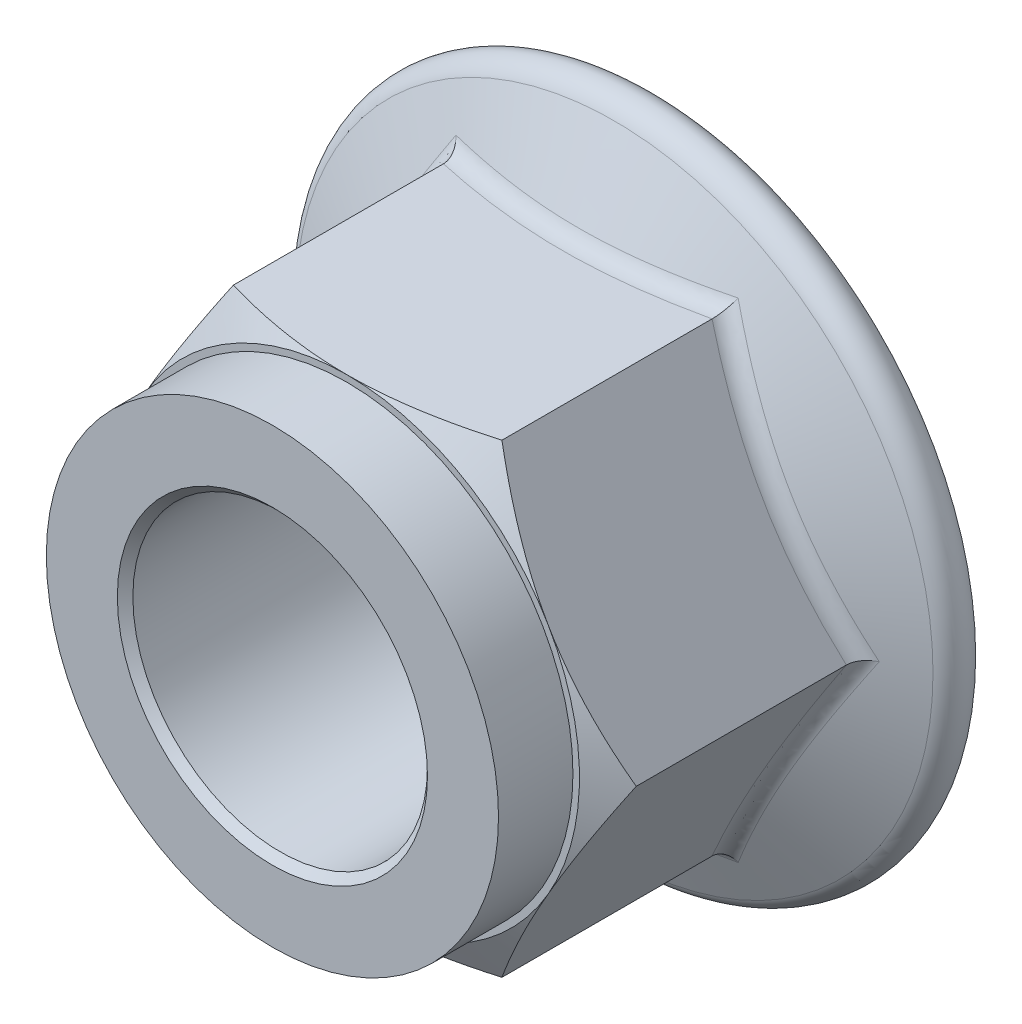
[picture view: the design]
ISO-10303-21;
HEADER;
FILE_DESCRIPTION(('STEP AP214'),'2;1');
FILE_NAME('part.step','',(''),(''),'','','');
FILE_SCHEMA(('AUTOMOTIVE_DESIGN { 1 0 10303 214 1 1 1 1 }'));
ENDSEC;
DATA;
#1=APPLICATION_CONTEXT('core data for automotive mechanical design processes');
#2=APPLICATION_PROTOCOL_DEFINITION('international standard','automotive_design',2000,#1);
#3=PRODUCT_CONTEXT('',#1,'mechanical');
#4=PRODUCT('Part','Part','',(#3));
#5=PRODUCT_RELATED_PRODUCT_CATEGORY('part','',(#4));
#6=PRODUCT_DEFINITION_FORMATION('','',#4);
#7=PRODUCT_DEFINITION_CONTEXT('part definition',#1,'design');
#8=PRODUCT_DEFINITION('design','',#6,#7);
#9=PRODUCT_DEFINITION_SHAPE('','',#8);
#10=(LENGTH_UNIT() NAMED_UNIT(*) SI_UNIT(.MILLI.,.METRE.));
#11=(NAMED_UNIT(*) PLANE_ANGLE_UNIT() SI_UNIT($,.RADIAN.));
#12=(NAMED_UNIT(*) SI_UNIT($,.STERADIAN.) SOLID_ANGLE_UNIT());
#13=UNCERTAINTY_MEASURE_WITH_UNIT(LENGTH_MEASURE(1.E-05),#10,'distance_accuracy_value','');
#14=(GEOMETRIC_REPRESENTATION_CONTEXT(3) GLOBAL_UNCERTAINTY_ASSIGNED_CONTEXT((#13)) GLOBAL_UNIT_ASSIGNED_CONTEXT((#10,
#11,#12)) REPRESENTATION_CONTEXT('',''));
#15=CARTESIAN_POINT('',(0.,0.,0.));
#16=DIRECTION('',(0.,0.,1.));
#17=DIRECTION('',(1.,0.,0.));
#18=AXIS2_PLACEMENT_3D('',#15,#16,#17);
#19=CARTESIAN_POINT('',(-8.66025403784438,-15.,0.));
#20=DIRECTION('',(0.,0.,-1.));
#21=DIRECTION('',(-1.,0.,0.));
#22=AXIS2_PLACEMENT_3D('',#19,#20,#21);
#23=PLANE('',#22);
#24=CARTESIAN_POINT('',(0.,0.,0.));
#25=DIRECTION('',(0.,0.,-1.));
#26=DIRECTION('',(-1.,0.,0.));
#27=AXIS2_PLACEMENT_3D('',#24,#25,#26);
#28=CIRCLE('',#27,15.);
#29=CARTESIAN_POINT('',(-12.9903810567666,7.5,0.));
#30=VERTEX_POINT('',#29);
#31=CARTESIAN_POINT('',(-12.9903810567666,-7.5,0.));
#32=VERTEX_POINT('',#31);
#33=EDGE_CURVE('E141',#30,#32,#28,.F.);
#34=ORIENTED_EDGE('',*,*,#33,.T.);
#35=CARTESIAN_POINT('',(0.,-15.,0.));
#36=VERTEX_POINT('',#35);
#37=EDGE_CURVE('E702',#32,#36,#28,.F.);
#38=ORIENTED_EDGE('',*,*,#37,.T.);
#39=CARTESIAN_POINT('',(12.9903810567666,-7.5,0.));
#40=VERTEX_POINT('',#39);
#41=EDGE_CURVE('E747',#36,#40,#28,.F.);
#42=ORIENTED_EDGE('',*,*,#41,.T.);
#43=CARTESIAN_POINT('',(12.9903810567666,7.50000000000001,0.));
#44=VERTEX_POINT('',#43);
#45=EDGE_CURVE('E749',#40,#44,#28,.F.);
#46=ORIENTED_EDGE('',*,*,#45,.T.);
#47=CARTESIAN_POINT('',(0.,15.,0.));
#48=VERTEX_POINT('',#47);
#49=EDGE_CURVE('E701',#44,#48,#28,.F.);
#50=ORIENTED_EDGE('',*,*,#49,.T.);
#51=CARTESIAN_POINT('',(0.,0.,0.));
#52=DIRECTION('',(0.,0.,-1.));
#53=DIRECTION('',(-1.,0.,0.));
#54=AXIS2_PLACEMENT_3D('',#51,#52,#53);
#55=CIRCLE('',#54,15.);
#56=EDGE_CURVE('E494',#30,#48,#55,.T.);
#57=ORIENTED_EDGE('',*,*,#56,.F.);
#58=EDGE_LOOP('',(#34,#38,#42,#46,#50,#57));
#59=FACE_BOUND('',#58,.T.);
#60=CARTESIAN_POINT('',(0.,0.,0.));
#61=DIRECTION('',(0.,0.,-1.));
#62=DIRECTION('',(-1.,0.,0.));
#63=AXIS2_PLACEMENT_3D('',#60,#61,#62);
#64=CIRCLE('',#63,14.58);
#65=CARTESIAN_POINT('',(-14.58,0.,0.));
#66=VERTEX_POINT('',#65);
#67=EDGE_CURVE('E12',#66,#66,#64,.F.);
#68=ORIENTED_EDGE('',*,*,#67,.F.);
#69=EDGE_LOOP('',(#68));
#70=FACE_BOUND('',#69,.T.);
#71=ADVANCED_FACE('F37',(#59,#70),#23,.F.);
#72=CARTESIAN_POINT('',(-8.66025403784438,-15.,-20.));
#73=DIRECTION('',(0.,-1.,0.));
#74=DIRECTION('',(1.,0.,0.));
#75=AXIS2_PLACEMENT_3D('',#72,#73,#74);
#76=PLANE('',#75);
#77=DIRECTION('',(0.,0.,1.));
#78=VECTOR('',#77,1.);
#79=CARTESIAN_POINT('',(-8.66025403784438,-15.,-20.));
#80=LINE('',#79,#78);
#81=CARTESIAN_POINT('',(-8.66025403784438,-15.,-14.889067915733));
#82=VERTEX_POINT('',#81);
#83=CARTESIAN_POINT('',(-8.66025403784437,-15.,-1.33974596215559));
#84=VERTEX_POINT('',#83);
#85=EDGE_CURVE('E132',#82,#84,#80,.T.);
#86=ORIENTED_EDGE('',*,*,#85,.F.);
#87=CARTESIAN_POINT('',(-13.2562194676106,-15.,-16.0841712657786));
#88=CARTESIAN_POINT('',(-13.0142086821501,-15.,-16.903696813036));
#89=CARTESIAN_POINT('',(-12.9350537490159,-15.8075136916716,-17.1717406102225));
#90=CARTESIAN_POINT('',(-12.7115536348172,-15.,-15.9233825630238));
#91=CARTESIAN_POINT('',(-12.4776326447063,-15.,-16.7399461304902));
#92=CARTESIAN_POINT('',(-12.3982880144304,-15.8010581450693,-17.010951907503));
#93=CARTESIAN_POINT('',(-12.1652498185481,-15.,-15.7679405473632));
#94=CARTESIAN_POINT('',(-11.938632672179,-15.,-16.581118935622));
#95=CARTESIAN_POINT('',(-11.8605004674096,-15.7944791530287,-16.8555098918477));
#96=CARTESIAN_POINT('',(-11.0689276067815,-15.,-15.4699923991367));
#97=CARTESIAN_POINT('',(-10.8577863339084,-15.,-16.2765193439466));
#98=CARTESIAN_POINT('',(-10.7825991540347,-15.7812643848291,-16.5575617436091));
#99=CARTESIAN_POINT('',(-10.5189079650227,-15.,-15.3274908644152));
#100=CARTESIAN_POINT('',(-10.3159538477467,-15.,-16.130699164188));
#101=CARTESIAN_POINT('',(-10.2424846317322,-15.7746285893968,-16.4150602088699));
#102=CARTESIAN_POINT('',(-9.41282498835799,-15.,-15.0572272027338));
#103=CARTESIAN_POINT('',(-9.22718803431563,-15.,-15.853990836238));
#104=CARTESIAN_POINT('',(-9.15779491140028,-15.7614680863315,-16.1447965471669));
#105=CARTESIAN_POINT('',(-8.85674608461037,-15.,-14.9295282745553));
#106=CARTESIAN_POINT('',(-8.68018565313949,-15.,-15.7230864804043));
#107=CARTESIAN_POINT('',(-8.61321050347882,-15.7549439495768,-16.0170976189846));
#108=CARTESIAN_POINT('',(-7.74075904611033,-15.,-14.6922672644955));
#109=CARTESIAN_POINT('',(-7.58337244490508,-15.,-15.4797854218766));
#110=CARTESIAN_POINT('',(-7.5218545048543,-15.7423264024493,-15.7798366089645));
#111=CARTESIAN_POINT('',(-7.18085128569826,-15.,-14.5827034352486));
#112=CARTESIAN_POINT('',(-7.03341857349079,-15.,-15.3672823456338));
#113=CARTESIAN_POINT('',(-6.97508313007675,-15.7362329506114,-15.670272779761));
#114=CARTESIAN_POINT('',(-6.07246061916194,-15.,-14.3872175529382));
#115=CARTESIAN_POINT('',(-5.94568887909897,-15.,-15.1665218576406));
#116=CARTESIAN_POINT('',(-5.89421812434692,-15.724987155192,-15.4747868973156));
#117=CARTESIAN_POINT('',(-5.52407696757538,-15.,-14.3007374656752));
#118=CARTESIAN_POINT('',(-5.40779071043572,-15.,-15.0775864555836));
#119=CARTESIAN_POINT('',(-5.36018039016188,-15.7198138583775,-15.38830680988));
#120=CARTESIAN_POINT('',(-4.42420547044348,-15.,-14.150200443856));
#121=CARTESIAN_POINT('',(-4.32992237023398,-15.,-14.9228043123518));
#122=CARTESIAN_POINT('',(-4.29038826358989,-15.7105789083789,-15.2377697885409));
#123=CARTESIAN_POINT('',(-3.87271761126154,-15.,-14.0861436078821));
#124=CARTESIAN_POINT('',(-3.78959703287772,-15.,-14.8568427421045));
#125=CARTESIAN_POINT('',(-3.75463386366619,-15.706517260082,-15.1737129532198));
#126=CARTESIAN_POINT('',(-2.76851720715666,-15.,-13.9827718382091));
#127=CARTESIAN_POINT('',(-2.70866149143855,-15.,-14.7504534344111));
#128=CARTESIAN_POINT('',(-2.68293132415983,-15.6998578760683,-15.0703411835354));
#129=CARTESIAN_POINT('',(-2.21580933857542,-15.,-13.9434075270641));
#130=CARTESIAN_POINT('',(-2.16759428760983,-15.,-14.7098796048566));
#131=CARTESIAN_POINT('',(-2.14698572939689,-15.6972572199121,-15.0309768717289));
#132=CARTESIAN_POINT('',(-1.10914769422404,-15.,-13.8907290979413));
#133=CARTESIAN_POINT('',(-1.0850210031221,-15.,-14.6556301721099));
#134=CARTESIAN_POINT('',(-1.07442713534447,-15.6937579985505,-14.9782984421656));
#135=CARTESIAN_POINT('',(-0.555193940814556,-15.,-13.87741451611));
#136=CARTESIAN_POINT('',(-0.542974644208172,-15.,-14.6418994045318));
#137=CARTESIAN_POINT('',(-0.537814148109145,-15.6928594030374,-14.9649838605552));
#138=CARTESIAN_POINT('',(0.554023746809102,-15.,-13.8773750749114));
#139=CARTESIAN_POINT('',(0.541829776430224,-15.,-14.6418588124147));
#140=CARTESIAN_POINT('',(0.536680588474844,-15.6928567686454,-14.9649444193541));
#141=CARTESIAN_POINT('',(1.10928768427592,-15.,-13.8907131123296));
#142=CARTESIAN_POINT('',(1.0851592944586,-15.,-14.655613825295));
#143=CARTESIAN_POINT('',(1.07456234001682,-15.693756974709,-14.9782824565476));
#144=CARTESIAN_POINT('',(2.21856297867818,-15.,-13.9435613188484));
#145=CARTESIAN_POINT('',(2.17028974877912,-15.,-14.7100380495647));
#146=CARTESIAN_POINT('',(2.14965498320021,-15.6972673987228,-15.0311306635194));
#147=CARTESIAN_POINT('',(2.77257431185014,-15.,-13.9830719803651));
#148=CARTESIAN_POINT('',(2.71263477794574,-15.,-14.7507628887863));
#149=CARTESIAN_POINT('',(2.68686586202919,-15.699877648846,-15.0706413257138));
#150=CARTESIAN_POINT('',(3.87937492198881,-15.,-14.0868474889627));
#151=CARTESIAN_POINT('',(3.79611896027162,-15.,-14.8575674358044));
#152=CARTESIAN_POINT('',(3.76109843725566,-15.7065621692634,-15.1744168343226));
#153=CARTESIAN_POINT('',(4.43215947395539,-15.,-14.1511621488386));
#154=CARTESIAN_POINT('',(4.3377180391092,-15.,-14.9237944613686));
#155=CARTESIAN_POINT('',(4.29811756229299,-15.7106393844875,-15.2387314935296));
#156=CARTESIAN_POINT('',(5.53460601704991,-15.,-14.3023077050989));
#157=CARTESIAN_POINT('',(5.41811741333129,-15.,-15.079201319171));
#158=CARTESIAN_POINT('',(5.37042879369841,-15.7199086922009,-15.3898770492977));
#159=CARTESIAN_POINT('',(6.08426802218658,-15.,-14.3891385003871));
#160=CARTESIAN_POINT('',(5.95727475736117,-15.,-15.1684968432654));
#161=CARTESIAN_POINT('',(5.90572090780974,-15.7251007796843,-15.4767078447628));
#162=CARTESIAN_POINT('',(7.19527000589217,-15.,-14.5854164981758));
#163=CARTESIAN_POINT('',(7.04757990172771,-15.,-15.370068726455));
#164=CARTESIAN_POINT('',(6.98915577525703,-15.73638575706,-15.6729858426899));
#165=CARTESIAN_POINT('',(7.75650993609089,-15.,-14.6954252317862));
#166=CARTESIAN_POINT('',(7.5988498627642,-15.,-15.4830272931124));
#167=CARTESIAN_POINT('',(7.53724217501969,-15.7424996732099,-15.7829945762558));
#168=CARTESIAN_POINT('',(8.87514240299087,-15.,-14.9336360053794));
#169=CARTESIAN_POINT('',(8.69828063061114,-15.,-15.7272985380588));
#170=CARTESIAN_POINT('',(8.63121688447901,-15.7551568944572,-16.0212053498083));
#171=CARTESIAN_POINT('',(9.43253456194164,-15.,-15.0618398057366));
#172=CARTESIAN_POINT('',(9.24658443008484,-15.,-15.8587181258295));
#173=CARTESIAN_POINT('',(9.17710497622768,-15.7617002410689,-16.1494091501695));
#174=CARTESIAN_POINT('',(10.5412099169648,-15.,-15.3331508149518));
#175=CARTESIAN_POINT('',(10.3379234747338,-15.,-16.1364932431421));
#176=CARTESIAN_POINT('',(10.2643741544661,-15.7748964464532,-16.4207201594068));
#177=CARTESIAN_POINT('',(11.0925088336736,-15.,-15.4761943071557));
#178=CARTESIAN_POINT('',(10.8810272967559,-15.,-16.2828647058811));
#179=CARTESIAN_POINT('',(10.8057645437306,-15.7815487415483,-16.5637636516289));
#180=CARTESIAN_POINT('',(12.1913752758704,-15.,-15.7752555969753));
#181=CARTESIAN_POINT('',(11.9644062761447,-15.,-16.5885951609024));
#182=CARTESIAN_POINT('',(11.8862075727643,-15.7947936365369,-16.8628249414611));
#183=CARTESIAN_POINT('',(12.7389440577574,-15.,-15.9312687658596));
#184=CARTESIAN_POINT('',(12.504666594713,-15.,-16.7480018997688));
#185=CARTESIAN_POINT('',(12.4252609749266,-15.8013862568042,-17.0188381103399));
#186=CARTESIAN_POINT('',(13.2848699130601,-15.,-16.0926373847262));
#187=CARTESIAN_POINT('',(13.0424944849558,-15.,-16.9123380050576));
#188=CARTESIAN_POINT('',(12.9632889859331,-15.8078538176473,-17.1802067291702));
#189=(BOUNDED_SURFACE() B_SPLINE_SURFACE(3,2,((#87,#88,#89),(#90,#91,#92),(#93,#94,#95),(#96,
#97,#98),(#99,#100,#101),(#102,#103,#104),(#105,#106,#107),(#108,#109,#110),(#111,#112,#113),
(#114,#115,#116),(#117,#118,#119),(#120,#121,#122),(#123,#124,#125),(#126,#127,#128),(#129,#130,
#131),(#132,#133,#134),(#135,#136,#137),(#138,#139,#140),(#141,#142,#143),(#144,#145,#146),
(#147,#148,#149),(#150,#151,#152),(#153,#154,#155),(#156,#157,#158),(#159,#160,#161),(#162,#163,
#164),(#165,#166,#167),(#168,#169,#170),(#171,#172,#173),(#174,#175,#176),(#177,#178,#179),
(#180,#181,#182),(#183,#184,#185),(#186,#187,#188)),.UNSPECIFIED.,.F.,.F.,
.F.) B_SPLINE_SURFACE_WITH_KNOTS((4,2,2,2,2,2,2,2,2,2,2,2,2,2,2,2,4),(3,3),(0.,1.70376719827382,
3.40813740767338,5.11953535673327,6.83076831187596,8.49583868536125,10.1609163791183,
11.8226537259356,13.4843614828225,15.149995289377,16.8156604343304,18.4846882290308,
20.1537085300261,21.8691183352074,23.5846942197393,25.2931870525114,27.0010727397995),(0.,1.),
.UNSPECIFIED.) GEOMETRIC_REPRESENTATION_ITEM() RATIONAL_B_SPLINE_SURFACE(((1.,0.814577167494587,
1.),(1.,0.816228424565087,1.),(1.,0.81790581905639,1.),(1.,0.821264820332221,1.),(1.,
0.82294642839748,1.),(1.,0.826271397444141,1.),(1.,0.827914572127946,1.),(1.,0.831083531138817,
1.),(1.,0.832609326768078,1.),(1.,0.835418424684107,1.),(1.,0.836707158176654,1.),(1.,
0.839003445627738,1.),(1.,0.840010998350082,1.),(1.,0.841661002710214,1.),(1.,0.842304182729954,
1.),(1.,0.84316923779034,1.),(1.,0.8433911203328,1.),(1.,0.843391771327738,1.),(1.,
0.843169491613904,1.),(1.,0.842301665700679,1.),(1.,0.841656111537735,1.),(1.,0.839999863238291,
1.),(1.,0.838988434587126,1.),(1.,0.836683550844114,1.),(1.,0.835390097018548,1.),(1.,
0.8325710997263,1.),(1.,0.831040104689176,1.),(1.,0.827860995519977,1.),(1.,0.826212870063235,
1.),(1.,0.822878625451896,1.),(1.,0.821192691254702,1.),(1.,0.817825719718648,1.),(1.,
0.816144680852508,1.),(1.,0.81449017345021,1.))) REPRESENTATION_ITEM('') SURFACE());
#190=CARTESIAN_POINT('',(-13.2562194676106,-15.,-16.0841712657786));
#191=CARTESIAN_POINT('',(-12.7115536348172,-15.,-15.9233825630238));
#192=CARTESIAN_POINT('',(-12.1652498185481,-15.,-15.7679405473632));
#193=CARTESIAN_POINT('',(-11.0689276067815,-15.,-15.4699923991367));
#194=CARTESIAN_POINT('',(-10.5189079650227,-15.,-15.3274908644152));
#195=CARTESIAN_POINT('',(-9.41282498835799,-15.,-15.0572272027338));
#196=CARTESIAN_POINT('',(-8.85674608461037,-15.,-14.9295282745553));
#197=CARTESIAN_POINT('',(-7.74075904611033,-15.,-14.6922672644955));
#198=CARTESIAN_POINT('',(-7.18085128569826,-15.,-14.5827034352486));
#199=CARTESIAN_POINT('',(-6.07246061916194,-15.,-14.3872175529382));
#200=CARTESIAN_POINT('',(-5.52407696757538,-15.,-14.3007374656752));
#201=CARTESIAN_POINT('',(-4.42420547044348,-15.,-14.150200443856));
#202=CARTESIAN_POINT('',(-3.87271761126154,-15.,-14.0861436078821));
#203=CARTESIAN_POINT('',(-2.76851720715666,-15.,-13.9827718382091));
#204=CARTESIAN_POINT('',(-2.21580933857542,-15.,-13.9434075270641));
#205=CARTESIAN_POINT('',(-1.10914769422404,-15.,-13.8907290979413));
#206=CARTESIAN_POINT('',(-0.555193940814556,-15.,-13.87741451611));
#207=CARTESIAN_POINT('',(0.554023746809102,-15.,-13.8773750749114));
#208=CARTESIAN_POINT('',(1.10928768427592,-15.,-13.8907131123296));
#209=CARTESIAN_POINT('',(2.21856297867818,-15.,-13.9435613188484));
#210=CARTESIAN_POINT('',(2.77257431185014,-15.,-13.9830719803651));
#211=CARTESIAN_POINT('',(3.87937492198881,-15.,-14.0868474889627));
#212=CARTESIAN_POINT('',(4.43215947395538,-15.,-14.1511621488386));
#213=CARTESIAN_POINT('',(5.53460601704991,-15.,-14.3023077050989));
#214=CARTESIAN_POINT('',(6.08426802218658,-15.,-14.3891385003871));
#215=CARTESIAN_POINT('',(7.19527000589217,-15.,-14.5854164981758));
#216=CARTESIAN_POINT('',(7.75650993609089,-15.,-14.6954252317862));
#217=CARTESIAN_POINT('',(8.87514240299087,-15.,-14.9336360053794));
#218=CARTESIAN_POINT('',(9.43253456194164,-15.,-15.0618398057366));
#219=CARTESIAN_POINT('',(10.5412099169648,-15.,-15.3331508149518));
#220=CARTESIAN_POINT('',(11.0925088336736,-15.,-15.4761943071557));
#221=CARTESIAN_POINT('',(12.1913752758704,-15.,-15.7752555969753));
#222=CARTESIAN_POINT('',(12.7389440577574,-15.,-15.9312687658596));
#223=CARTESIAN_POINT('',(13.2848699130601,-15.,-16.0926373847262));
#224=B_SPLINE_CURVE_WITH_KNOTS('',3,(#190,#191,#192,#193,#194,#195,#196,#197,#198,#199,#200,
#201,#202,#203,#204,#205,#206,#207,#208,#209,#210,#211,#212,#213,#214,#215,#216,#217,#218,#219,
#220,#221,#222,#223),.UNSPECIFIED.,.F.,.F.,(4,2,2,2,2,2,2,2,2,2,2,2,2,2,2,2,4),(0.,
1.70376719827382,3.40813740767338,5.11953535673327,6.83076831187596,8.49583868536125,
10.1609163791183,11.8226537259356,13.4843614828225,15.149995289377,16.8156604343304,
18.4846882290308,20.1537085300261,21.8691183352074,23.5846942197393,25.2931870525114,
27.0010727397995),.UNSPECIFIED.);
#225=CARTESIAN_POINT('',(8.66025403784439,-15.,-14.889067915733));
#226=VERTEX_POINT('',#225);
#227=EDGE_CURVE('E45',#82,#226,#224,.T.);
#228=ORIENTED_EDGE('',*,*,#227,.T.);
#229=DIRECTION('',(0.,0.,1.));
#230=VECTOR('',#229,1.);
#231=CARTESIAN_POINT('',(8.66025403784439,-15.,-20.));
#232=LINE('',#231,#230);
#233=CARTESIAN_POINT('',(8.66025403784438,-15.,-1.3397459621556));
#234=VERTEX_POINT('',#233);
#235=EDGE_CURVE('E691',#226,#234,#232,.T.);
#236=ORIENTED_EDGE('',*,*,#235,.T.);
#237=CARTESIAN_POINT('',(-22.9682699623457,-15.,-7.17790057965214));
#238=CARTESIAN_POINT('',(-22.6389897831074,-15.,-7.0187314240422));
#239=CARTESIAN_POINT('',(-22.3093116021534,-15.,-6.86038603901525));
#240=CARTESIAN_POINT('',(-21.6490751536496,-15.,-6.54553189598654));
#241=CARTESIAN_POINT('',(-21.3185168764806,-15.,-6.38902315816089));
#242=CARTESIAN_POINT('',(-20.3252989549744,-15.,-5.92249019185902));
#243=CARTESIAN_POINT('',(-19.6612032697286,-15.,-5.6155111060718));
#244=CARTESIAN_POINT('',(-18.3246226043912,-15.,-5.00989859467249));
#245=CARTESIAN_POINT('',(-17.6521113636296,-15.,-4.71132298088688));
#246=CARTESIAN_POINT('',(-16.3015621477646,-15.,-4.12699119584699));
#247=CARTESIAN_POINT('',(-15.6235244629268,-15.,-3.84123435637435));
#248=CARTESIAN_POINT('',(-14.2524269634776,-15.,-3.28256457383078));
#249=CARTESIAN_POINT('',(-13.5592849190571,-15.,-3.00985238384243));
#250=CARTESIAN_POINT('',(-12.1648203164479,-15.,-2.48578579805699));
#251=CARTESIAN_POINT('',(-11.4634968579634,-15.,-2.23443377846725));
#252=CARTESIAN_POINT('',(-10.0530172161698,-15.,-1.75984469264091));
#253=CARTESIAN_POINT('',(-9.34388131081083,-15.,-1.5365478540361));
#254=CARTESIAN_POINT('',(-7.91545988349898,-15.,-1.12531011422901));
#255=CARTESIAN_POINT('',(-7.19617764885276,-15.,-0.937358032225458));
#256=CARTESIAN_POINT('',(-6.10950776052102,-15.,-0.688818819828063));
#257=CARTESIAN_POINT('',(-5.74591626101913,-15.,-0.611524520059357));
#258=CARTESIAN_POINT('',(-5.01631310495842,-15.,-0.469286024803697));
#259=CARTESIAN_POINT('',(-4.65030150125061,-15.,-0.404341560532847));
#260=CARTESIAN_POINT('',(-3.91609659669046,-15.,-0.287952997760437));
#261=CARTESIAN_POINT('',(-3.5479031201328,-15.,-0.236510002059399));
#262=CARTESIAN_POINT('',(-2.80977894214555,-15.,-0.148161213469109));
#263=CARTESIAN_POINT('',(-2.43984831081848,-15.,-0.11125483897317));
#264=CARTESIAN_POINT('',(-1.70111543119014,-15.,-0.0529692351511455));
#265=CARTESIAN_POINT('',(-1.3323208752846,-15.,-0.0314931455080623));
#266=CARTESIAN_POINT('',(-0.594154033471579,-15.,-0.00418216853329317));
#267=CARTESIAN_POINT('',(-0.224781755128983,-15.,0.00165292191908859));
#268=CARTESIAN_POINT('',(0.513772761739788,-15.,-0.00245653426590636));
#269=CARTESIAN_POINT('',(0.882955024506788,-15.,-0.0123966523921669));
#270=CARTESIAN_POINT('',(1.62057875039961,-15.,-0.0478095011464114));
#271=CARTESIAN_POINT('',(1.98902017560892,-15.,-0.073283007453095));
#272=CARTESIAN_POINT('',(2.88200878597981,-15.,-0.153315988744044));
#273=CARTESIAN_POINT('',(3.40586988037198,-15.,-0.215658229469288));
#274=CARTESIAN_POINT('',(4.44957771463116,-15.,-0.368284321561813));
#275=CARTESIAN_POINT('',(4.9694233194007,-15.,-0.458575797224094));
#276=CARTESIAN_POINT('',(6.00467140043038,-15.,-0.663898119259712));
#277=CARTESIAN_POINT('',(6.52006919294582,-15.,-0.778952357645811));
#278=CARTESIAN_POINT('',(7.54556200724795,-15.,-1.030289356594));
#279=CARTESIAN_POINT('',(8.0556575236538,-15.,-1.16657011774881));
#280=CARTESIAN_POINT('',(9.08310964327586,-15.,-1.46066370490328));
#281=CARTESIAN_POINT('',(9.60033774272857,-15.,-1.6189224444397));
#282=CARTESIAN_POINT('',(10.6293258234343,-15.,-1.95107200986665));
#283=CARTESIAN_POINT('',(11.1410893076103,-15.,-2.12495205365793));
#284=CARTESIAN_POINT('',(12.157099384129,-15.,-2.48477464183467));
#285=CARTESIAN_POINT('',(12.6613720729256,-15.,-2.67064378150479));
#286=CARTESIAN_POINT('',(13.4147912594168,-15.,-2.95756327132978));
#287=CARTESIAN_POINT('',(13.6654863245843,-15.,-3.05457748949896));
#288=CARTESIAN_POINT('',(14.1659013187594,-15.,-3.25107322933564));
#289=CARTESIAN_POINT('',(14.4156212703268,-15.,-3.35055469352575));
#290=CARTESIAN_POINT('',(14.6648887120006,-15.,-3.45115877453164));
#291=B_SPLINE_CURVE_WITH_KNOTS('',3,(#237,#238,#239,#240,#241,#242,#243,#244,#245,#246,#247,
#248,#249,#250,#251,#252,#253,#254,#255,#256,#257,#258,#259,#260,#261,#262,#263,#264,#265,#266,
#267,#268,#269,#270,#271,#272,#273,#274,#275,#276,#277,#278,#279,#280,#281,#282,#283,#284,#285,
#286,#287,#288,#289,#290),.UNSPECIFIED.,.F.,.F.,(4,2,2,2,2,2,2,2,2,2,2,2,2,2,2,2,2,2,2,2,2,2,2,
2,2,2,4),(0.,1.09719534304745,2.19440272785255,4.38917437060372,6.596505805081,8.80372204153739,
11.0380360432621,13.2725982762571,15.5023159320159,17.7313270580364,18.8463006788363,
19.9612500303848,21.0762904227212,22.1912861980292,23.2992201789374,24.407139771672,
25.5147483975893,26.6224123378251,28.2042036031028,29.7864267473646,31.3701511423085,
32.9537264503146,34.5761185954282,36.1973994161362,37.8095545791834,38.6159794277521,
39.4223855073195),.UNSPECIFIED.);
#292=EDGE_CURVE('E207',#36,#234,#291,.T.);
#293=ORIENTED_EDGE('',*,*,#292,.F.);
#294=EDGE_CURVE('E214',#84,#36,#291,.T.);
#295=ORIENTED_EDGE('',*,*,#294,.F.);
#296=EDGE_LOOP('',(#86,#228,#236,#293,#295));
#297=FACE_BOUND('',#296,.T.);
#298=ADVANCED_FACE('F215',(#297),#76,.T.);
#299=CARTESIAN_POINT('',(-17.3205080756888,0.,-20.));
#300=DIRECTION('',(-0.866025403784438,-0.5,0.));
#301=DIRECTION('',(0.5,-0.866025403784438,0.));
#302=AXIS2_PLACEMENT_3D('',#299,#300,#301);
#303=PLANE('',#302);
#304=DIRECTION('',(0.,0.,1.));
#305=VECTOR('',#304,1.);
#306=CARTESIAN_POINT('',(-17.3205080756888,0.,-20.));
#307=LINE('',#306,#305);
#308=CARTESIAN_POINT('',(-17.3205080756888,0.,-14.889067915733));
#309=VERTEX_POINT('',#308);
#310=CARTESIAN_POINT('',(-17.3205080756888,0.,-1.33974596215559));
#311=VERTEX_POINT('',#310);
#312=EDGE_CURVE('E125',#309,#311,#307,.T.);
#313=ORIENTED_EDGE('',*,*,#312,.F.);
#314=CARTESIAN_POINT('',(-19.5869636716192,3.92561624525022,-16.0655775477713));
#315=CARTESIAN_POINT('',(-19.4663607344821,3.71672583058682,-16.8847177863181));
#316=CARTESIAN_POINT('',(-20.1255182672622,3.24489093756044,-17.1531468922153));
#317=CARTESIAN_POINT('',(-19.3166826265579,3.45747574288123,-15.9064549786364));
#318=CARTESIAN_POINT('',(-19.2001040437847,3.25555571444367,-16.7226516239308));
#319=CARTESIAN_POINT('',(-19.8536259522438,2.78678610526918,-16.9940243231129));
#320=CARTESIAN_POINT('',(-19.0455921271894,2.98793322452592,-15.7526340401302));
#321=CARTESIAN_POINT('',(-18.932651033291,2.79231351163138,-16.5654726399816));
#322=CARTESIAN_POINT('',(-19.5811259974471,2.32786719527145,-16.8402033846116));
#323=CARTESIAN_POINT('',(-18.5015795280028,2.04567576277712,-15.4577952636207));
#324=CARTESIAN_POINT('',(-18.3963425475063,1.86339996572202,-16.2640376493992));
#325=CARTESIAN_POINT('',(-19.0349364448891,1.40807023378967,-16.5453646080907));
#326=CARTESIAN_POINT('',(-18.2286568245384,1.57295977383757,-15.3167818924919));
#327=CARTESIAN_POINT('',(-18.1274930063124,1.3977389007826,-16.1197341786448));
#328=CARTESIAN_POINT('',(-18.7612464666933,0.947191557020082,-16.4043512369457));
#329=CARTESIAN_POINT('',(-17.67984590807,0.622391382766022,-15.0493314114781));
#330=CARTESIAN_POINT('',(-17.5872936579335,0.462086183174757,-15.8458961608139));
#331=CARTESIAN_POINT('',(-18.2117814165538,0.0215920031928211,-16.1369007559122));
#332=CARTESIAN_POINT('',(-17.4039501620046,0.144525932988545,-14.922955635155));
#333=CARTESIAN_POINT('',(-17.3159092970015,-0.0079653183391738,-15.716344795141));
#334=CARTESIAN_POINT('',(-17.9360023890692,-0.443136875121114,-16.0105249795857));
#335=CARTESIAN_POINT('',(-16.8502740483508,-0.814469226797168,-14.6880992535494));
#336=CARTESIAN_POINT('',(-16.7717588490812,-0.950461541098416,-15.4755041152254));
#337=CARTESIAN_POINT('',(-17.3837396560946,-1.3746730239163,-15.7756685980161));
#338=CARTESIAN_POINT('',(-16.5724938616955,-1.29559862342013,-14.5796169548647));
#339=CARTESIAN_POINT('',(-16.4989221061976,-1.42302864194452,-15.3641105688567));
#340=CARTESIAN_POINT('',(-17.1072560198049,-1.84148009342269,-15.6671862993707));
#341=CARTESIAN_POINT('',(-16.0225443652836,-2.24813909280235,-14.3859363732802));
#342=CARTESIAN_POINT('',(-15.9592302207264,-2.35780240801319,-15.1652022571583));
#343=CARTESIAN_POINT('',(-16.5613204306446,-2.76477257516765,-15.4735057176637));
#344=CARTESIAN_POINT('',(-15.7504234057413,-2.71946642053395,-14.3001934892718));
#345=CARTESIAN_POINT('',(-15.6923146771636,-2.82011369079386,-15.0770255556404));
#346=CARTESIAN_POINT('',(-16.2918779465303,-3.22120058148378,-15.3877628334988));
#347=CARTESIAN_POINT('',(-15.2046530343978,-3.66476843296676,-14.1507918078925));
#348=CARTESIAN_POINT('',(-15.1574624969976,-3.74650484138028,-14.9234107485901));
#349=CARTESIAN_POINT('',(-15.7530958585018,-4.1360680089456,-15.2383611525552));
#350=CARTESIAN_POINT('',(-14.9310036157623,-4.13874312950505,-14.087133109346));
#351=CARTESIAN_POINT('',(-14.8893522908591,-4.21088534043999,-14.8578604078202));
#352=CARTESIAN_POINT('',(-15.4837562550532,-4.59450743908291,-15.1747024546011));
#353=CARTESIAN_POINT('',(-14.3830923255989,-5.08775332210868,-13.9841681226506));
#354=CARTESIAN_POINT('',(-14.3529813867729,-5.139906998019,-14.7518903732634));
#355=CARTESIAN_POINT('',(-14.9462203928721,-5.51228457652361,-15.0717374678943));
#356=CARTESIAN_POINT('',(-14.108832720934,-5.5627848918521,-13.9448141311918));
#357=CARTESIAN_POINT('',(-14.0844976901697,-5.60493440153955,-14.7113282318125));
#358=CARTESIAN_POINT('',(-14.6780229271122,-5.97161873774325,-15.0323834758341));
#359=CARTESIAN_POINT('',(-13.5596909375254,-6.51392636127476,-13.8917477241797));
#360=CARTESIAN_POINT('',(-13.5473047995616,-6.53537978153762,-14.6566795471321));
#361=CARTESIAN_POINT('',(-14.1427437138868,-6.89170174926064,-14.9793170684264));
#362=CARTESIAN_POINT('',(-13.2848087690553,-6.99003624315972,-13.8780348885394));
#363=CARTESIAN_POINT('',(-13.2783319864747,-7.00125435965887,-14.6425383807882));
#364=CARTESIAN_POINT('',(-13.8756619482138,-7.35245057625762,-14.9656042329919));
#365=CARTESIAN_POINT('',(-12.7327569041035,-7.94621812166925,-13.8767935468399));
#366=CARTESIAN_POINT('',(-12.7384304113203,-7.93639131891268,-14.6412598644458));
#367=CARTESIAN_POINT('',(-13.3408192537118,-8.27865873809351,-14.9643628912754));
#368=CARTESIAN_POINT('',(-12.4555870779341,-8.42629034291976,-13.8894823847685));
#369=CARTESIAN_POINT('',(-12.4672197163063,-8.40614202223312,-14.6543453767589));
#370=CARTESIAN_POINT('',(-13.0730709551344,-8.74412553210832,-14.9770517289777));
#371=CARTESIAN_POINT('',(-11.9018569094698,-9.38537912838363,-13.9409693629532));
#372=CARTESIAN_POINT('',(-11.9255486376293,-9.34434385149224,-14.7073683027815));
#373=CARTESIAN_POINT('',(-12.5393803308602,-9.67534824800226,-15.028538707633));
#374=CARTESIAN_POINT('',(-11.6252965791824,-9.86439567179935,-13.9797680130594));
#375=CARTESIAN_POINT('',(-11.6548169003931,-9.81326497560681,-14.7473598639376));
#376=CARTESIAN_POINT('',(-12.2734380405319,-10.1411041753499,-15.0673373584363));
#377=CARTESIAN_POINT('',(-11.0727770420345,-10.8213875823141,-14.082083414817));
#378=CARTESIAN_POINT('',(-11.1139499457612,-10.7500740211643,-14.8526638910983));
#379=CARTESIAN_POINT('',(-11.7429156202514,-11.0731906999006,-15.1696527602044));
#380=CARTESIAN_POINT('',(-10.7968201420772,-11.2993589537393,-14.1456494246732));
#381=CARTESIAN_POINT('',(-10.8435846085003,-11.2183605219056,-14.9181218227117));
#382=CARTESIAN_POINT('',(-11.4783392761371,-11.5395205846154,-15.2332187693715));
#383=CARTESIAN_POINT('',(-10.2464539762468,-12.2526211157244,-14.2952887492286));
#384=CARTESIAN_POINT('',(-10.3042434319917,-12.1525268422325,-15.071984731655));
#385=CARTESIAN_POINT('',(-10.9510132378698,-12.4712590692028,-15.3828580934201));
#386=CARTESIAN_POINT('',(-9.97204470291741,-12.7279119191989,-14.3813619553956));
#387=CARTESIAN_POINT('',(-10.0350883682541,-12.6187170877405,-15.1605045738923));
#388=CARTESIAN_POINT('',(-10.6882635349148,-12.936667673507,-15.4689312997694));
#389=CARTESIAN_POINT('',(-9.41742229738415,-13.6885461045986,-14.576102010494));
#390=CARTESIAN_POINT('',(-9.49082134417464,-13.5614152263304,-15.3605048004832));
#391=CARTESIAN_POINT('',(-10.1571629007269,-13.87900092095,-15.6636713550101));
#392=CARTESIAN_POINT('',(-9.1372586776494,-14.1738037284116,-14.6853281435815));
#393=CARTESIAN_POINT('',(-9.21564653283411,-14.0380319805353,-15.4726650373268));
#394=CARTESIAN_POINT('',(-9.88885816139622,-14.3558878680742,-15.7728974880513));
#395=CARTESIAN_POINT('',(-8.57884759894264,-15.1410000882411,-14.9219929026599));
#396=CARTESIAN_POINT('',(-8.66684700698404,-14.9885806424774,-15.7153621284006));
#397=CARTESIAN_POINT('',(-9.35372166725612,-15.307986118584,-16.0095622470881));
#398=CARTESIAN_POINT('',(-8.30060032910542,-15.6229384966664,-15.0494333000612));
#399=CARTESIAN_POINT('',(-8.39314955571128,-15.4626385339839,-15.8460060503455));
#400=CARTESIAN_POINT('',(-9.08689005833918,-15.7831972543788,-16.1370026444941));
#401=CARTESIAN_POINT('',(-7.74714281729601,-16.581555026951,-15.3192526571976));
#402=CARTESIAN_POINT('',(-7.84837391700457,-16.4062176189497,-16.1222680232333));
#403=CARTESIAN_POINT('',(-8.55556548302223,-16.7298037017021,-16.4068220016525));
#404=CARTESIAN_POINT('',(-7.47192481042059,-17.0582465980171,-15.4615684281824));
#405=CARTESIAN_POINT('',(-7.57726039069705,-16.8758000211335,-16.2679029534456));
#406=CARTESIAN_POINT('',(-8.29106741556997,-17.201206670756,-16.5491377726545));
#407=CARTESIAN_POINT('',(-6.92335285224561,-18.0084011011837,-15.7592035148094));
#408=CARTESIAN_POINT('',(-7.03644742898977,-17.8125155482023,-16.5721917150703));
#409=CARTESIAN_POINT('',(-7.76319186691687,-18.1419645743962,-16.8467728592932));
#410=CARTESIAN_POINT('',(-6.6499982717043,-18.4818651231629,-15.9145181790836));
#411=CARTESIAN_POINT('',(-6.76675438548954,-18.2796376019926,-16.7308938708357));
#412=CARTESIAN_POINT('',(-7.49981402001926,-18.6113201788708,-17.0020875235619));
#413=CARTESIAN_POINT('',(-6.37746539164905,-18.9539059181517,-16.0752036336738));
#414=CARTESIAN_POINT('',(-6.49827703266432,-18.7446540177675,-16.8945434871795));
#415=CARTESIAN_POINT('',(-7.23684227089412,-19.0797270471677,-17.1627729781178));
#416=(BOUNDED_SURFACE() B_SPLINE_SURFACE(3,2,((#314,#315,#316),(#317,#318,#319),(#320,#321,
#322),(#323,#324,#325),(#326,#327,#328),(#329,#330,#331),(#332,#333,#334),(#335,#336,#337),
(#338,#339,#340),(#341,#342,#343),(#344,#345,#346),(#347,#348,#349),(#350,#351,#352),(#353,#354,
#355),(#356,#357,#358),(#359,#360,#361),(#362,#363,#364),(#365,#366,#367),(#368,#369,#370),
(#371,#372,#373),(#374,#375,#376),(#377,#378,#379),(#380,#381,#382),(#383,#384,#385),(#386,#387,
#388),(#389,#390,#391),(#392,#393,#394),(#395,#396,#397),(#398,#399,#400),(#401,#402,#403),
(#404,#405,#406),(#407,#408,#409),(#410,#411,#412),(#413,#414,#415)),.UNSPECIFIED.,.F.,.F.,
.F.) B_SPLINE_SURFACE_WITH_KNOTS((4,2,2,2,2,2,2,2,2,2,2,2,2,2,2,2,4),(3,3),(0.,1.69054342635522,
3.38167421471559,5.07965265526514,6.77747031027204,8.42993159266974,10.0824002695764,
11.7316152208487,13.3808031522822,15.0436212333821,16.7064717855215,18.3726464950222,
20.0388131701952,21.7510843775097,23.4635222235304,25.1689606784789,26.8737914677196),(0.,1.),
.UNSPECIFIED.) GEOMETRIC_REPRESENTATION_ITEM() RATIONAL_B_SPLINE_SURFACE(((1.,0.814768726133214,
1.),(1.,0.816408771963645,1.),(1.,0.818073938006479,1.),(1.,0.821407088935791,1.),(1.,
0.823075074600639,1.),(1.,0.826371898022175,1.),(1.,0.828000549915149,1.),(1.,0.831141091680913,
1.),(1.,0.832652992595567,1.),(1.,0.835437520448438,1.),(1.,0.836715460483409,1.),(1.,
0.838994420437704,1.),(1.,0.839995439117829,1.),(1.,0.841638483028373,1.),(1.,0.842281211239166,
1.),(1.,0.843152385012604,1.),(1.,0.843380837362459,1.),(1.,0.843401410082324,1.),(1.,
0.843189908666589,1.),(1.,0.842344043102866,1.),(1.,0.841709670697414,1.),(1.,0.840075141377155,
1.),(1.,0.839074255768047,1.),(1.,0.836788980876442,1.),(1.,0.835504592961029,1.),(1.,
0.832702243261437,1.),(1.,0.831178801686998,1.),(1.,0.82801277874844,1.),(1.,0.826370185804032,
1.),(1.,0.823045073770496,1.),(1.,0.821362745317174,1.),(1.,0.818001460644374,1.),(1.,
0.816322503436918,1.),(1.,0.814669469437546,1.))) REPRESENTATION_ITEM('') SURFACE());
#417=CARTESIAN_POINT('',(-19.5869636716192,3.92561624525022,-16.0655775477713));
#418=CARTESIAN_POINT('',(-19.3166826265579,3.45747574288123,-15.9064549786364));
#419=CARTESIAN_POINT('',(-19.0455921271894,2.98793322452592,-15.7526340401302));
#420=CARTESIAN_POINT('',(-18.5015795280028,2.04567576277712,-15.4577952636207));
#421=CARTESIAN_POINT('',(-18.2286568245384,1.57295977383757,-15.3167818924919));
#422=CARTESIAN_POINT('',(-17.67984590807,0.622391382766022,-15.0493314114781));
#423=CARTESIAN_POINT('',(-17.4039501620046,0.144525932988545,-14.922955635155));
#424=CARTESIAN_POINT('',(-16.8502740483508,-0.814469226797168,-14.6880992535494));
#425=CARTESIAN_POINT('',(-16.5724938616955,-1.29559862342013,-14.5796169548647));
#426=CARTESIAN_POINT('',(-16.0225443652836,-2.24813909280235,-14.3859363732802));
#427=CARTESIAN_POINT('',(-15.7504234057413,-2.71946642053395,-14.3001934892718));
#428=CARTESIAN_POINT('',(-15.2046530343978,-3.66476843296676,-14.1507918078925));
#429=CARTESIAN_POINT('',(-14.9310036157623,-4.13874312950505,-14.087133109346));
#430=CARTESIAN_POINT('',(-14.3830923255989,-5.08775332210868,-13.9841681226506));
#431=CARTESIAN_POINT('',(-14.108832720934,-5.5627848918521,-13.9448141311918));
#432=CARTESIAN_POINT('',(-13.5596909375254,-6.51392636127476,-13.8917477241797));
#433=CARTESIAN_POINT('',(-13.2848087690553,-6.99003624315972,-13.8780348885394));
#434=CARTESIAN_POINT('',(-12.7327569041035,-7.94621812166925,-13.8767935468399));
#435=CARTESIAN_POINT('',(-12.4555870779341,-8.42629034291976,-13.8894823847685));
#436=CARTESIAN_POINT('',(-11.9018569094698,-9.38537912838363,-13.9409693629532));
#437=CARTESIAN_POINT('',(-11.6252965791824,-9.86439567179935,-13.9797680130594));
#438=CARTESIAN_POINT('',(-11.0727770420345,-10.8213875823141,-14.082083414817));
#439=CARTESIAN_POINT('',(-10.7968201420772,-11.2993589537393,-14.1456494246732));
#440=CARTESIAN_POINT('',(-10.2464539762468,-12.2526211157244,-14.2952887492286));
#441=CARTESIAN_POINT('',(-9.97204470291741,-12.7279119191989,-14.3813619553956));
#442=CARTESIAN_POINT('',(-9.41742229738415,-13.6885461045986,-14.576102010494));
#443=CARTESIAN_POINT('',(-9.1372586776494,-14.1738037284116,-14.6853281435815));
#444=CARTESIAN_POINT('',(-8.57884759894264,-15.1410000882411,-14.9219929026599));
#445=CARTESIAN_POINT('',(-8.30060032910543,-15.6229384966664,-15.0494333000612));
#446=CARTESIAN_POINT('',(-7.74714281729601,-16.581555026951,-15.3192526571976));
#447=CARTESIAN_POINT('',(-7.47192481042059,-17.0582465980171,-15.4615684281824));
#448=CARTESIAN_POINT('',(-6.92335285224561,-18.0084011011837,-15.7592035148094));
#449=CARTESIAN_POINT('',(-6.6499982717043,-18.4818651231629,-15.9145181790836));
#450=CARTESIAN_POINT('',(-6.37746539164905,-18.9539059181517,-16.0752036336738));
#451=B_SPLINE_CURVE_WITH_KNOTS('',3,(#417,#418,#419,#420,#421,#422,#423,#424,#425,#426,#427,
#428,#429,#430,#431,#432,#433,#434,#435,#436,#437,#438,#439,#440,#441,#442,#443,#444,#445,#446,
#447,#448,#449,#450),.UNSPECIFIED.,.F.,.F.,(4,2,2,2,2,2,2,2,2,2,2,2,2,2,2,2,4),(0.,
1.69054342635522,3.38167421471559,5.07965265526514,6.77747031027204,8.42993159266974,
10.0824002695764,11.7316152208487,13.3808031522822,15.0436212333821,16.7064717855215,
18.3726464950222,20.0388131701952,21.7510843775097,23.4635222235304,25.1689606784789,
26.8737914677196),.UNSPECIFIED.);
#452=EDGE_CURVE('E52',#309,#82,#451,.T.);
#453=ORIENTED_EDGE('',*,*,#452,.T.);
#454=ORIENTED_EDGE('',*,*,#85,.T.);
#455=CARTESIAN_POINT('',(-17.3206235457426,0.000200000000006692,-1.33981262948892));
#456=CARTESIAN_POINT('',(-17.130274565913,-0.329494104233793,-1.22992178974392));
#457=CARTESIAN_POINT('',(-16.939183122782,-0.660474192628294,-1.1250175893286));
#458=CARTESIAN_POINT('',(-16.5554679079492,-1.32508844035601,-0.926568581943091));
#459=CARTESIAN_POINT('',(-16.3628436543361,-1.65872343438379,-0.833027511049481));
#460=CARTESIAN_POINT('',(-15.9756905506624,-2.32929228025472,-0.65856214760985));
#461=CARTESIAN_POINT('',(-15.7811583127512,-2.666232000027,-0.57766770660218));
#462=CARTESIAN_POINT('',(-15.3907420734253,-3.34245276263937,-0.430232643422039));
#463=CARTESIAN_POINT('',(-15.1948581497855,-3.6817336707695,-0.363691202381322));
#464=CARTESIAN_POINT('',(-14.8067578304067,-4.3539431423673,-0.247792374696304));
#465=CARTESIAN_POINT('',(-14.6145702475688,-4.68682180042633,-0.198051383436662));
#466=CARTESIAN_POINT('',(-14.2293144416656,-5.35410443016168,-0.114646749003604));
#467=CARTESIAN_POINT('',(-14.0362462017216,-5.68850843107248,-0.0809834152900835));
#468=CARTESIAN_POINT('',(-13.6497853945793,-6.35787818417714,-0.0305840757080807));
#469=CARTESIAN_POINT('',(-13.4563934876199,-6.69284279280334,-0.0138279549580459));
#470=CARTESIAN_POINT('',(-13.0694311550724,-7.36308121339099,0.00239660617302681));
#471=CARTESIAN_POINT('',(-12.8758607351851,-7.69835501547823,0.00186558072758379));
#472=CARTESIAN_POINT('',(-12.5139822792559,-8.32514688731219,-0.0152766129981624));
#473=CARTESIAN_POINT('',(-12.3456484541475,-8.61670962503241,-0.0297968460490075));
#474=CARTESIAN_POINT('',(-12.0093680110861,-9.19916443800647,-0.0716371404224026));
#475=CARTESIAN_POINT('',(-11.8414214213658,-9.49005646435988,-0.0989581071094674));
#476=CARTESIAN_POINT('',(-11.5060066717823,-10.0710118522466,-0.165923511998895));
#477=CARTESIAN_POINT('',(-11.338539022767,-10.3610743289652,-0.205578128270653));
#478=CARTESIAN_POINT('',(-11.0043888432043,-10.939839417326,-0.296515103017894));
#479=CARTESIAN_POINT('',(-10.8377063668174,-11.2285419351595,-0.347798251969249));
#480=CARTESIAN_POINT('',(-10.3317324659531,-12.1049144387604,-0.520386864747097));
#481=CARTESIAN_POINT('',(-9.99390625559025,-12.6900465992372,-0.658901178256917));
#482=CARTESIAN_POINT('',(-9.3232912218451,-13.8515859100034,-0.973271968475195));
#483=CARTESIAN_POINT('',(-8.99049381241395,-14.4280079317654,-1.14905461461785));
#484=CARTESIAN_POINT('',(-8.66013856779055,-15.0002,-1.33981262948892));
#485=B_SPLINE_CURVE_WITH_KNOTS('',3,(#455,#456,#457,#458,#459,#460,#461,#462,#463,#464,#465,
#466,#467,#468,#469,#470,#471,#472,#473,#474,#475,#476,#477,#478,#479,#480,#481,#482,#483,#484),
.UNSPECIFIED.,.F.,.F.,(4,2,2,2,2,2,2,2,2,2,2,2,2,2,4),(0.,1.18875411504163,2.37789802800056,
3.56980778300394,4.76164951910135,5.92407379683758,7.08652044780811,8.24758247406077,
9.40860862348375,10.4193068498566,11.4300765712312,12.4416826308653,13.4533574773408,
15.5211962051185,17.5849760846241),.UNSPECIFIED.);
#486=EDGE_CURVE('E149',#32,#84,#485,.T.);
#487=ORIENTED_EDGE('',*,*,#486,.F.);
#488=EDGE_CURVE('E139',#311,#32,#485,.T.);
#489=ORIENTED_EDGE('',*,*,#488,.F.);
#490=EDGE_LOOP('',(#313,#453,#454,#487,#489));
#491=FACE_BOUND('',#490,.T.);
#492=ADVANCED_FACE('F147',(#491),#303,.T.);
#493=CARTESIAN_POINT('',(-8.66025403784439,15.,-20.));
#494=DIRECTION('',(-0.866025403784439,0.5,0.));
#495=DIRECTION('',(-0.5,-0.866025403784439,0.));
#496=AXIS2_PLACEMENT_3D('',#493,#494,#495);
#497=PLANE('',#496);
#498=DIRECTION('',(0.,0.,1.));
#499=VECTOR('',#498,1.);
#500=CARTESIAN_POINT('',(-8.66025403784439,15.,-20.));
#501=LINE('',#500,#499);
#502=CARTESIAN_POINT('',(-8.66025403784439,15.,-14.889067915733));
#503=VERTEX_POINT('',#502);
#504=CARTESIAN_POINT('',(-8.66025403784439,15.,-1.33974596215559));
#505=VERTEX_POINT('',#504);
#506=EDGE_CURVE('E133',#503,#505,#501,.T.);
#507=ORIENTED_EDGE('',*,*,#506,.F.);
#508=CARTESIAN_POINT('',(-6.393798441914,18.9256162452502,-16.0655775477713));
#509=CARTESIAN_POINT('',(-6.51440137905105,18.7167258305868,-16.8847177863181));
#510=CARTESIAN_POINT('',(-7.25260114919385,19.0516555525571,-17.1531468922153));
#511=CARTESIAN_POINT('',(-6.66407948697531,18.4574757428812,-15.9064549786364));
#512=CARTESIAN_POINT('',(-6.78065806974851,18.2555557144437,-16.7226516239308));
#513=CARTESIAN_POINT('',(-7.5133854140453,18.5871374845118,-16.9940243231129));
#514=CARTESIAN_POINT('',(-6.93516998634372,17.9879332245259,-15.7526340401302));
#515=CARTESIAN_POINT('',(-7.04811108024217,17.7923135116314,-16.5654726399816));
#516=CARTESIAN_POINT('',(-7.77457087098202,18.1216861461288,-16.8402033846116));
#517=CARTESIAN_POINT('',(-7.47918258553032,17.0456757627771,-15.4577952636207));
#518=CARTESIAN_POINT('',(-7.58441956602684,16.863399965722,-16.2640376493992));
#519=CARTESIAN_POINT('',(-8.29804362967,17.1887736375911,-16.5453646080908));
#520=CARTESIAN_POINT('',(-7.75210528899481,16.5729597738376,-15.3167818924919));
#521=CARTESIAN_POINT('',(-7.85326910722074,16.3977389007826,-16.1197341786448));
#522=CARTESIAN_POINT('',(-8.56033128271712,16.7213118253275,-16.4043512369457));
#523=CARTESIAN_POINT('',(-8.30091620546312,15.622391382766,-15.0493314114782));
#524=CARTESIAN_POINT('',(-8.39346845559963,15.4620861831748,-15.8458961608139));
#525=CARTESIAN_POINT('',(-9.08719148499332,15.7826613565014,-16.1369007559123));
#526=CARTESIAN_POINT('',(-8.57681195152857,15.1445259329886,-14.922955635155));
#527=CARTESIAN_POINT('',(-8.66485281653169,14.9920346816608,-15.716344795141));
#528=CARTESIAN_POINT('',(-9.35176898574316,15.3114652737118,-16.0105249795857));
#529=CARTESIAN_POINT('',(-9.1304880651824,14.1855307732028,-14.6880992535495));
#530=CARTESIAN_POINT('',(-9.20900326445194,14.0495384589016,-15.4755041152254));
#531=CARTESIAN_POINT('',(-9.88237158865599,14.3674236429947,-15.7756685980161));
#532=CARTESIAN_POINT('',(-9.40826825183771,13.7044013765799,-14.5796169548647));
#533=CARTESIAN_POINT('',(-9.4818400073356,13.5769713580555,-15.3641105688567));
#534=CARTESIAN_POINT('',(-10.1483965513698,13.894578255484,-15.6671862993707));
#535=CARTESIAN_POINT('',(-9.95821774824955,12.7518609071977,-14.3859363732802));
#536=CARTESIAN_POINT('',(-10.0215318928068,12.6421975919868,-15.1652022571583));
#537=CARTESIAN_POINT('',(-10.675023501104,12.9601379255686,-15.4735057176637));
#538=CARTESIAN_POINT('',(-10.2303387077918,12.2805335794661,-14.3001934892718));
#539=CARTESIAN_POINT('',(-10.2884474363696,12.1798863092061,-15.0770255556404));
#540=CARTESIAN_POINT('',(-10.9355805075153,12.4985798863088,-15.3877628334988));
#541=CARTESIAN_POINT('',(-10.7761090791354,11.3352315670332,-14.1507918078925));
#542=CARTESIAN_POINT('',(-10.8232996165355,11.2534951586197,-14.9234107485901));
#543=CARTESIAN_POINT('',(-11.4584878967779,11.5745471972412,-15.2383611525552));
#544=CARTESIAN_POINT('',(-11.0497584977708,10.861256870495,-14.087133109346));
#545=CARTESIAN_POINT('',(-11.0914098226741,10.78911465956,-14.8578604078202));
#546=CARTESIAN_POINT('',(-11.720838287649,11.1120725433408,-15.1747024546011));
#547=CARTESIAN_POINT('',(-11.5976697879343,9.91224667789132,-13.9841681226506));
#548=CARTESIAN_POINT('',(-11.6277807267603,9.860093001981,-14.7518903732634));
#549=CARTESIAN_POINT('',(-12.2468886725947,10.1876642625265,-15.0717374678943));
#550=CARTESIAN_POINT('',(-11.8719293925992,9.4372151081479,-13.9448141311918));
#551=CARTESIAN_POINT('',(-11.8962644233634,9.39506559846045,-14.7113282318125));
#552=CARTESIAN_POINT('',(-12.5105849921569,9.72573136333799,-15.0323834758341));
#553=CARTESIAN_POINT('',(-12.4210711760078,8.48607363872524,-13.8917477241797));
#554=CARTESIAN_POINT('',(-12.4334573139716,8.46462021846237,-14.6566795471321));
#555=CARTESIAN_POINT('',(-13.0397606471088,8.8021244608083,-14.9793170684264));
#556=CARTESIAN_POINT('',(-12.6959533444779,8.00996375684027,-13.8780348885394));
#557=CARTESIAN_POINT('',(-12.7024301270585,7.99874564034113,-14.6425383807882));
#558=CARTESIAN_POINT('',(-13.3052399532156,8.34045045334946,-14.9656042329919));
#559=CARTESIAN_POINT('',(-13.2480052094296,7.05378187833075,-13.8767935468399));
#560=CARTESIAN_POINT('',(-13.2423317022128,7.06360868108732,-14.6412598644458));
#561=CARTESIAN_POINT('',(-13.8399384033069,7.41415901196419,-14.9643628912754));
#562=CARTESIAN_POINT('',(-13.5251750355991,6.57370965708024,-13.8894823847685));
#563=CARTESIAN_POINT('',(-13.5135423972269,6.59385797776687,-14.6543453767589));
#564=CARTESIAN_POINT('',(-14.1091703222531,6.94954878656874,-14.9770517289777));
#565=CARTESIAN_POINT('',(-14.0789052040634,5.61462087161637,-13.9409693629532));
#566=CARTESIAN_POINT('',(-14.0552134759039,5.65565614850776,-14.7073683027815));
#567=CARTESIAN_POINT('',(-14.6487875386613,6.02174779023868,-15.028538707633));
#568=CARTESIAN_POINT('',(-14.3554655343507,5.13560432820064,-13.9797680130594));
#569=CARTESIAN_POINT('',(-14.3259452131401,5.18673502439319,-14.7473598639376));
#570=CARTESIAN_POINT('',(-14.9191728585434,5.55855704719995,-15.0673373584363));
#571=CARTESIAN_POINT('',(-14.9079850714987,4.17861241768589,-14.082083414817));
#572=CARTESIAN_POINT('',(-14.866812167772,4.2499259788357,-14.8526638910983));
#573=CARTESIAN_POINT('',(-15.4611222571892,4.63306789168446,-15.1696527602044));
#574=CARTESIAN_POINT('',(-15.183941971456,3.70064104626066,-14.1456494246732));
#575=CARTESIAN_POINT('',(-15.1371775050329,3.78163947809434,-14.9181218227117));
#576=CARTESIAN_POINT('',(-15.732687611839,4.17077311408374,-15.2332187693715));
#577=CARTESIAN_POINT('',(-15.7343081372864,2.74737888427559,-14.2952887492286));
#578=CARTESIAN_POINT('',(-15.6765186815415,2.84747315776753,-15.071984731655));
#579=CARTESIAN_POINT('',(-16.2759337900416,3.24822612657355,-15.3828580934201));
#580=CARTESIAN_POINT('',(-16.0087174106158,2.27208808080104,-14.3813619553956));
#581=CARTESIAN_POINT('',(-15.9456737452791,2.3812829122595,-15.1605045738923));
#582=CARTESIAN_POINT('',(-16.5476146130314,2.78797390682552,-15.4689312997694));
#583=CARTESIAN_POINT('',(-16.563339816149,1.31145389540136,-14.576102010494));
#584=CARTESIAN_POINT('',(-16.4899407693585,1.43858477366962,-15.3605048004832));
#585=CARTESIAN_POINT('',(-17.0981488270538,1.85686064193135,-15.6636713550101));
#586=CARTESIAN_POINT('',(-16.8435034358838,0.826196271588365,-14.6853281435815));
#587=CARTESIAN_POINT('',(-16.7651155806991,0.961968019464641,-15.4726650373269));
#588=CARTESIAN_POINT('',(-17.3769926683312,1.38605844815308,-15.7728974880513));
#589=CARTESIAN_POINT('',(-17.4019145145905,-0.141000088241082,-14.9219929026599));
#590=CARTESIAN_POINT('',(-17.3139151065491,0.0114193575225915,-15.7153621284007));
#591=CARTESIAN_POINT('',(-17.9339656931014,0.446567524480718,-16.0095622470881));
#592=CARTESIAN_POINT('',(-17.6801617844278,-0.622938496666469,-15.0494333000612));
#593=CARTESIAN_POINT('',(-17.5876125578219,-0.462638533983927,-15.8460060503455));
#594=CARTESIAN_POINT('',(-18.2120948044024,-0.0221209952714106,-16.1370026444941));
#595=CARTESIAN_POINT('',(-18.2336192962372,-1.58155502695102,-15.3192526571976));
#596=CARTESIAN_POINT('',(-18.1323881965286,-1.40621761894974,-16.1222680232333));
#597=CARTESIAN_POINT('',(-18.7662177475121,-0.955564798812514,-16.4068220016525));
#598=CARTESIAN_POINT('',(-18.5088373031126,-2.05824659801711,-15.4615684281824));
#599=CARTESIAN_POINT('',(-18.4035017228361,-1.87580002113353,-16.2679029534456));
#600=CARTESIAN_POINT('',(-19.042215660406,-1.42032832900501,-16.5491377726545));
#601=CARTESIAN_POINT('',(-19.0574092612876,-3.00840110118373,-15.7592035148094));
#602=CARTESIAN_POINT('',(-18.9443146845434,-2.81251554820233,-16.5721917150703));
#603=CARTESIAN_POINT('',(-19.5929981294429,-2.34786091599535,-16.8467728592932));
#604=CARTESIAN_POINT('',(-19.3307638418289,-3.48186512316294,-15.9145181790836));
#605=CARTESIAN_POINT('',(-19.2140077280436,-3.27963760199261,-16.7308938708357));
#606=CARTESIAN_POINT('',(-19.8677830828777,-2.81063062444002,-17.0020875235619));
#607=CARTESIAN_POINT('',(-19.6032967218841,-3.95390591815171,-16.0752036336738));
#608=CARTESIAN_POINT('',(-19.4824850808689,-3.7446540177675,-16.8945434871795));
#609=CARTESIAN_POINT('',(-20.1419494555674,-3.27257427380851,-17.1627729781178));
#610=(BOUNDED_SURFACE() B_SPLINE_SURFACE(3,2,((#508,#509,#510),(#511,#512,#513),(#514,#515,
#516),(#517,#518,#519),(#520,#521,#522),(#523,#524,#525),(#526,#527,#528),(#529,#530,#531),
(#532,#533,#534),(#535,#536,#537),(#538,#539,#540),(#541,#542,#543),(#544,#545,#546),(#547,#548,
#549),(#550,#551,#552),(#553,#554,#555),(#556,#557,#558),(#559,#560,#561),(#562,#563,#564),
(#565,#566,#567),(#568,#569,#570),(#571,#572,#573),(#574,#575,#576),(#577,#578,#579),(#580,#581,
#582),(#583,#584,#585),(#586,#587,#588),(#589,#590,#591),(#592,#593,#594),(#595,#596,#597),
(#598,#599,#600),(#601,#602,#603),(#604,#605,#606),(#607,#608,#609)),.UNSPECIFIED.,.F.,.F.,
.F.) B_SPLINE_SURFACE_WITH_KNOTS((4,2,2,2,2,2,2,2,2,2,2,2,2,2,2,2,4),(3,3),(0.,1.69054342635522,
3.38167421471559,5.07965265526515,6.77747031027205,8.42993159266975,10.0824002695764,
11.7316152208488,13.3808031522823,15.0436212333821,16.7064717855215,18.3726464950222,
20.0388131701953,21.7510843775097,23.4635222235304,25.1689606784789,26.8737914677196),(0.,1.),
.UNSPECIFIED.) GEOMETRIC_REPRESENTATION_ITEM() RATIONAL_B_SPLINE_SURFACE(((1.,0.814768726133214,
1.),(1.,0.816408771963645,1.),(1.,0.818073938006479,1.),(1.,0.821407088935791,1.),(1.,
0.823075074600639,1.),(1.,0.826371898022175,1.),(1.,0.828000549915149,1.),(1.,0.831141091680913,
1.),(1.,0.832652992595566,1.),(1.,0.835437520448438,1.),(1.,0.836715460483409,1.),(1.,
0.838994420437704,1.),(1.,0.839995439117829,1.),(1.,0.841638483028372,1.),(1.,0.842281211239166,
1.),(1.,0.843152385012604,1.),(1.,0.843380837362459,1.),(1.,0.843401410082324,1.),(1.,
0.843189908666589,1.),(1.,0.842344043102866,1.),(1.,0.841709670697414,1.),(1.,0.840075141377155,
1.),(1.,0.839074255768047,1.),(1.,0.836788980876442,1.),(1.,0.835504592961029,1.),(1.,
0.832702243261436,1.),(1.,0.831178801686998,1.),(1.,0.82801277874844,1.),(1.,0.826370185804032,
1.),(1.,0.823045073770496,1.),(1.,0.821362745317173,1.),(1.,0.818001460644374,1.),(1.,
0.816322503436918,1.),(1.,0.814669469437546,1.))) REPRESENTATION_ITEM('') SURFACE());
#611=CARTESIAN_POINT('',(-6.393798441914,18.9256162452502,-16.0655775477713));
#612=CARTESIAN_POINT('',(-6.6640794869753,18.4574757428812,-15.9064549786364));
#613=CARTESIAN_POINT('',(-6.93516998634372,17.9879332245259,-15.7526340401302));
#614=CARTESIAN_POINT('',(-7.47918258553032,17.0456757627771,-15.4577952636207));
#615=CARTESIAN_POINT('',(-7.75210528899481,16.5729597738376,-15.3167818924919));
#616=CARTESIAN_POINT('',(-8.30091620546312,15.622391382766,-15.0493314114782));
#617=CARTESIAN_POINT('',(-8.57681195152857,15.1445259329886,-14.922955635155));
#618=CARTESIAN_POINT('',(-9.1304880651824,14.1855307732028,-14.6880992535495));
#619=CARTESIAN_POINT('',(-9.40826825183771,13.7044013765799,-14.5796169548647));
#620=CARTESIAN_POINT('',(-9.95821774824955,12.7518609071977,-14.3859363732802));
#621=CARTESIAN_POINT('',(-10.2303387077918,12.2805335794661,-14.3001934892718));
#622=CARTESIAN_POINT('',(-10.7761090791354,11.3352315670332,-14.1507918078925));
#623=CARTESIAN_POINT('',(-11.0497584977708,10.861256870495,-14.087133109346));
#624=CARTESIAN_POINT('',(-11.5976697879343,9.91224667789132,-13.9841681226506));
#625=CARTESIAN_POINT('',(-11.8719293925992,9.4372151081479,-13.9448141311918));
#626=CARTESIAN_POINT('',(-12.4210711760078,8.48607363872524,-13.8917477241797));
#627=CARTESIAN_POINT('',(-12.6959533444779,8.00996375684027,-13.8780348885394));
#628=CARTESIAN_POINT('',(-13.2480052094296,7.05378187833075,-13.8767935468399));
#629=CARTESIAN_POINT('',(-13.5251750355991,6.57370965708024,-13.8894823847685));
#630=CARTESIAN_POINT('',(-14.0789052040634,5.61462087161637,-13.9409693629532));
#631=CARTESIAN_POINT('',(-14.3554655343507,5.13560432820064,-13.9797680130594));
#632=CARTESIAN_POINT('',(-14.9079850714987,4.17861241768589,-14.082083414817));
#633=CARTESIAN_POINT('',(-15.183941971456,3.70064104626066,-14.1456494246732));
#634=CARTESIAN_POINT('',(-15.7343081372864,2.74737888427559,-14.2952887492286));
#635=CARTESIAN_POINT('',(-16.0087174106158,2.27208808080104,-14.3813619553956));
#636=CARTESIAN_POINT('',(-16.563339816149,1.31145389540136,-14.576102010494));
#637=CARTESIAN_POINT('',(-16.8435034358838,0.826196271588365,-14.6853281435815));
#638=CARTESIAN_POINT('',(-17.4019145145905,-0.141000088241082,-14.9219929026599));
#639=CARTESIAN_POINT('',(-17.6801617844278,-0.622938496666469,-15.0494333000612));
#640=CARTESIAN_POINT('',(-18.2336192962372,-1.58155502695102,-15.3192526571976));
#641=CARTESIAN_POINT('',(-18.5088373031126,-2.05824659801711,-15.4615684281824));
#642=CARTESIAN_POINT('',(-19.0574092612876,-3.00840110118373,-15.7592035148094));
#643=CARTESIAN_POINT('',(-19.3307638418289,-3.48186512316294,-15.9145181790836));
#644=CARTESIAN_POINT('',(-19.6032967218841,-3.95390591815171,-16.0752036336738));
#645=B_SPLINE_CURVE_WITH_KNOTS('',3,(#611,#612,#613,#614,#615,#616,#617,#618,#619,#620,#621,
#622,#623,#624,#625,#626,#627,#628,#629,#630,#631,#632,#633,#634,#635,#636,#637,#638,#639,#640,
#641,#642,#643,#644),.UNSPECIFIED.,.F.,.F.,(4,2,2,2,2,2,2,2,2,2,2,2,2,2,2,2,4),(0.,
1.69054342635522,3.38167421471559,5.07965265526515,6.77747031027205,8.42993159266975,
10.0824002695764,11.7316152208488,13.3808031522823,15.0436212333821,16.7064717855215,
18.3726464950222,20.0388131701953,21.7510843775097,23.4635222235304,25.1689606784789,
26.8737914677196),.UNSPECIFIED.);
#646=EDGE_CURVE('E60',#503,#309,#645,.T.);
#647=ORIENTED_EDGE('',*,*,#646,.T.);
#648=ORIENTED_EDGE('',*,*,#312,.T.);
#649=CARTESIAN_POINT('',(-8.66013856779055,15.0002,-1.33981262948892));
#650=CARTESIAN_POINT('',(-8.85048754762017,14.6705058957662,-1.22992178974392));
#651=CARTESIAN_POINT('',(-9.04157899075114,14.3395258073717,-1.1250175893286));
#652=CARTESIAN_POINT('',(-9.425294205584,13.674911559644,-0.926568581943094));
#653=CARTESIAN_POINT('',(-9.61791845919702,13.3412765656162,-0.833027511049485));
#654=CARTESIAN_POINT('',(-10.0050715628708,12.6707077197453,-0.658562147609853));
#655=CARTESIAN_POINT('',(-10.199603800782,12.333767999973,-0.577667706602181));
#656=CARTESIAN_POINT('',(-10.5900200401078,11.6575472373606,-0.43023264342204));
#657=CARTESIAN_POINT('',(-10.7859039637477,11.3182663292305,-0.363691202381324));
#658=CARTESIAN_POINT('',(-11.1740042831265,10.6460568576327,-0.247792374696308));
#659=CARTESIAN_POINT('',(-11.3661918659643,10.3131781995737,-0.198051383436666));
#660=CARTESIAN_POINT('',(-11.7514476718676,9.64589556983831,-0.114646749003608));
#661=CARTESIAN_POINT('',(-11.9445159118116,9.31149156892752,-0.080983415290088));
#662=CARTESIAN_POINT('',(-12.3309767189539,8.64212181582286,-0.0305840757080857));
#663=CARTESIAN_POINT('',(-12.5243686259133,8.30715720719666,-0.0138279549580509));
#664=CARTESIAN_POINT('',(-12.9113309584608,7.63691878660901,0.00239660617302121));
#665=CARTESIAN_POINT('',(-13.1049013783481,7.30164498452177,0.00186558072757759));
#666=CARTESIAN_POINT('',(-13.4667798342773,6.67485311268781,-0.0152766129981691));
#667=CARTESIAN_POINT('',(-13.6351136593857,6.38329037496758,-0.0297968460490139));
#668=CARTESIAN_POINT('',(-13.9713941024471,5.80083556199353,-0.0716371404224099));
#669=CARTESIAN_POINT('',(-14.1393406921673,5.50994353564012,-0.0989581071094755));
#670=CARTESIAN_POINT('',(-14.4747554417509,4.92898814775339,-0.165923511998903));
#671=CARTESIAN_POINT('',(-14.6422230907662,4.63892567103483,-0.20557812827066));
#672=CARTESIAN_POINT('',(-14.9763732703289,4.06016058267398,-0.2965151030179));
#673=CARTESIAN_POINT('',(-15.1430557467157,3.77145806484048,-0.347798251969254));
#674=CARTESIAN_POINT('',(-15.6490296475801,2.8950855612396,-0.520386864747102));
#675=CARTESIAN_POINT('',(-15.9868558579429,2.30995340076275,-0.658901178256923));
#676=CARTESIAN_POINT('',(-16.6574708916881,1.14841408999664,-0.973271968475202));
#677=CARTESIAN_POINT('',(-16.9902683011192,0.571992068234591,-1.14905461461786));
#678=CARTESIAN_POINT('',(-17.3206235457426,-0.000199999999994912,-1.33981262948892));
#679=B_SPLINE_CURVE_WITH_KNOTS('',3,(#649,#650,#651,#652,#653,#654,#655,#656,#657,#658,#659,
#660,#661,#662,#663,#664,#665,#666,#667,#668,#669,#670,#671,#672,#673,#674,#675,#676,#677,#678),
.UNSPECIFIED.,.F.,.F.,(4,2,2,2,2,2,2,2,2,2,2,2,2,2,4),(0.,1.18875411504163,2.37789802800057,
3.56980778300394,4.76164951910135,5.92407379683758,7.0865204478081,8.24758247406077,
9.40860862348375,10.4193068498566,11.4300765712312,12.4416826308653,13.4533574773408,
15.5211962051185,17.5849760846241),.UNSPECIFIED.);
#680=EDGE_CURVE('E129',#30,#311,#679,.T.);
#681=ORIENTED_EDGE('',*,*,#680,.F.);
#682=EDGE_CURVE('E143',#505,#30,#679,.T.);
#683=ORIENTED_EDGE('',*,*,#682,.F.);
#684=EDGE_LOOP('',(#507,#647,#648,#681,#683));
#685=FACE_BOUND('',#684,.T.);
#686=ADVANCED_FACE('F127',(#685),#497,.T.);
#687=CARTESIAN_POINT('',(8.66025403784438,15.,-20.));
#688=DIRECTION('',(0.,1.,0.));
#689=DIRECTION('',(-1.,0.,0.));
#690=AXIS2_PLACEMENT_3D('',#687,#688,#689);
#691=PLANE('',#690);
#692=DIRECTION('',(0.,0.,1.));
#693=VECTOR('',#692,1.);
#694=CARTESIAN_POINT('',(8.66025403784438,15.,-20.));
#695=LINE('',#694,#693);
#696=CARTESIAN_POINT('',(8.66025403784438,15.,-14.889067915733));
#697=VERTEX_POINT('',#696);
#698=CARTESIAN_POINT('',(8.66025403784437,15.,-1.3397459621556));
#699=VERTEX_POINT('',#698);
#700=EDGE_CURVE('E696',#697,#699,#695,.T.);
#701=ORIENTED_EDGE('',*,*,#700,.F.);
#702=CARTESIAN_POINT('',(13.2603230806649,15.,-16.0853831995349));
#703=CARTESIAN_POINT('',(13.018260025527,15.,-16.9049338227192));
#704=CARTESIAN_POINT('',(12.9390978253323,15.8075624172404,-17.1729525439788));
#705=CARTESIAN_POINT('',(12.7153895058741,15.,-15.9244857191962));
#706=CARTESIAN_POINT('',(12.4814189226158,15.,-16.7410731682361));
#707=CARTESIAN_POINT('',(12.4020652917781,15.8011041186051,-17.0120550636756));
#708=CARTESIAN_POINT('',(12.168816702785,15.,-15.7689378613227));
#709=CARTESIAN_POINT('',(11.9421518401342,15.,-16.5821383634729));
#710=CARTESIAN_POINT('',(11.8640100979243,15.7945220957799,-16.8565072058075));
#711=CARTESIAN_POINT('',(11.0719531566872,15.,-15.4707866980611));
#712=CARTESIAN_POINT('',(10.8607685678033,15.,-16.2773321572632));
#713=CARTESIAN_POINT('',(10.7855712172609,15.781300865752,-16.5583560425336));
#714=CARTESIAN_POINT('',(10.5216611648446,15.,-15.3281879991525));
#715=CARTESIAN_POINT('',(10.3186663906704,15.,-16.1314129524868));
#716=CARTESIAN_POINT('',(10.2451867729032,15.7746616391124,-16.4157573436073));
#717=CARTESIAN_POINT('',(9.41502609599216,15.,-15.057740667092));
#718=CARTESIAN_POINT('',(9.22935461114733,15.,-15.8545172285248));
#719=CARTESIAN_POINT('',(9.15995125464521,15.761493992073,-16.1453100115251));
#720=CARTESIAN_POINT('',(8.85866741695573,15.,-14.9299553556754));
#721=CARTESIAN_POINT('',(8.68207595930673,15.,-15.723524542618));
#722=CARTESIAN_POINT('',(8.61509095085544,15.754966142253,-16.0175247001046));
#723=CARTESIAN_POINT('',(7.74211689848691,15.,-14.6925374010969));
#724=CARTESIAN_POINT('',(7.58470726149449,15.,-15.4800629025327));
#725=CARTESIAN_POINT('',(7.52318087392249,15.7423412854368,-15.780106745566));
#726=CARTESIAN_POINT('',(7.18192543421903,15.,-14.5829030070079));
#727=CARTESIAN_POINT('',(7.03447405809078,15.,-15.3674874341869));
#728=CARTESIAN_POINT('',(6.97613131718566,15.7362442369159,-15.6704723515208));
#729=CARTESIAN_POINT('',(6.07298067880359,15.,-14.3872994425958));
#730=CARTESIAN_POINT('',(5.94619978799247,15.,-15.1666062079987));
#731=CARTESIAN_POINT('',(5.89472457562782,15.7249920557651,-15.4748687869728));
#732=CARTESIAN_POINT('',(5.52432681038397,15.,-14.3007713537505));
#733=CARTESIAN_POINT('',(5.40803627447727,15.,-15.0776214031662));
#734=CARTESIAN_POINT('',(5.36042338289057,15.7198159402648,-15.3883406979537));
#735=CARTESIAN_POINT('',(4.42391178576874,15.,-14.1501605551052));
#736=CARTESIAN_POINT('',(4.32963529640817,15.,-14.9227634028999));
#737=CARTESIAN_POINT('',(4.29010262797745,15.7105764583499,-15.2377298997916));
#738=CARTESIAN_POINT('',(3.87215061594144,15.,-14.0860779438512));
#739=CARTESIAN_POINT('',(3.78904213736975,15.,-14.8567752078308));
#740=CARTESIAN_POINT('',(3.75408305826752,15.7065130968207,-15.1736472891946));
#741=CARTESIAN_POINT('',(2.76740362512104,15.,-13.9826801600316));
#742=CARTESIAN_POINT('',(2.70757202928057,15.,-14.7503590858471));
#743=CARTESIAN_POINT('',(2.68185101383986,15.699851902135,-15.0702495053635));
#744=CARTESIAN_POINT('',(2.21442248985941,15.,-13.9433154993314));
#745=CARTESIAN_POINT('',(2.16623735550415,15.,-14.7097848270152));
#746=CARTESIAN_POINT('',(2.14564108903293,15.6972511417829,-15.0308848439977));
#747=CARTESIAN_POINT('',(1.10721428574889,15.,-13.8906631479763));
#748=CARTESIAN_POINT('',(1.08312994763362,15.,-14.6555622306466));
#749=CARTESIAN_POINT('',(1.07255384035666,15.6937535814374,-14.978232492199));
#750=CARTESIAN_POINT('',(0.552987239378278,15.,-13.8773749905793));
#751=CARTESIAN_POINT('',(0.540816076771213,15.,-14.6418586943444));
#752=CARTESIAN_POINT('',(0.535676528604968,15.6928567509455,-14.9649443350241));
#753=CARTESIAN_POINT('',(-0.556564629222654,15.,-13.8774146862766));
#754=CARTESIAN_POINT('',(-0.544315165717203,15.,-14.6418996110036));
#755=CARTESIAN_POINT('',(-0.539141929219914,15.6928594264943,-14.9649840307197));
#756=CARTESIAN_POINT('',(-1.11188945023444,15.,-13.8907953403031));
#757=CARTESIAN_POINT('',(-1.08770450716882,15.,-14.6556985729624));
#758=CARTESIAN_POINT('',(-1.07708307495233,15.6937624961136,-14.9783646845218));
#759=CARTESIAN_POINT('',(-2.22128430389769,15.,-13.9437329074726));
#760=CARTESIAN_POINT('',(-2.17295277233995,15.,-14.7102147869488));
#761=CARTESIAN_POINT('',(-2.1522933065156,15.697278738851,-15.031302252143));
#762=CARTESIAN_POINT('',(-2.77535431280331,15.,-13.9832903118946));
#763=CARTESIAN_POINT('',(-2.71535587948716,15.,-14.7509877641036));
#764=CARTESIAN_POINT('',(-2.68956237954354,15.6998919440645,-15.0708596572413));
#765=CARTESIAN_POINT('',(-3.88227097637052,15.,-14.0871616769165));
#766=CARTESIAN_POINT('',(-3.79895537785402,15.,-14.8578908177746));
#767=CARTESIAN_POINT('',(-3.76391096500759,15.7065821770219,-15.1747310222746));
#768=CARTESIAN_POINT('',(-4.43511289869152,15.,-14.1515254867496));
#769=CARTESIAN_POINT('',(-4.34061167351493,15.,-14.9241683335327));
#770=CARTESIAN_POINT('',(-4.30098790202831,15.7106621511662,-15.23909483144));
#771=CARTESIAN_POINT('',(-5.53767239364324,15.,-14.3027699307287));
#772=CARTESIAN_POINT('',(-5.42112418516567,15.,-15.0796765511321));
#773=CARTESIAN_POINT('',(-5.3734137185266,15.7199365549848,-15.390339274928));
#774=CARTESIAN_POINT('',(-6.08738998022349,15.,-14.3896504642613));
#775=CARTESIAN_POINT('',(-5.96033735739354,15.,-15.169022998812));
#776=CARTESIAN_POINT('',(-5.90876260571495,15.7251309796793,-15.4772198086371));
#777=CARTESIAN_POINT('',(-7.19850774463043,15.,-14.5860294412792));
#778=CARTESIAN_POINT('',(-7.05075919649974,15.,-15.3706980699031));
#779=CARTESIAN_POINT('',(-6.9923160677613,15.736420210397,-15.6735987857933));
#780=CARTESIAN_POINT('',(-7.75980780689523,15.,-14.696089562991));
#781=CARTESIAN_POINT('',(-7.60208979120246,15.,-15.4837090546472));
#782=CARTESIAN_POINT('',(-7.54046424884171,15.7425360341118,-15.7836589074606));
#783=CARTESIAN_POINT('',(-8.87855955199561,15.,-14.9344018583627));
#784=CARTESIAN_POINT('',(-8.70164124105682,15.,-15.7280836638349));
#785=CARTESIAN_POINT('',(-8.63456183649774,15.7551965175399,-16.0219712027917));
#786=CARTESIAN_POINT('',(-9.43601085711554,15.,-15.0626557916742));
#787=CARTESIAN_POINT('',(-9.25000492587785,15.,-15.8595541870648));
#788=CARTESIAN_POINT('',(-9.18051102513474,15.7617412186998,-16.1502251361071));
#789=CARTESIAN_POINT('',(-10.5448022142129,15.,-15.3340647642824));
#790=CARTESIAN_POINT('',(-10.3414617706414,15.,-16.1374286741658));
#791=CARTESIAN_POINT('',(-10.2679002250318,15.7749396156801,-16.4216341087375));
#792=CARTESIAN_POINT('',(-11.0961579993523,15.,-15.4771560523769));
#793=CARTESIAN_POINT('',(-10.8846233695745,15.,-16.28384850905));
#794=CARTESIAN_POINT('',(-10.8093495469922,15.7815927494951,-16.5647253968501));
#795=CARTESIAN_POINT('',(-12.1951379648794,15.,-15.7763110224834));
#796=CARTESIAN_POINT('',(-11.9681178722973,15.,-16.5896736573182));
#797=CARTESIAN_POINT('',(-11.8899101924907,15.7948389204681,-16.8638803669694));
#798=CARTESIAN_POINT('',(-12.7427634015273,15.,-15.9323700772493));
#799=CARTESIAN_POINT('',(-12.508435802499,15.,-16.7491266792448));
#800=CARTESIAN_POINT('',(-12.4290222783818,15.801431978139,-17.0199394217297));
#801=CARTESIAN_POINT('',(-13.2887459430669,15.,-16.0937835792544));
#802=CARTESIAN_POINT('',(-13.0463212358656,15.,-16.9135078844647));
#803=CARTESIAN_POINT('',(-12.9671089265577,15.8078998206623,-17.1813529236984));
#804=(BOUNDED_SURFACE() B_SPLINE_SURFACE(3,2,((#702,#703,#704),(#705,#706,#707),(#708,#709,
#710),(#711,#712,#713),(#714,#715,#716),(#717,#718,#719),(#720,#721,#722),(#723,#724,#725),
(#726,#727,#728),(#729,#730,#731),(#732,#733,#734),(#735,#736,#737),(#738,#739,#740),(#741,#742,
#743),(#744,#745,#746),(#747,#748,#749),(#750,#751,#752),(#753,#754,#755),(#756,#757,#758),
(#759,#760,#761),(#762,#763,#764),(#765,#766,#767),(#768,#769,#770),(#771,#772,#773),(#774,#775,
#776),(#777,#778,#779),(#780,#781,#782),(#783,#784,#785),(#786,#787,#788),(#789,#790,#791),
(#792,#793,#794),(#795,#796,#797),(#798,#799,#800),(#801,#802,#803)),.UNSPECIFIED.,.F.,.F.,
.F.) B_SPLINE_SURFACE_WITH_KNOTS((4,2,2,2,2,2,2,2,2,2,2,2,2,2,2,2,4),(3,3),(0.,1.70463006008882,
3.40986416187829,5.12213784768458,6.83424626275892,8.50013923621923,10.1660395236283,
11.8285937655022,13.4911182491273,15.1569375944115,16.8227882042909,18.4920039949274,
20.1612123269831,21.8768288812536,23.5926114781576,25.3013055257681,27.0093924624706),(0.,1.),
.UNSPECIFIED.) GEOMETRIC_REPRESENTATION_ITEM() RATIONAL_B_SPLINE_SURFACE(((1.,0.814564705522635,
1.),(1.,0.816216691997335,1.),(1.,0.817894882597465,1.),(1.,0.821255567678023,1.),(1.,
0.822938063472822,1.),(1.,0.826264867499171,1.),(1.,0.827908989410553,1.),(1.,0.83107980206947,
1.),(1.,0.832606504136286,1.),(1.,0.835417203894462,1.),(1.,0.836706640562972,1.),(1.,
0.839004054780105,1.),(1.,0.840012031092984,1.),(1.,0.841662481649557,1.),(1.,0.842305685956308,
1.),(1.,0.843170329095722,1.),(1.,0.843391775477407,1.),(1.,0.843391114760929,1.),(1.,
0.84316812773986,1.),(1.,0.842298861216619,1.),(1.,0.841652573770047,1.),(1.,0.839994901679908,
1.),(1.,0.838982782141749,1.),(1.,0.836676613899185,1.),(1.,0.835382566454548,1.),(1.,
0.832562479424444,1.),(1.,0.83103099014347,1.),(1.,0.827851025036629,1.),(1.,0.826202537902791,
1.),(1.,0.822867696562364,1.),(1.,0.821181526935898,1.),(1.,0.817814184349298,1.),(1.,
0.816133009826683,1.),(1.,0.814478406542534,1.))) REPRESENTATION_ITEM('') SURFACE());
#805=CARTESIAN_POINT('',(13.2603230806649,15.,-16.0853831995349));
#806=CARTESIAN_POINT('',(12.7153895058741,15.,-15.9244857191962));
#807=CARTESIAN_POINT('',(12.168816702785,15.,-15.7689378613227));
#808=CARTESIAN_POINT('',(11.0719531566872,15.,-15.4707866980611));
#809=CARTESIAN_POINT('',(10.5216611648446,15.,-15.3281879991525));
#810=CARTESIAN_POINT('',(9.41502609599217,15.,-15.057740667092));
#811=CARTESIAN_POINT('',(8.85866741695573,15.,-14.9299553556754));
#812=CARTESIAN_POINT('',(7.74211689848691,15.,-14.6925374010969));
#813=CARTESIAN_POINT('',(7.18192543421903,15.,-14.5829030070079));
#814=CARTESIAN_POINT('',(6.07298067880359,15.,-14.3872994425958));
#815=CARTESIAN_POINT('',(5.52432681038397,15.,-14.3007713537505));
#816=CARTESIAN_POINT('',(4.42391178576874,15.,-14.1501605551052));
#817=CARTESIAN_POINT('',(3.87215061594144,15.,-14.0860779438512));
#818=CARTESIAN_POINT('',(2.76740362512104,15.,-13.9826801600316));
#819=CARTESIAN_POINT('',(2.21442248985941,15.,-13.9433154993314));
#820=CARTESIAN_POINT('',(1.10721428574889,15.,-13.8906631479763));
#821=CARTESIAN_POINT('',(0.552987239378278,15.,-13.8773749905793));
#822=CARTESIAN_POINT('',(-0.556564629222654,15.,-13.8774146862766));
#823=CARTESIAN_POINT('',(-1.11188945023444,15.,-13.8907953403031));
#824=CARTESIAN_POINT('',(-2.22128430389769,15.,-13.9437329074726));
#825=CARTESIAN_POINT('',(-2.77535431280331,15.,-13.9832903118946));
#826=CARTESIAN_POINT('',(-3.88227097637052,15.,-14.0871616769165));
#827=CARTESIAN_POINT('',(-4.43511289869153,15.,-14.1515254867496));
#828=CARTESIAN_POINT('',(-5.53767239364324,15.,-14.3027699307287));
#829=CARTESIAN_POINT('',(-6.08738998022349,15.,-14.3896504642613));
#830=CARTESIAN_POINT('',(-7.19850774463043,15.,-14.5860294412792));
#831=CARTESIAN_POINT('',(-7.75980780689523,15.,-14.696089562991));
#832=CARTESIAN_POINT('',(-8.87855955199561,15.,-14.9344018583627));
#833=CARTESIAN_POINT('',(-9.43601085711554,15.,-15.0626557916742));
#834=CARTESIAN_POINT('',(-10.5448022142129,15.,-15.3340647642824));
#835=CARTESIAN_POINT('',(-11.0961579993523,15.,-15.4771560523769));
#836=CARTESIAN_POINT('',(-12.1951379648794,15.,-15.7763110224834));
#837=CARTESIAN_POINT('',(-12.7427634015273,15.,-15.9323700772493));
#838=CARTESIAN_POINT('',(-13.2887459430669,15.,-16.0937835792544));
#839=B_SPLINE_CURVE_WITH_KNOTS('',3,(#805,#806,#807,#808,#809,#810,#811,#812,#813,#814,#815,
#816,#817,#818,#819,#820,#821,#822,#823,#824,#825,#826,#827,#828,#829,#830,#831,#832,#833,#834,
#835,#836,#837,#838),.UNSPECIFIED.,.F.,.F.,(4,2,2,2,2,2,2,2,2,2,2,2,2,2,2,2,4),(0.,
1.70463006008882,3.40986416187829,5.12213784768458,6.83424626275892,8.50013923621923,
10.1660395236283,11.8285937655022,13.4911182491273,15.1569375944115,16.8227882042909,
18.4920039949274,20.1612123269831,21.8768288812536,23.5926114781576,25.3013055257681,
27.0093924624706),.UNSPECIFIED.);
#840=EDGE_CURVE('E426',#697,#503,#839,.T.);
#841=ORIENTED_EDGE('',*,*,#840,.T.);
#842=ORIENTED_EDGE('',*,*,#506,.T.);
#843=CARTESIAN_POINT('',(-22.9682699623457,15.,-7.17790057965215));
#844=CARTESIAN_POINT('',(-22.6389897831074,15.,-7.01873142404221));
#845=CARTESIAN_POINT('',(-22.3093116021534,15.,-6.86038603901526));
#846=CARTESIAN_POINT('',(-21.6490751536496,15.,-6.54553189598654));
#847=CARTESIAN_POINT('',(-21.3185168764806,15.,-6.3890231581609));
#848=CARTESIAN_POINT('',(-20.3252989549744,15.,-5.92249019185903));
#849=CARTESIAN_POINT('',(-19.6612032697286,15.,-5.61551110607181));
#850=CARTESIAN_POINT('',(-18.3246226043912,15.,-5.00989859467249));
#851=CARTESIAN_POINT('',(-17.6521113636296,15.,-4.71132298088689));
#852=CARTESIAN_POINT('',(-16.3015621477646,15.,-4.126991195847));
#853=CARTESIAN_POINT('',(-15.6235244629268,15.,-3.84123435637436));
#854=CARTESIAN_POINT('',(-14.2524269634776,15.,-3.28256457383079));
#855=CARTESIAN_POINT('',(-13.5592849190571,15.,-3.00985238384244));
#856=CARTESIAN_POINT('',(-12.1648203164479,15.,-2.485785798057));
#857=CARTESIAN_POINT('',(-11.4634968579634,15.,-2.23443377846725));
#858=CARTESIAN_POINT('',(-10.0530172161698,15.,-1.75984469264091));
#859=CARTESIAN_POINT('',(-9.34388131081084,15.,-1.53654785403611));
#860=CARTESIAN_POINT('',(-7.91545988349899,15.,-1.12531011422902));
#861=CARTESIAN_POINT('',(-7.19617764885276,15.,-0.937358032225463));
#862=CARTESIAN_POINT('',(-6.10950776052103,15.,-0.688818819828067));
#863=CARTESIAN_POINT('',(-5.74591626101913,15.,-0.611524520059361));
#864=CARTESIAN_POINT('',(-5.01631310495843,15.,-0.469286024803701));
#865=CARTESIAN_POINT('',(-4.65030150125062,15.,-0.404341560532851));
#866=CARTESIAN_POINT('',(-3.91609659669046,15.,-0.28795299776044));
#867=CARTESIAN_POINT('',(-3.54790312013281,15.,-0.236510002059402));
#868=CARTESIAN_POINT('',(-2.80977894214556,15.,-0.148161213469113));
#869=CARTESIAN_POINT('',(-2.43984831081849,15.,-0.111254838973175));
#870=CARTESIAN_POINT('',(-1.70111543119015,15.,-0.0529692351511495));
#871=CARTESIAN_POINT('',(-1.3323208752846,15.,-0.0314931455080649));
#872=CARTESIAN_POINT('',(-0.594154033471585,15.,-0.00418216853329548));
#873=CARTESIAN_POINT('',(-0.224781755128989,15.,0.00165292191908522));
#874=CARTESIAN_POINT('',(0.513772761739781,15.,-0.00245653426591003));
#875=CARTESIAN_POINT('',(0.882955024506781,15.,-0.0123966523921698));
#876=CARTESIAN_POINT('',(1.62057875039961,15.,-0.0478095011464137));
#877=CARTESIAN_POINT('',(1.98902017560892,15.,-0.0732830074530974));
#878=CARTESIAN_POINT('',(2.88200878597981,15.,-0.153315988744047));
#879=CARTESIAN_POINT('',(3.40586988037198,15.,-0.215658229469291));
#880=CARTESIAN_POINT('',(4.44957771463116,15.,-0.368284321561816));
#881=CARTESIAN_POINT('',(4.9694233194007,15.,-0.458575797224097));
#882=CARTESIAN_POINT('',(6.00467140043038,15.,-0.663898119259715));
#883=CARTESIAN_POINT('',(6.52006919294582,15.,-0.778952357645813));
#884=CARTESIAN_POINT('',(7.54556200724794,15.,-1.03028935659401));
#885=CARTESIAN_POINT('',(8.0556575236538,15.,-1.16657011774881));
#886=CARTESIAN_POINT('',(9.08310964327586,15.,-1.46066370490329));
#887=CARTESIAN_POINT('',(9.60033774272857,15.,-1.6189224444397));
#888=CARTESIAN_POINT('',(10.6293258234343,15.,-1.95107200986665));
#889=CARTESIAN_POINT('',(11.1410893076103,15.,-2.12495205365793));
#890=CARTESIAN_POINT('',(12.1570993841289,15.,-2.48477464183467));
#891=CARTESIAN_POINT('',(12.6613720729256,15.,-2.67064378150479));
#892=CARTESIAN_POINT('',(13.4147912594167,15.,-2.95756327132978));
#893=CARTESIAN_POINT('',(13.6654863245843,15.,-3.05457748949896));
#894=CARTESIAN_POINT('',(14.1659013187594,15.,-3.25107322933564));
#895=CARTESIAN_POINT('',(14.4156212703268,15.,-3.35055469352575));
#896=CARTESIAN_POINT('',(14.6648887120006,15.,-3.45115877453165));
#897=B_SPLINE_CURVE_WITH_KNOTS('',3,(#843,#844,#845,#846,#847,#848,#849,#850,#851,#852,#853,
#854,#855,#856,#857,#858,#859,#860,#861,#862,#863,#864,#865,#866,#867,#868,#869,#870,#871,#872,
#873,#874,#875,#876,#877,#878,#879,#880,#881,#882,#883,#884,#885,#886,#887,#888,#889,#890,#891,
#892,#893,#894,#895,#896),.UNSPECIFIED.,.F.,.F.,(4,2,2,2,2,2,2,2,2,2,2,2,2,2,2,2,2,2,2,2,2,2,2,
2,2,2,4),(0.,1.09719534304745,2.19440272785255,4.38917437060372,6.59650580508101,
8.8037220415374,11.0380360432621,13.2725982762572,15.502315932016,17.7313270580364,
18.8463006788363,19.9612500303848,21.0762904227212,22.1912861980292,23.2992201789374,
24.407139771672,25.5147483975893,26.6224123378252,28.2042036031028,29.7864267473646,
31.3701511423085,32.9537264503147,34.5761185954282,36.1973994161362,37.8095545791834,
38.6159794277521,39.4223855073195),.UNSPECIFIED.);
#898=EDGE_CURVE('E144',#48,#505,#897,.F.);
#899=ORIENTED_EDGE('',*,*,#898,.F.);
#900=EDGE_CURVE('E153',#699,#48,#897,.F.);
#901=ORIENTED_EDGE('',*,*,#900,.F.);
#902=EDGE_LOOP('',(#701,#841,#842,#899,#901));
#903=FACE_BOUND('',#902,.T.);
#904=ADVANCED_FACE('F278',(#903),#691,.T.);
#905=CARTESIAN_POINT('',(17.3205080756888,0.,-20.));
#906=DIRECTION('',(0.866025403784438,0.5,0.));
#907=DIRECTION('',(-0.5,0.866025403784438,0.));
#908=AXIS2_PLACEMENT_3D('',#905,#906,#907);
#909=PLANE('',#908);
#910=DIRECTION('',(0.,0.,1.));
#911=VECTOR('',#910,1.);
#912=CARTESIAN_POINT('',(17.3205080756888,0.,-20.));
#913=LINE('',#912,#911);
#914=CARTESIAN_POINT('',(17.3205080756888,0.,-14.889067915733));
#915=VERTEX_POINT('',#914);
#916=CARTESIAN_POINT('',(17.3205080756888,0.,-1.3397459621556));
#917=VERTEX_POINT('',#916);
#918=EDGE_CURVE('E692',#915,#917,#913,.T.);
#919=ORIENTED_EDGE('',*,*,#918,.F.);
#920=CARTESIAN_POINT('',(19.5869636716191,-3.9256162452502,-16.0655775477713));
#921=CARTESIAN_POINT('',(19.4663607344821,-3.71672583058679,-16.8847177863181));
#922=CARTESIAN_POINT('',(20.1255182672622,-3.24489093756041,-17.1531468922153));
#923=CARTESIAN_POINT('',(19.3166826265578,-3.4574757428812,-15.9064549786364));
#924=CARTESIAN_POINT('',(19.2001040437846,-3.25555571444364,-16.7226516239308));
#925=CARTESIAN_POINT('',(19.8536259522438,-2.78678610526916,-16.9940243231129));
#926=CARTESIAN_POINT('',(19.0455921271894,-2.9879332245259,-15.7526340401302));
#927=CARTESIAN_POINT('',(18.932651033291,-2.79231351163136,-16.5654726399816));
#928=CARTESIAN_POINT('',(19.5811259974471,-2.32786719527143,-16.8402033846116));
#929=CARTESIAN_POINT('',(18.5015795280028,-2.0456757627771,-15.4577952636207));
#930=CARTESIAN_POINT('',(18.3963425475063,-1.86339996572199,-16.2640376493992));
#931=CARTESIAN_POINT('',(19.0349364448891,-1.40807023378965,-16.5453646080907));
#932=CARTESIAN_POINT('',(18.2286568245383,-1.57295977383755,-15.3167818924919));
#933=CARTESIAN_POINT('',(18.1274930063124,-1.39773890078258,-16.1197341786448));
#934=CARTESIAN_POINT('',(18.7612464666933,-0.947191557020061,-16.4043512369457));
#935=CARTESIAN_POINT('',(17.67984590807,-0.622391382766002,-15.0493314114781));
#936=CARTESIAN_POINT('',(17.5872936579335,-0.462086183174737,-15.8458961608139));
#937=CARTESIAN_POINT('',(18.2117814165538,-0.0215920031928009,-16.1369007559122));
#938=CARTESIAN_POINT('',(17.4039501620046,-0.144525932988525,-14.922955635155));
#939=CARTESIAN_POINT('',(17.3159092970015,0.00796531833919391,-15.716344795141));
#940=CARTESIAN_POINT('',(17.9360023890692,0.443136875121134,-16.0105249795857));
#941=CARTESIAN_POINT('',(16.8502740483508,0.814469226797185,-14.6880992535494));
#942=CARTESIAN_POINT('',(16.7717588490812,0.950461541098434,-15.4755041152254));
#943=CARTESIAN_POINT('',(17.3837396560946,1.37467302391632,-15.7756685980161));
#944=CARTESIAN_POINT('',(16.5724938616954,1.29559862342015,-14.5796169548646));
#945=CARTESIAN_POINT('',(16.4989221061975,1.42302864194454,-15.3641105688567));
#946=CARTESIAN_POINT('',(17.1072560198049,1.8414800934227,-15.6671862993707));
#947=CARTESIAN_POINT('',(16.0225443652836,2.24813909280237,-14.3859363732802));
#948=CARTESIAN_POINT('',(15.9592302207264,2.3578024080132,-15.1652022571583));
#949=CARTESIAN_POINT('',(16.5613204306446,2.76477257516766,-15.4735057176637));
#950=CARTESIAN_POINT('',(15.7504234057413,2.71946642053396,-14.3001934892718));
#951=CARTESIAN_POINT('',(15.6923146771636,2.82011369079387,-15.0770255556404));
#952=CARTESIAN_POINT('',(16.2918779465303,3.2212005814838,-15.3877628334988));
#953=CARTESIAN_POINT('',(15.2046530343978,3.66476843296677,-14.1507918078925));
#954=CARTESIAN_POINT('',(15.1574624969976,3.74650484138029,-14.9234107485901));
#955=CARTESIAN_POINT('',(15.7530958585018,4.13606800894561,-15.2383611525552));
#956=CARTESIAN_POINT('',(14.9310036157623,4.13874312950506,-14.087133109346));
#957=CARTESIAN_POINT('',(14.8893522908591,4.21088534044,-14.8578604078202));
#958=CARTESIAN_POINT('',(15.4837562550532,4.59450743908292,-15.1747024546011));
#959=CARTESIAN_POINT('',(14.3830923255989,5.08775332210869,-13.9841681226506));
#960=CARTESIAN_POINT('',(14.3529813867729,5.13990699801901,-14.7518903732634));
#961=CARTESIAN_POINT('',(14.9462203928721,5.51228457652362,-15.0717374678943));
#962=CARTESIAN_POINT('',(14.108832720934,5.5627848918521,-13.9448141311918));
#963=CARTESIAN_POINT('',(14.0844976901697,5.60493440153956,-14.7113282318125));
#964=CARTESIAN_POINT('',(14.6780229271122,5.97161873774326,-15.0323834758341));
#965=CARTESIAN_POINT('',(13.5596909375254,6.51392636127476,-13.8917477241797));
#966=CARTESIAN_POINT('',(13.5473047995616,6.53537978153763,-14.6566795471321));
#967=CARTESIAN_POINT('',(14.1427437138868,6.89170174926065,-14.9793170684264));
#968=CARTESIAN_POINT('',(13.2848087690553,6.99003624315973,-13.8780348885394));
#969=CARTESIAN_POINT('',(13.2783319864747,7.00125435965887,-14.6425383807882));
#970=CARTESIAN_POINT('',(13.8756619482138,7.35245057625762,-14.9656042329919));
#971=CARTESIAN_POINT('',(12.7327569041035,7.94621812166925,-13.8767935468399));
#972=CARTESIAN_POINT('',(12.7384304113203,7.93639131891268,-14.6412598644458));
#973=CARTESIAN_POINT('',(13.3408192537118,8.27865873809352,-14.9643628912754));
#974=CARTESIAN_POINT('',(12.4555870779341,8.42629034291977,-13.8894823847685));
#975=CARTESIAN_POINT('',(12.4672197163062,8.40614202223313,-14.6543453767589));
#976=CARTESIAN_POINT('',(13.0730709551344,8.74412553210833,-14.9770517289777));
#977=CARTESIAN_POINT('',(11.9018569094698,9.38537912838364,-13.9409693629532));
#978=CARTESIAN_POINT('',(11.9255486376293,9.34434385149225,-14.7073683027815));
#979=CARTESIAN_POINT('',(12.5393803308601,9.67534824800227,-15.028538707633));
#980=CARTESIAN_POINT('',(11.6252965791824,9.86439567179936,-13.9797680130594));
#981=CARTESIAN_POINT('',(11.654816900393,9.81326497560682,-14.7473598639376));
#982=CARTESIAN_POINT('',(12.2734380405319,10.1411041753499,-15.0673373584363));
#983=CARTESIAN_POINT('',(11.0727770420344,10.8213875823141,-14.082083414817));
#984=CARTESIAN_POINT('',(11.1139499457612,10.7500740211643,-14.8526638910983));
#985=CARTESIAN_POINT('',(11.7429156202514,11.0731906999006,-15.1696527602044));
#986=CARTESIAN_POINT('',(10.7968201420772,11.2993589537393,-14.1456494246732));
#987=CARTESIAN_POINT('',(10.8435846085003,11.2183605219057,-14.9181218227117));
#988=CARTESIAN_POINT('',(11.4783392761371,11.5395205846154,-15.2332187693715));
#989=CARTESIAN_POINT('',(10.2464539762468,12.2526211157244,-14.2952887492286));
#990=CARTESIAN_POINT('',(10.3042434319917,12.1525268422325,-15.071984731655));
#991=CARTESIAN_POINT('',(10.9510132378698,12.4712590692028,-15.3828580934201));
#992=CARTESIAN_POINT('',(9.9720447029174,12.727911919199,-14.3813619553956));
#993=CARTESIAN_POINT('',(10.0350883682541,12.6187170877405,-15.1605045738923));
#994=CARTESIAN_POINT('',(10.6882635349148,12.936667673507,-15.4689312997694));
#995=CARTESIAN_POINT('',(9.41742229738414,13.6885461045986,-14.576102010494));
#996=CARTESIAN_POINT('',(9.49082134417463,13.5614152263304,-15.3605048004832));
#997=CARTESIAN_POINT('',(10.1571629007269,13.87900092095,-15.6636713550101));
#998=CARTESIAN_POINT('',(9.13725867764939,14.1738037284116,-14.6853281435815));
#999=CARTESIAN_POINT('',(9.2156465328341,14.0380319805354,-15.4726650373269));
#1000=CARTESIAN_POINT('',(9.88885816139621,14.3558878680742,-15.7728974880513));
#1001=CARTESIAN_POINT('',(8.57884759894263,15.1410000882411,-14.9219929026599));
#1002=CARTESIAN_POINT('',(8.66684700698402,14.9885806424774,-15.7153621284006));
#1003=CARTESIAN_POINT('',(9.3537216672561,15.307986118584,-16.0095622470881));
#1004=CARTESIAN_POINT('',(8.30060032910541,15.6229384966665,-15.0494333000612));
#1005=CARTESIAN_POINT('',(8.39314955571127,15.4626385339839,-15.8460060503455));
#1006=CARTESIAN_POINT('',(9.08689005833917,15.7831972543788,-16.1370026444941));
#1007=CARTESIAN_POINT('',(7.747142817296,16.581555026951,-15.3192526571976));
#1008=CARTESIAN_POINT('',(7.84837391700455,16.4062176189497,-16.1222680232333));
#1009=CARTESIAN_POINT('',(8.55556548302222,16.7298037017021,-16.4068220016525));
#1010=CARTESIAN_POINT('',(7.47192481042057,17.0582465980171,-15.4615684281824));
#1011=CARTESIAN_POINT('',(7.57726039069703,16.8758000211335,-16.2679029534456));
#1012=CARTESIAN_POINT('',(8.29106741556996,17.201206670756,-16.5491377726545));
#1013=CARTESIAN_POINT('',(6.92335285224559,18.0084011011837,-15.7592035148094));
#1014=CARTESIAN_POINT('',(7.03644742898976,17.8125155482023,-16.5721917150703));
#1015=CARTESIAN_POINT('',(7.76319186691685,18.1419645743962,-16.8467728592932));
#1016=CARTESIAN_POINT('',(6.64999827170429,18.4818651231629,-15.9145181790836));
#1017=CARTESIAN_POINT('',(6.76675438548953,18.2796376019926,-16.7308938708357));
#1018=CARTESIAN_POINT('',(7.49981402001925,18.6113201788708,-17.0020875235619));
#1019=CARTESIAN_POINT('',(6.37746539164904,18.9539059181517,-16.0752036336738));
#1020=CARTESIAN_POINT('',(6.4982770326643,18.7446540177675,-16.8945434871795));
#1021=CARTESIAN_POINT('',(7.2368422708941,19.0797270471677,-17.1627729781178));
#1022=(BOUNDED_SURFACE() B_SPLINE_SURFACE(3,2,((#920,#921,#922),(#923,#924,#925),(#926,#927,
#928),(#929,#930,#931),(#932,#933,#934),(#935,#936,#937),(#938,#939,#940),(#941,#942,#943),
(#944,#945,#946),(#947,#948,#949),(#950,#951,#952),(#953,#954,#955),(#956,#957,#958),(#959,#960,
#961),(#962,#963,#964),(#965,#966,#967),(#968,#969,#970),(#971,#972,#973),(#974,#975,#976),
(#977,#978,#979),(#980,#981,#982),(#983,#984,#985),(#986,#987,#988),(#989,#990,#991),(#992,#993,
#994),(#995,#996,#997),(#998,#999,#1000),(#1001,#1002,#1003),(#1004,#1005,#1006),(#1007,#1008,
#1009),(#1010,#1011,#1012),(#1013,#1014,#1015),(#1016,#1017,#1018),(#1019,#1020,#1021)),
.UNSPECIFIED.,.F.,.F.,.F.) B_SPLINE_SURFACE_WITH_KNOTS((4,2,2,2,2,2,2,2,2,2,2,2,2,2,2,2,4),(3,
3),(0.,1.69054342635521,3.38167421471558,5.07965265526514,6.77747031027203,8.42993159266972,
10.0824002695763,11.7316152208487,13.3808031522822,15.0436212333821,16.7064717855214,
18.3726464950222,20.0388131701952,21.7510843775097,23.4635222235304,25.1689606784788,
26.8737914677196),(0.,1.),
.UNSPECIFIED.) GEOMETRIC_REPRESENTATION_ITEM() RATIONAL_B_SPLINE_SURFACE(((1.,0.814768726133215,
1.),(1.,0.816408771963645,1.),(1.,0.818073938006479,1.),(1.,0.821407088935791,1.),(1.,
0.823075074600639,1.),(1.,0.826371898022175,1.),(1.,0.82800054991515,1.),(1.,0.831141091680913,
1.),(1.,0.832652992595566,1.),(1.,0.835437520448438,1.),(1.,0.836715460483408,1.),(1.,
0.838994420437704,1.),(1.,0.839995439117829,1.),(1.,0.841638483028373,1.),(1.,0.842281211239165,
1.),(1.,0.843152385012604,1.),(1.,0.843380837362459,1.),(1.,0.843401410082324,1.),(1.,
0.843189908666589,1.),(1.,0.842344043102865,1.),(1.,0.841709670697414,1.),(1.,0.840075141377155,
1.),(1.,0.839074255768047,1.),(1.,0.836788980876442,1.),(1.,0.835504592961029,1.),(1.,
0.832702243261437,1.),(1.,0.831178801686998,1.),(1.,0.82801277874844,1.),(1.,0.826370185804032,
1.),(1.,0.823045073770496,1.),(1.,0.821362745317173,1.),(1.,0.818001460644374,1.),(1.,
0.816322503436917,1.),(1.,0.814669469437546,1.))) REPRESENTATION_ITEM('') SURFACE());
#1023=CARTESIAN_POINT('',(19.5869636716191,-3.9256162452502,-16.0655775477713));
#1024=CARTESIAN_POINT('',(19.3166826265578,-3.4574757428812,-15.9064549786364));
#1025=CARTESIAN_POINT('',(19.0455921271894,-2.9879332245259,-15.7526340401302));
#1026=CARTESIAN_POINT('',(18.5015795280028,-2.0456757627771,-15.4577952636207));
#1027=CARTESIAN_POINT('',(18.2286568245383,-1.57295977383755,-15.3167818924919));
#1028=CARTESIAN_POINT('',(17.67984590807,-0.622391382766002,-15.0493314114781));
#1029=CARTESIAN_POINT('',(17.4039501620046,-0.144525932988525,-14.922955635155));
#1030=CARTESIAN_POINT('',(16.8502740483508,0.814469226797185,-14.6880992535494));
#1031=CARTESIAN_POINT('',(16.5724938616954,1.29559862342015,-14.5796169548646));
#1032=CARTESIAN_POINT('',(16.0225443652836,2.24813909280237,-14.3859363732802));
#1033=CARTESIAN_POINT('',(15.7504234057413,2.71946642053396,-14.3001934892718));
#1034=CARTESIAN_POINT('',(15.2046530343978,3.66476843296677,-14.1507918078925));
#1035=CARTESIAN_POINT('',(14.9310036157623,4.13874312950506,-14.087133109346));
#1036=CARTESIAN_POINT('',(14.3830923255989,5.08775332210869,-13.9841681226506));
#1037=CARTESIAN_POINT('',(14.108832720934,5.5627848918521,-13.9448141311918));
#1038=CARTESIAN_POINT('',(13.5596909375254,6.51392636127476,-13.8917477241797));
#1039=CARTESIAN_POINT('',(13.2848087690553,6.99003624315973,-13.8780348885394));
#1040=CARTESIAN_POINT('',(12.7327569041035,7.94621812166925,-13.8767935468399));
#1041=CARTESIAN_POINT('',(12.4555870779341,8.42629034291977,-13.8894823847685));
#1042=CARTESIAN_POINT('',(11.9018569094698,9.38537912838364,-13.9409693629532));
#1043=CARTESIAN_POINT('',(11.6252965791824,9.86439567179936,-13.9797680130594));
#1044=CARTESIAN_POINT('',(11.0727770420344,10.8213875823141,-14.082083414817));
#1045=CARTESIAN_POINT('',(10.7968201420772,11.2993589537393,-14.1456494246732));
#1046=CARTESIAN_POINT('',(10.2464539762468,12.2526211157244,-14.2952887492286));
#1047=CARTESIAN_POINT('',(9.9720447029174,12.727911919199,-14.3813619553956));
#1048=CARTESIAN_POINT('',(9.41742229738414,13.6885461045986,-14.576102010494));
#1049=CARTESIAN_POINT('',(9.13725867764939,14.1738037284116,-14.6853281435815));
#1050=CARTESIAN_POINT('',(8.57884759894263,15.1410000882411,-14.9219929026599));
#1051=CARTESIAN_POINT('',(8.30060032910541,15.6229384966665,-15.0494333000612));
#1052=CARTESIAN_POINT('',(7.747142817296,16.581555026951,-15.3192526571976));
#1053=CARTESIAN_POINT('',(7.47192481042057,17.0582465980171,-15.4615684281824));
#1054=CARTESIAN_POINT('',(6.92335285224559,18.0084011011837,-15.7592035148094));
#1055=CARTESIAN_POINT('',(6.64999827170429,18.4818651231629,-15.9145181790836));
#1056=CARTESIAN_POINT('',(6.37746539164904,18.9539059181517,-16.0752036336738));
#1057=B_SPLINE_CURVE_WITH_KNOTS('',3,(#1023,#1024,#1025,#1026,#1027,#1028,#1029,#1030,#1031,
#1032,#1033,#1034,#1035,#1036,#1037,#1038,#1039,#1040,#1041,#1042,#1043,#1044,#1045,#1046,#1047,
#1048,#1049,#1050,#1051,#1052,#1053,#1054,#1055,#1056),.UNSPECIFIED.,.F.,.F.,(4,2,2,2,2,2,2,2,2,
2,2,2,2,2,2,2,4),(0.,1.69054342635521,3.38167421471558,5.07965265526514,6.77747031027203,
8.42993159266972,10.0824002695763,11.7316152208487,13.3808031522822,15.0436212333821,
16.7064717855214,18.3726464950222,20.0388131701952,21.7510843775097,23.4635222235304,
25.1689606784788,26.8737914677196),.UNSPECIFIED.);
#1058=EDGE_CURVE('E444',#915,#697,#1057,.T.);
#1059=ORIENTED_EDGE('',*,*,#1058,.T.);
#1060=ORIENTED_EDGE('',*,*,#700,.T.);
#1061=CARTESIAN_POINT('',(17.3206235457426,-0.000199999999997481,-1.33981262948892));
#1062=CARTESIAN_POINT('',(17.130274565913,0.329494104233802,-1.22992178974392));
#1063=CARTESIAN_POINT('',(16.939183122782,0.660474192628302,-1.1250175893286));
#1064=CARTESIAN_POINT('',(16.5554679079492,1.32508844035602,-0.926568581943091));
#1065=CARTESIAN_POINT('',(16.3628436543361,1.6587234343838,-0.833027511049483));
#1066=CARTESIAN_POINT('',(15.9756905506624,2.32929228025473,-0.658562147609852));
#1067=CARTESIAN_POINT('',(15.7811583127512,2.66623200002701,-0.577667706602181));
#1068=CARTESIAN_POINT('',(15.3907420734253,3.34245276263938,-0.430232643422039));
#1069=CARTESIAN_POINT('',(15.1948581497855,3.68173367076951,-0.363691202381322));
#1070=CARTESIAN_POINT('',(14.8067578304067,4.35394314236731,-0.247792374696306));
#1071=CARTESIAN_POINT('',(14.6145702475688,4.68682180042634,-0.198051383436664));
#1072=CARTESIAN_POINT('',(14.2293144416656,5.35410443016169,-0.114646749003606));
#1073=CARTESIAN_POINT('',(14.0362462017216,5.68850843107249,-0.0809834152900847));
#1074=CARTESIAN_POINT('',(13.6497853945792,6.35787818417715,-0.0305840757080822));
#1075=CARTESIAN_POINT('',(13.4563934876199,6.69284279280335,-0.0138279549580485));
#1076=CARTESIAN_POINT('',(13.0694311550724,7.363081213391,0.00239660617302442));
#1077=CARTESIAN_POINT('',(12.8758607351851,7.69835501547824,0.00186558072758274));
#1078=CARTESIAN_POINT('',(12.5139822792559,8.3251468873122,-0.0152766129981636));
#1079=CARTESIAN_POINT('',(12.3456484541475,8.61670962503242,-0.0297968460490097));
#1080=CARTESIAN_POINT('',(12.0093680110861,9.19916443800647,-0.0716371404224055));
#1081=CARTESIAN_POINT('',(11.8414214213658,9.49005646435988,-0.0989581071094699));
#1082=CARTESIAN_POINT('',(11.5060066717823,10.0710118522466,-0.165923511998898));
#1083=CARTESIAN_POINT('',(11.338539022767,10.3610743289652,-0.205578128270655));
#1084=CARTESIAN_POINT('',(11.0043888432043,10.939839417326,-0.296515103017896));
#1085=CARTESIAN_POINT('',(10.8377063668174,11.2285419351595,-0.34779825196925));
#1086=CARTESIAN_POINT('',(10.3317324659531,12.1049144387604,-0.520386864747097));
#1087=CARTESIAN_POINT('',(9.99390625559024,12.6900465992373,-0.658901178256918));
#1088=CARTESIAN_POINT('',(9.32329122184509,13.8515859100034,-0.973271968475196));
#1089=CARTESIAN_POINT('',(8.99049381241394,14.4280079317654,-1.14905461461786));
#1090=CARTESIAN_POINT('',(8.66013856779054,15.0002,-1.33981262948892));
#1091=B_SPLINE_CURVE_WITH_KNOTS('',3,(#1061,#1062,#1063,#1064,#1065,#1066,#1067,#1068,#1069,
#1070,#1071,#1072,#1073,#1074,#1075,#1076,#1077,#1078,#1079,#1080,#1081,#1082,#1083,#1084,#1085,
#1086,#1087,#1088,#1089,#1090),.UNSPECIFIED.,.F.,.F.,(4,2,2,2,2,2,2,2,2,2,2,2,2,2,4),(0.,
1.18875411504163,2.37789802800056,3.56980778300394,4.76164951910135,5.92407379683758,
7.0865204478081,8.24758247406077,9.40860862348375,10.4193068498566,11.4300765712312,
12.4416826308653,13.4533574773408,15.5211962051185,17.5849760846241),.UNSPECIFIED.);
#1092=EDGE_CURVE('E738',#44,#699,#1091,.T.);
#1093=ORIENTED_EDGE('',*,*,#1092,.F.);
#1094=EDGE_CURVE('E200',#917,#44,#1091,.T.);
#1095=ORIENTED_EDGE('',*,*,#1094,.F.);
#1096=EDGE_LOOP('',(#919,#1059,#1060,#1093,#1095));
#1097=FACE_BOUND('',#1096,.T.);
#1098=ADVANCED_FACE('F453',(#1097),#909,.T.);
#1099=CARTESIAN_POINT('',(8.66025403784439,-15.,-20.));
#1100=DIRECTION('',(0.866025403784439,-0.5,0.));
#1101=DIRECTION('',(0.5,0.866025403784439,0.));
#1102=AXIS2_PLACEMENT_3D('',#1099,#1100,#1101);
#1103=PLANE('',#1102);
#1104=ORIENTED_EDGE('',*,*,#235,.F.);
#1105=CARTESIAN_POINT('',(6.393798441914,-18.9256162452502,-16.0655775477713));
#1106=CARTESIAN_POINT('',(6.51440137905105,-18.7167258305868,-16.8847177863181));
#1107=CARTESIAN_POINT('',(7.25260114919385,-19.0516555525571,-17.1531468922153));
#1108=CARTESIAN_POINT('',(6.66407948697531,-18.4574757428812,-15.9064549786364));
#1109=CARTESIAN_POINT('',(6.78065806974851,-18.2555557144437,-16.7226516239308));
#1110=CARTESIAN_POINT('',(7.5133854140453,-18.5871374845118,-16.9940243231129));
#1111=CARTESIAN_POINT('',(6.93516998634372,-17.9879332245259,-15.7526340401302));
#1112=CARTESIAN_POINT('',(7.04811108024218,-17.7923135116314,-16.5654726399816));
#1113=CARTESIAN_POINT('',(7.77457087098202,-18.1216861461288,-16.8402033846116));
#1114=CARTESIAN_POINT('',(7.47918258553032,-17.0456757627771,-15.4577952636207));
#1115=CARTESIAN_POINT('',(7.58441956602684,-16.863399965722,-16.2640376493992));
#1116=CARTESIAN_POINT('',(8.29804362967,-17.188773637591,-16.5453646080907));
#1117=CARTESIAN_POINT('',(7.75210528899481,-16.5729597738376,-15.3167818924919));
#1118=CARTESIAN_POINT('',(7.85326910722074,-16.3977389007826,-16.1197341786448));
#1119=CARTESIAN_POINT('',(8.56033128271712,-16.7213118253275,-16.4043512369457));
#1120=CARTESIAN_POINT('',(8.30091620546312,-15.622391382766,-15.0493314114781));
#1121=CARTESIAN_POINT('',(8.39346845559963,-15.4620861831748,-15.8458961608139));
#1122=CARTESIAN_POINT('',(9.08719148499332,-15.7826613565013,-16.1369007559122));
#1123=CARTESIAN_POINT('',(8.57681195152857,-15.1445259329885,-14.922955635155));
#1124=CARTESIAN_POINT('',(8.66485281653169,-14.9920346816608,-15.716344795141));
#1125=CARTESIAN_POINT('',(9.35176898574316,-15.3114652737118,-16.0105249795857));
#1126=CARTESIAN_POINT('',(9.1304880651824,-14.1855307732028,-14.6880992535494));
#1127=CARTESIAN_POINT('',(9.20900326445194,-14.0495384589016,-15.4755041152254));
#1128=CARTESIAN_POINT('',(9.88237158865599,-14.3674236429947,-15.7756685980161));
#1129=CARTESIAN_POINT('',(9.40826825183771,-13.7044013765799,-14.5796169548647));
#1130=CARTESIAN_POINT('',(9.4818400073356,-13.5769713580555,-15.3641105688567));
#1131=CARTESIAN_POINT('',(10.1483965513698,-13.894578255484,-15.6671862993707));
#1132=CARTESIAN_POINT('',(9.95821774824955,-12.7518609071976,-14.3859363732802));
#1133=CARTESIAN_POINT('',(10.0215318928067,-12.6421975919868,-15.1652022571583));
#1134=CARTESIAN_POINT('',(10.675023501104,-12.9601379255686,-15.4735057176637));
#1135=CARTESIAN_POINT('',(10.2303387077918,-12.280533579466,-14.3001934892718));
#1136=CARTESIAN_POINT('',(10.2884474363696,-12.1798863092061,-15.0770255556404));
#1137=CARTESIAN_POINT('',(10.9355805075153,-12.4985798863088,-15.3877628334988));
#1138=CARTESIAN_POINT('',(10.7761090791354,-11.3352315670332,-14.1507918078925));
#1139=CARTESIAN_POINT('',(10.8232996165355,-11.2534951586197,-14.9234107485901));
#1140=CARTESIAN_POINT('',(11.4584878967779,-11.5745471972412,-15.2383611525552));
#1141=CARTESIAN_POINT('',(11.0497584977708,-10.8612568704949,-14.087133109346));
#1142=CARTESIAN_POINT('',(11.0914098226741,-10.78911465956,-14.8578604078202));
#1143=CARTESIAN_POINT('',(11.720838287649,-11.1120725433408,-15.1747024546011));
#1144=CARTESIAN_POINT('',(11.5976697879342,-9.91224667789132,-13.9841681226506));
#1145=CARTESIAN_POINT('',(11.6277807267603,-9.86009300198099,-14.7518903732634));
#1146=CARTESIAN_POINT('',(12.2468886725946,-10.1876642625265,-15.0717374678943));
#1147=CARTESIAN_POINT('',(11.8719293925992,-9.4372151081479,-13.9448141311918));
#1148=CARTESIAN_POINT('',(11.8962644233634,-9.39506559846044,-14.7113282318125));
#1149=CARTESIAN_POINT('',(12.5105849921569,-9.72573136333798,-15.0323834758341));
#1150=CARTESIAN_POINT('',(12.4210711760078,-8.48607363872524,-13.8917477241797));
#1151=CARTESIAN_POINT('',(12.4334573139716,-8.46462021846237,-14.6566795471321));
#1152=CARTESIAN_POINT('',(13.0397606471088,-8.80212446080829,-14.9793170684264));
#1153=CARTESIAN_POINT('',(12.6959533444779,-8.00996375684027,-13.8780348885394));
#1154=CARTESIAN_POINT('',(12.7024301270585,-7.99874564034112,-14.6425383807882));
#1155=CARTESIAN_POINT('',(13.3052399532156,-8.34045045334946,-14.9656042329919));
#1156=CARTESIAN_POINT('',(13.2480052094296,-7.05378187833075,-13.8767935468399));
#1157=CARTESIAN_POINT('',(13.2423317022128,-7.06360868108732,-14.6412598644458));
#1158=CARTESIAN_POINT('',(13.8399384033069,-7.41415901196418,-14.9643628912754));
#1159=CARTESIAN_POINT('',(13.5251750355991,-6.57370965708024,-13.8894823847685));
#1160=CARTESIAN_POINT('',(13.5135423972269,-6.59385797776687,-14.6543453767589));
#1161=CARTESIAN_POINT('',(14.1091703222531,-6.94954878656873,-14.9770517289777));
#1162=CARTESIAN_POINT('',(14.0789052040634,-5.61462087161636,-13.9409693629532));
#1163=CARTESIAN_POINT('',(14.0552134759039,-5.65565614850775,-14.7073683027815));
#1164=CARTESIAN_POINT('',(14.6487875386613,-6.02174779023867,-15.028538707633));
#1165=CARTESIAN_POINT('',(14.3554655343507,-5.13560432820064,-13.9797680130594));
#1166=CARTESIAN_POINT('',(14.3259452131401,-5.18673502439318,-14.7473598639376));
#1167=CARTESIAN_POINT('',(14.9191728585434,-5.55855704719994,-15.0673373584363));
#1168=CARTESIAN_POINT('',(14.9079850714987,-4.17861241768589,-14.082083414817));
#1169=CARTESIAN_POINT('',(14.866812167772,-4.2499259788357,-14.8526638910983));
#1170=CARTESIAN_POINT('',(15.4611222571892,-4.63306789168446,-15.1696527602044));
#1171=CARTESIAN_POINT('',(15.183941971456,-3.70064104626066,-14.1456494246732));
#1172=CARTESIAN_POINT('',(15.1371775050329,-3.78163947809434,-14.9181218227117));
#1173=CARTESIAN_POINT('',(15.7326876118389,-4.17077311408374,-15.2332187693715));
#1174=CARTESIAN_POINT('',(15.7343081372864,-2.74737888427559,-14.2952887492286));
#1175=CARTESIAN_POINT('',(15.6765186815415,-2.84747315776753,-15.071984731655));
#1176=CARTESIAN_POINT('',(16.2759337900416,-3.24822612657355,-15.3828580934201));
#1177=CARTESIAN_POINT('',(16.0087174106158,-2.27208808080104,-14.3813619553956));
#1178=CARTESIAN_POINT('',(15.9456737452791,-2.3812829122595,-15.1605045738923));
#1179=CARTESIAN_POINT('',(16.5476146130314,-2.78797390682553,-15.4689312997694));
#1180=CARTESIAN_POINT('',(16.563339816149,-1.31145389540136,-14.576102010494));
#1181=CARTESIAN_POINT('',(16.4899407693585,-1.43858477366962,-15.3605048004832));
#1182=CARTESIAN_POINT('',(17.0981488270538,-1.85686064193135,-15.6636713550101));
#1183=CARTESIAN_POINT('',(16.8435034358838,-0.826196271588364,-14.6853281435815));
#1184=CARTESIAN_POINT('',(16.7651155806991,-0.96196801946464,-15.4726650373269));
#1185=CARTESIAN_POINT('',(17.3769926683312,-1.38605844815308,-15.7728974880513));
#1186=CARTESIAN_POINT('',(17.4019145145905,0.141000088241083,-14.9219929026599));
#1187=CARTESIAN_POINT('',(17.3139151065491,-0.0114193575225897,-15.7153621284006));
#1188=CARTESIAN_POINT('',(17.9339656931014,-0.446567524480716,-16.0095622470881));
#1189=CARTESIAN_POINT('',(17.6801617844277,0.62293849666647,-15.0494333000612));
#1190=CARTESIAN_POINT('',(17.5876125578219,0.462638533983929,-15.8460060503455));
#1191=CARTESIAN_POINT('',(18.2120948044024,0.0221209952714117,-16.1370026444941));
#1192=CARTESIAN_POINT('',(18.2336192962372,1.58155502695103,-15.3192526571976));
#1193=CARTESIAN_POINT('',(18.1323881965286,1.40621761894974,-16.1222680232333));
#1194=CARTESIAN_POINT('',(18.7662177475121,0.955564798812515,-16.4068220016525));
#1195=CARTESIAN_POINT('',(18.5088373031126,2.05824659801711,-15.4615684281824));
#1196=CARTESIAN_POINT('',(18.4035017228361,1.87580002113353,-16.2679029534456));
#1197=CARTESIAN_POINT('',(19.042215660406,1.42032832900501,-16.5491377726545));
#1198=CARTESIAN_POINT('',(19.0574092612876,3.00840110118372,-15.7592035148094));
#1199=CARTESIAN_POINT('',(18.9443146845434,2.81251554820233,-16.5721917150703));
#1200=CARTESIAN_POINT('',(19.5929981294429,2.34786091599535,-16.8467728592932));
#1201=CARTESIAN_POINT('',(19.3307638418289,3.48186512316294,-15.9145181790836));
#1202=CARTESIAN_POINT('',(19.2140077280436,3.27963760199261,-16.7308938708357));
#1203=CARTESIAN_POINT('',(19.8677830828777,2.81063062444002,-17.0020875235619));
#1204=CARTESIAN_POINT('',(19.6032967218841,3.95390591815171,-16.0752036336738));
#1205=CARTESIAN_POINT('',(19.4824850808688,3.7446540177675,-16.8945434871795));
#1206=CARTESIAN_POINT('',(20.1419494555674,3.2725742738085,-17.1627729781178));
#1207=(BOUNDED_SURFACE() B_SPLINE_SURFACE(3,2,((#1105,#1106,#1107),(#1108,#1109,#1110),(#1111,
#1112,#1113),(#1114,#1115,#1116),(#1117,#1118,#1119),(#1120,#1121,#1122),(#1123,#1124,#1125),
(#1126,#1127,#1128),(#1129,#1130,#1131),(#1132,#1133,#1134),(#1135,#1136,#1137),(#1138,#1139,
#1140),(#1141,#1142,#1143),(#1144,#1145,#1146),(#1147,#1148,#1149),(#1150,#1151,#1152),(#1153,
#1154,#1155),(#1156,#1157,#1158),(#1159,#1160,#1161),(#1162,#1163,#1164),(#1165,#1166,#1167),
(#1168,#1169,#1170),(#1171,#1172,#1173),(#1174,#1175,#1176),(#1177,#1178,#1179),(#1180,#1181,
#1182),(#1183,#1184,#1185),(#1186,#1187,#1188),(#1189,#1190,#1191),(#1192,#1193,#1194),(#1195,
#1196,#1197),(#1198,#1199,#1200),(#1201,#1202,#1203),(#1204,#1205,#1206)),.UNSPECIFIED.,.F.,.F.,
.F.) B_SPLINE_SURFACE_WITH_KNOTS((4,2,2,2,2,2,2,2,2,2,2,2,2,2,2,2,4),(3,3),(0.,1.69054342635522,
3.38167421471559,5.07965265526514,6.77747031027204,8.42993159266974,10.0824002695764,
11.7316152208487,13.3808031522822,15.0436212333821,16.7064717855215,18.3726464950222,
20.0388131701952,21.7510843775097,23.4635222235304,25.1689606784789,26.8737914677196),(0.,1.),
.UNSPECIFIED.) GEOMETRIC_REPRESENTATION_ITEM() RATIONAL_B_SPLINE_SURFACE(((1.,0.814768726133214,
1.),(1.,0.816408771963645,1.),(1.,0.818073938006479,1.),(1.,0.821407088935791,1.),(1.,
0.823075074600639,1.),(1.,0.826371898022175,1.),(1.,0.82800054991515,1.),(1.,0.831141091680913,
1.),(1.,0.832652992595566,1.),(1.,0.835437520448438,1.),(1.,0.836715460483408,1.),(1.,
0.838994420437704,1.),(1.,0.839995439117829,1.),(1.,0.841638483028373,1.),(1.,0.842281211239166,
1.),(1.,0.843152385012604,1.),(1.,0.843380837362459,1.),(1.,0.843401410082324,1.),(1.,
0.843189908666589,1.),(1.,0.842344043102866,1.),(1.,0.841709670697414,1.),(1.,0.840075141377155,
1.),(1.,0.839074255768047,1.),(1.,0.836788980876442,1.),(1.,0.835504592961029,1.),(1.,
0.832702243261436,1.),(1.,0.831178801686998,1.),(1.,0.82801277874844,1.),(1.,0.826370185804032,
1.),(1.,0.823045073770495,1.),(1.,0.821362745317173,1.),(1.,0.818001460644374,1.),(1.,
0.816322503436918,1.),(1.,0.814669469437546,1.))) REPRESENTATION_ITEM('') SURFACE());
#1208=CARTESIAN_POINT('',(6.393798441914,-18.9256162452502,-16.0655775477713));
#1209=CARTESIAN_POINT('',(6.66407948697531,-18.4574757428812,-15.9064549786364));
#1210=CARTESIAN_POINT('',(6.93516998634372,-17.9879332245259,-15.7526340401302));
#1211=CARTESIAN_POINT('',(7.47918258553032,-17.0456757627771,-15.4577952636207));
#1212=CARTESIAN_POINT('',(7.75210528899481,-16.5729597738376,-15.3167818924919));
#1213=CARTESIAN_POINT('',(8.30091620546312,-15.622391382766,-15.0493314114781));
#1214=CARTESIAN_POINT('',(8.57681195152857,-15.1445259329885,-14.922955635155));
#1215=CARTESIAN_POINT('',(9.1304880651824,-14.1855307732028,-14.6880992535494));
#1216=CARTESIAN_POINT('',(9.40826825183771,-13.7044013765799,-14.5796169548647));
#1217=CARTESIAN_POINT('',(9.95821774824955,-12.7518609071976,-14.3859363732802));
#1218=CARTESIAN_POINT('',(10.2303387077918,-12.280533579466,-14.3001934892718));
#1219=CARTESIAN_POINT('',(10.7761090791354,-11.3352315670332,-14.1507918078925));
#1220=CARTESIAN_POINT('',(11.0497584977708,-10.8612568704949,-14.087133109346));
#1221=CARTESIAN_POINT('',(11.5976697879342,-9.91224667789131,-13.9841681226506));
#1222=CARTESIAN_POINT('',(11.8719293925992,-9.43721510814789,-13.9448141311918));
#1223=CARTESIAN_POINT('',(12.4210711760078,-8.48607363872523,-13.8917477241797));
#1224=CARTESIAN_POINT('',(12.6959533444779,-8.00996375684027,-13.8780348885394));
#1225=CARTESIAN_POINT('',(13.2480052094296,-7.05378187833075,-13.8767935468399));
#1226=CARTESIAN_POINT('',(13.5251750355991,-6.57370965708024,-13.8894823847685));
#1227=CARTESIAN_POINT('',(14.0789052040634,-5.61462087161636,-13.9409693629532));
#1228=CARTESIAN_POINT('',(14.3554655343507,-5.13560432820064,-13.9797680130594));
#1229=CARTESIAN_POINT('',(14.9079850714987,-4.17861241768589,-14.082083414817));
#1230=CARTESIAN_POINT('',(15.183941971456,-3.70064104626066,-14.1456494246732));
#1231=CARTESIAN_POINT('',(15.7343081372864,-2.74737888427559,-14.2952887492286));
#1232=CARTESIAN_POINT('',(16.0087174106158,-2.27208808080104,-14.3813619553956));
#1233=CARTESIAN_POINT('',(16.563339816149,-1.31145389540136,-14.576102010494));
#1234=CARTESIAN_POINT('',(16.8435034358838,-0.826196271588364,-14.6853281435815));
#1235=CARTESIAN_POINT('',(17.4019145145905,0.141000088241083,-14.9219929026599));
#1236=CARTESIAN_POINT('',(17.6801617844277,0.62293849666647,-15.0494333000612));
#1237=CARTESIAN_POINT('',(18.2336192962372,1.58155502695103,-15.3192526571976));
#1238=CARTESIAN_POINT('',(18.5088373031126,2.05824659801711,-15.4615684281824));
#1239=CARTESIAN_POINT('',(19.0574092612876,3.00840110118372,-15.7592035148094));
#1240=CARTESIAN_POINT('',(19.3307638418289,3.48186512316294,-15.9145181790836));
#1241=CARTESIAN_POINT('',(19.6032967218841,3.95390591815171,-16.0752036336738));
#1242=B_SPLINE_CURVE_WITH_KNOTS('',3,(#1208,#1209,#1210,#1211,#1212,#1213,#1214,#1215,#1216,
#1217,#1218,#1219,#1220,#1221,#1222,#1223,#1224,#1225,#1226,#1227,#1228,#1229,#1230,#1231,#1232,
#1233,#1234,#1235,#1236,#1237,#1238,#1239,#1240,#1241),.UNSPECIFIED.,.F.,.F.,(4,2,2,2,2,2,2,2,2,
2,2,2,2,2,2,2,4),(0.,1.69054342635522,3.38167421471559,5.07965265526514,6.77747031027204,
8.42993159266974,10.0824002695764,11.7316152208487,13.3808031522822,15.0436212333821,
16.7064717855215,18.3726464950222,20.0388131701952,21.7510843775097,23.4635222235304,
25.1689606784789,26.8737914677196),.UNSPECIFIED.);
#1243=EDGE_CURVE('E703',#226,#915,#1242,.T.);
#1244=ORIENTED_EDGE('',*,*,#1243,.T.);
#1245=ORIENTED_EDGE('',*,*,#918,.T.);
#1246=CARTESIAN_POINT('',(8.66013856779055,-15.0002,-1.33981262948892));
#1247=CARTESIAN_POINT('',(8.85048754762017,-14.6705058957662,-1.22992178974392));
#1248=CARTESIAN_POINT('',(9.04157899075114,-14.3395258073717,-1.12501758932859));
#1249=CARTESIAN_POINT('',(9.42529420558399,-13.674911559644,-0.926568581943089));
#1250=CARTESIAN_POINT('',(9.61791845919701,-13.3412765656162,-0.833027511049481));
#1251=CARTESIAN_POINT('',(10.0050715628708,-12.6707077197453,-0.65856214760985));
#1252=CARTESIAN_POINT('',(10.199603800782,-12.333767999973,-0.57766770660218));
#1253=CARTESIAN_POINT('',(10.5900200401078,-11.6575472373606,-0.430232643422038));
#1254=CARTESIAN_POINT('',(10.7859039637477,-11.3182663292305,-0.363691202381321));
#1255=CARTESIAN_POINT('',(11.1740042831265,-10.6460568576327,-0.247792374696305));
#1256=CARTESIAN_POINT('',(11.3661918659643,-10.3131781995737,-0.198051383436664));
#1257=CARTESIAN_POINT('',(11.7514476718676,-9.64589556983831,-0.114646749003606));
#1258=CARTESIAN_POINT('',(11.9445159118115,-9.31149156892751,-0.0809834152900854));
#1259=CARTESIAN_POINT('',(12.3309767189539,-8.64212181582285,-0.0305840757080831));
#1260=CARTESIAN_POINT('',(12.5243686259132,-8.30715720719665,-0.013827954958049));
#1261=CARTESIAN_POINT('',(12.9113309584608,-7.636918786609,0.00239660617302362));
#1262=CARTESIAN_POINT('',(13.1049013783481,-7.30164498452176,0.00186558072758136));
#1263=CARTESIAN_POINT('',(13.4667798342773,-6.6748531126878,-0.0152766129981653));
#1264=CARTESIAN_POINT('',(13.6351136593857,-6.38329037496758,-0.0297968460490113));
#1265=CARTESIAN_POINT('',(13.9713941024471,-5.80083556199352,-0.0716371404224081));
#1266=CARTESIAN_POINT('',(14.1393406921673,-5.50994353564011,-0.0989581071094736));
#1267=CARTESIAN_POINT('',(14.4747554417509,-4.92898814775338,-0.165923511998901));
#1268=CARTESIAN_POINT('',(14.6422230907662,-4.63892567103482,-0.205578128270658));
#1269=CARTESIAN_POINT('',(14.9763732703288,-4.06016058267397,-0.296515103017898));
#1270=CARTESIAN_POINT('',(15.1430557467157,-3.77145806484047,-0.347798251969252));
#1271=CARTESIAN_POINT('',(15.6490296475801,-2.89508556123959,-0.5203868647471));
#1272=CARTESIAN_POINT('',(15.9868558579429,-2.30995340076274,-0.658901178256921));
#1273=CARTESIAN_POINT('',(16.6574708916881,-1.14841408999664,-0.973271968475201));
#1274=CARTESIAN_POINT('',(16.9902683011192,-0.571992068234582,-1.14905461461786));
#1275=CARTESIAN_POINT('',(17.3206235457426,0.000200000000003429,-1.33981262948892));
#1276=B_SPLINE_CURVE_WITH_KNOTS('',3,(#1246,#1247,#1248,#1249,#1250,#1251,#1252,#1253,#1254,
#1255,#1256,#1257,#1258,#1259,#1260,#1261,#1262,#1263,#1264,#1265,#1266,#1267,#1268,#1269,#1270,
#1271,#1272,#1273,#1274,#1275),.UNSPECIFIED.,.F.,.F.,(4,2,2,2,2,2,2,2,2,2,2,2,2,2,4),(0.,
1.18875411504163,2.37789802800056,3.56980778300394,4.76164951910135,5.92407379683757,
7.0865204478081,8.24758247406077,9.40860862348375,10.4193068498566,11.4300765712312,
12.4416826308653,13.4533574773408,15.5211962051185,17.5849760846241),.UNSPECIFIED.);
#1277=EDGE_CURVE('E190',#40,#917,#1276,.T.);
#1278=ORIENTED_EDGE('',*,*,#1277,.F.);
#1279=EDGE_CURVE('E741',#234,#40,#1276,.T.);
#1280=ORIENTED_EDGE('',*,*,#1279,.F.);
#1281=EDGE_LOOP('',(#1104,#1244,#1245,#1278,#1280));
#1282=FACE_BOUND('',#1281,.T.);
#1283=ADVANCED_FACE('F220',(#1282),#1103,.T.);
#1284=CARTESIAN_POINT('',(-8.66025403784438,-15.,-20.));
#1285=DIRECTION('',(0.,0.,-1.));
#1286=DIRECTION('',(-1.,0.,0.));
#1287=AXIS2_PLACEMENT_3D('',#1284,#1285,#1286);
#1288=PLANE('',#1287);
#1289=CARTESIAN_POINT('',(0.,0.,-20.));
#1290=DIRECTION('',(0.,0.,-1.));
#1291=DIRECTION('',(-1.,0.,0.));
#1292=AXIS2_PLACEMENT_3D('',#1289,#1290,#1291);
#1293=CIRCLE('',#1292,10.);
#1294=CARTESIAN_POINT('',(-10.,0.,-20.));
#1295=VERTEX_POINT('',#1294);
#1296=EDGE_CURVE('E358',#1295,#1295,#1293,.T.);
#1297=ORIENTED_EDGE('',*,*,#1296,.F.);
#1298=EDGE_LOOP('',(#1297));
#1299=FACE_BOUND('',#1298,.T.);
#1300=CARTESIAN_POINT('',(0.,0.,-20.));
#1301=DIRECTION('',(0.,0.,1.));
#1302=DIRECTION('',(1.,0.,0.));
#1303=AXIS2_PLACEMENT_3D('',#1300,#1301,#1302);
#1304=CIRCLE('',#1303,19.95);
#1305=CARTESIAN_POINT('',(19.95,0.,-20.));
#1306=VERTEX_POINT('',#1305);
#1307=EDGE_CURVE('E335',#1306,#1306,#1304,.T.);
#1308=ORIENTED_EDGE('',*,*,#1307,.F.);
#1309=EDGE_LOOP('',(#1308));
#1310=FACE_BOUND('',#1309,.T.);
#1311=ADVANCED_FACE('F463',(#1299,#1310),#1288,.T.);
#1312=CARTESIAN_POINT('',(0.,0.,-20.));
#1313=DIRECTION('',(0.,0.,1.));
#1314=DIRECTION('',(1.,0.,0.));
#1315=AXIS2_PLACEMENT_3D('',#1312,#1313,#1314);
#1316=CYLINDRICAL_SURFACE('',#1315,9.5);
#1317=CARTESIAN_POINT('',(0.,0.,4.29999999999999));
#1318=DIRECTION('',(0.,0.,-1.));
#1319=DIRECTION('',(-1.,0.,0.));
#1320=AXIS2_PLACEMENT_3D('',#1317,#1318,#1319);
#1321=CIRCLE('',#1320,9.5);
#1322=CARTESIAN_POINT('',(-9.5,0.,4.29999999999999));
#1323=VERTEX_POINT('',#1322);
#1324=EDGE_CURVE('E503',#1323,#1323,#1321,.T.);
#1325=ORIENTED_EDGE('',*,*,#1324,.F.);
#1326=EDGE_LOOP('',(#1325));
#1327=FACE_BOUND('',#1326,.T.);
#1328=CARTESIAN_POINT('',(0.,0.,-19.5));
#1329=DIRECTION('',(0.,0.,-1.));
#1330=DIRECTION('',(-1.,0.,0.));
#1331=AXIS2_PLACEMENT_3D('',#1328,#1329,#1330);
#1332=CIRCLE('',#1331,9.49999999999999);
#1333=CARTESIAN_POINT('',(-9.5,0.,-19.5));
#1334=VERTEX_POINT('',#1333);
#1335=EDGE_CURVE('E362',#1334,#1334,#1332,.T.);
#1336=ORIENTED_EDGE('',*,*,#1335,.T.);
#1337=EDGE_LOOP('',(#1336));
#1338=FACE_BOUND('',#1337,.T.);
#1339=ADVANCED_FACE('F185',(#1327,#1338),#1316,.F.);
#1340=CARTESIAN_POINT('',(0.,0.,0.));
#1341=DIRECTION('',(0.,0.,-1.));
#1342=DIRECTION('',(-1.,0.,0.));
#1343=AXIS2_PLACEMENT_3D('',#1340,#1341,#1342);
#1344=CONICAL_SURFACE('',#1343,15.,1.0471975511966);
#1345=ORIENTED_EDGE('',*,*,#680,.T.);
#1346=ORIENTED_EDGE('',*,*,#488,.T.);
#1347=ORIENTED_EDGE('',*,*,#33,.F.);
#1348=EDGE_LOOP('',(#1345,#1346,#1347));
#1349=FACE_BOUND('',#1348,.T.);
#1350=ADVANCED_FACE('F138',(#1349),#1344,.T.);
#1351=ORIENTED_EDGE('',*,*,#682,.T.);
#1352=ORIENTED_EDGE('',*,*,#56,.T.);
#1353=ORIENTED_EDGE('',*,*,#898,.T.);
#1354=EDGE_LOOP('',(#1351,#1352,#1353));
#1355=FACE_BOUND('',#1354,.T.);
#1356=ADVANCED_FACE('F182',(#1355),#1344,.T.);
#1357=ORIENTED_EDGE('',*,*,#900,.T.);
#1358=ORIENTED_EDGE('',*,*,#49,.F.);
#1359=ORIENTED_EDGE('',*,*,#1092,.T.);
#1360=EDGE_LOOP('',(#1357,#1358,#1359));
#1361=FACE_BOUND('',#1360,.T.);
#1362=ADVANCED_FACE('F180',(#1361),#1344,.T.);
#1363=ORIENTED_EDGE('',*,*,#1094,.T.);
#1364=ORIENTED_EDGE('',*,*,#45,.F.);
#1365=ORIENTED_EDGE('',*,*,#1277,.T.);
#1366=EDGE_LOOP('',(#1363,#1364,#1365));
#1367=FACE_BOUND('',#1366,.T.);
#1368=ADVANCED_FACE('F174',(#1367),#1344,.T.);
#1369=ORIENTED_EDGE('',*,*,#292,.T.);
#1370=ORIENTED_EDGE('',*,*,#1279,.T.);
#1371=ORIENTED_EDGE('',*,*,#41,.F.);
#1372=EDGE_LOOP('',(#1369,#1370,#1371));
#1373=FACE_BOUND('',#1372,.T.);
#1374=ADVANCED_FACE('F179',(#1373),#1344,.T.);
#1375=ORIENTED_EDGE('',*,*,#486,.T.);
#1376=ORIENTED_EDGE('',*,*,#294,.T.);
#1377=ORIENTED_EDGE('',*,*,#37,.F.);
#1378=EDGE_LOOP('',(#1375,#1376,#1377));
#1379=FACE_BOUND('',#1378,.T.);
#1380=ADVANCED_FACE('F483',(#1379),#1344,.T.);
#1381=CARTESIAN_POINT('',(0.,0.,-18.55));
#1382=DIRECTION('',(0.,0.,1.));
#1383=DIRECTION('',(1.,0.,0.));
#1384=AXIS2_PLACEMENT_3D('',#1381,#1382,#1383);
#1385=TOROIDAL_SURFACE('',#1384,19.95,1.45);
#1386=CARTESIAN_POINT('',(0.,0.,-17.2358537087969));
#1387=DIRECTION('',(0.,0.,1.));
#1388=DIRECTION('',(1.,0.,0.));
#1389=AXIS2_PLACEMENT_3D('',#1386,#1387,#1388);
#1390=CIRCLE('',#1389,20.562796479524);
#1391=CARTESIAN_POINT('',(20.562796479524,0.,-17.2358537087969));
#1392=VERTEX_POINT('',#1391);
#1393=EDGE_CURVE('E338',#1392,#1392,#1390,.T.);
#1394=ORIENTED_EDGE('',*,*,#1393,.F.);
#1395=EDGE_LOOP('',(#1394));
#1396=FACE_BOUND('',#1395,.T.);
#1397=ORIENTED_EDGE('',*,*,#1307,.T.);
#1398=EDGE_LOOP('',(#1397));
#1399=FACE_BOUND('',#1398,.T.);
#1400=ADVANCED_FACE('F183',(#1396,#1399),#1385,.T.);
#1401=CARTESIAN_POINT('',(0.,0.,-17.2358537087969));
#1402=DIRECTION('',(0.,0.,-1.));
#1403=DIRECTION('',(-1.,0.,0.));
#1404=AXIS2_PLACEMENT_3D('',#1401,#1402,#1403);
#1405=CONICAL_SURFACE('',#1404,20.562796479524,1.13446401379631);
#1406=CARTESIAN_POINT('',(-12.9671089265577,15.8078998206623,-17.1813529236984));
#1407=CARTESIAN_POINT('',(-12.4290222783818,15.801431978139,-17.0199394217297));
#1408=CARTESIAN_POINT('',(-11.8899101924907,15.7948389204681,-16.8638803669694));
#1409=CARTESIAN_POINT('',(-10.8093495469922,15.7815927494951,-16.5647253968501));
#1410=CARTESIAN_POINT('',(-10.2679002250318,15.7749396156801,-16.4216341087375));
#1411=CARTESIAN_POINT('',(-9.18051102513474,15.7617412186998,-16.1502251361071));
#1412=CARTESIAN_POINT('',(-8.63456183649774,15.7551965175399,-16.0219712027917));
#1413=CARTESIAN_POINT('',(-7.54046424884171,15.7425360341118,-15.7836589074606));
#1414=CARTESIAN_POINT('',(-6.9923160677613,15.736420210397,-15.6735987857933));
#1415=CARTESIAN_POINT('',(-5.90876260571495,15.7251309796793,-15.4772198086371));
#1416=CARTESIAN_POINT('',(-5.3734137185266,15.7199365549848,-15.390339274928));
#1417=CARTESIAN_POINT('',(-4.30098790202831,15.7106621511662,-15.23909483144));
#1418=CARTESIAN_POINT('',(-3.76391096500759,15.7065821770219,-15.1747310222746));
#1419=CARTESIAN_POINT('',(-2.68956237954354,15.6998919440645,-15.0708596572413));
#1420=CARTESIAN_POINT('',(-2.1522933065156,15.697278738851,-15.031302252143));
#1421=CARTESIAN_POINT('',(-1.07708307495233,15.6937624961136,-14.9783646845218));
#1422=CARTESIAN_POINT('',(-0.539141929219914,15.6928594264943,-14.9649840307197));
#1423=CARTESIAN_POINT('',(0.535676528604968,15.6928567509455,-14.9649443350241));
#1424=CARTESIAN_POINT('',(1.07255384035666,15.6937535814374,-14.978232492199));
#1425=CARTESIAN_POINT('',(2.14564108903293,15.6972511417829,-15.0308848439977));
#1426=CARTESIAN_POINT('',(2.68185101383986,15.699851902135,-15.0702495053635));
#1427=CARTESIAN_POINT('',(3.75408305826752,15.7065130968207,-15.1736472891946));
#1428=CARTESIAN_POINT('',(4.29010262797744,15.7105764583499,-15.2377298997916));
#1429=CARTESIAN_POINT('',(5.36042338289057,15.7198159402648,-15.3883406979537));
#1430=CARTESIAN_POINT('',(5.89472457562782,15.7249920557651,-15.4748687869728));
#1431=CARTESIAN_POINT('',(6.97613131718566,15.7362442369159,-15.6704723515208));
#1432=CARTESIAN_POINT('',(7.52318087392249,15.7423412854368,-15.780106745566));
#1433=CARTESIAN_POINT('',(8.61509095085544,15.754966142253,-16.0175247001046));
#1434=CARTESIAN_POINT('',(9.15995125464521,15.761493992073,-16.1453100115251));
#1435=CARTESIAN_POINT('',(10.2451867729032,15.7746616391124,-16.4157573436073));
#1436=CARTESIAN_POINT('',(10.7855712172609,15.781300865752,-16.5583560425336));
#1437=CARTESIAN_POINT('',(11.8640100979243,15.7945220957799,-16.8565072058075));
#1438=CARTESIAN_POINT('',(12.4020652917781,15.8011041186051,-17.0120550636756));
#1439=CARTESIAN_POINT('',(12.9390978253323,15.8075624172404,-17.1729525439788));
#1440=B_SPLINE_CURVE_WITH_KNOTS('',3,(#1406,#1407,#1408,#1409,#1410,#1411,#1412,#1413,#1414,
#1415,#1416,#1417,#1418,#1419,#1420,#1421,#1422,#1423,#1424,#1425,#1426,#1427,#1428,#1429,#1430,
#1431,#1432,#1433,#1434,#1435,#1436,#1437,#1438,#1439),.UNSPECIFIED.,.F.,.F.,(4,2,2,2,2,2,2,2,2,
2,2,2,2,2,2,2,4),(0.,1.70808693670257,3.416780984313,5.13256358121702,6.84818013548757,
8.51738846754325,10.1866042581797,11.8524548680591,13.5182742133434,15.1807986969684,
16.8433529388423,18.5092532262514,20.1751461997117,21.8872546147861,23.5995283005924,
25.3047624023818,27.0093924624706),.UNSPECIFIED.);
#1441=CARTESIAN_POINT('',(-9.09950340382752,15.7608022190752,-16.1336004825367));
#1442=VERTEX_POINT('',#1441);
#1443=CARTESIAN_POINT('',(9.09950340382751,15.7608022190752,-16.1336004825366));
#1444=VERTEX_POINT('',#1443);
#1445=EDGE_CURVE('E415',#1442,#1444,#1440,.T.);
#1446=ORIENTED_EDGE('',*,*,#1445,.T.);
#1447=CARTESIAN_POINT('',(7.2368422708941,19.0797270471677,-17.1627729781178));
#1448=CARTESIAN_POINT('',(7.49981402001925,18.6113201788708,-17.0020875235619));
#1449=CARTESIAN_POINT('',(7.76319186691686,18.1419645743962,-16.8467728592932));
#1450=CARTESIAN_POINT('',(8.29106741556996,17.201206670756,-16.5491377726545));
#1451=CARTESIAN_POINT('',(8.55556548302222,16.7298037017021,-16.4068220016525));
#1452=CARTESIAN_POINT('',(9.08689005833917,15.7831972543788,-16.1370026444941));
#1453=CARTESIAN_POINT('',(9.3537216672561,15.307986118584,-16.0095622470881));
#1454=CARTESIAN_POINT('',(9.88885816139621,14.3558878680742,-15.7728974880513));
#1455=CARTESIAN_POINT('',(10.1571629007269,13.87900092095,-15.6636713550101));
#1456=CARTESIAN_POINT('',(10.6882635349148,12.936667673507,-15.4689312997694));
#1457=CARTESIAN_POINT('',(10.9510132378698,12.4712590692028,-15.3828580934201));
#1458=CARTESIAN_POINT('',(11.4783392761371,11.5395205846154,-15.2332187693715));
#1459=CARTESIAN_POINT('',(11.7429156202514,11.0731906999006,-15.1696527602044));
#1460=CARTESIAN_POINT('',(12.2734380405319,10.1411041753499,-15.0673373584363));
#1461=CARTESIAN_POINT('',(12.5393803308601,9.67534824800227,-15.028538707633));
#1462=CARTESIAN_POINT('',(13.0730709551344,8.74412553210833,-14.9770517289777));
#1463=CARTESIAN_POINT('',(13.3408192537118,8.27865873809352,-14.9643628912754));
#1464=CARTESIAN_POINT('',(13.8756619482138,7.35245057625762,-14.9656042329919));
#1465=CARTESIAN_POINT('',(14.1427437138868,6.89170174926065,-14.9793170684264));
#1466=CARTESIAN_POINT('',(14.6780229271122,5.97161873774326,-15.0323834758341));
#1467=CARTESIAN_POINT('',(14.9462203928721,5.51228457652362,-15.0717374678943));
#1468=CARTESIAN_POINT('',(15.4837562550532,4.59450743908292,-15.1747024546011));
#1469=CARTESIAN_POINT('',(15.7530958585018,4.13606800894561,-15.2383611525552));
#1470=CARTESIAN_POINT('',(16.2918779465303,3.2212005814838,-15.3877628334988));
#1471=CARTESIAN_POINT('',(16.5613204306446,2.76477257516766,-15.4735057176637));
#1472=CARTESIAN_POINT('',(17.1072560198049,1.8414800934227,-15.6671862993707));
#1473=CARTESIAN_POINT('',(17.3837396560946,1.37467302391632,-15.7756685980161));
#1474=CARTESIAN_POINT('',(17.9360023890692,0.443136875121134,-16.0105249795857));
#1475=CARTESIAN_POINT('',(18.2117814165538,-0.0215920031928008,-16.1369007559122));
#1476=CARTESIAN_POINT('',(18.7612464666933,-0.94719155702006,-16.4043512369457));
#1477=CARTESIAN_POINT('',(19.0349364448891,-1.40807023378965,-16.5453646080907));
#1478=CARTESIAN_POINT('',(19.5811259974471,-2.32786719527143,-16.8402033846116));
#1479=CARTESIAN_POINT('',(19.8536259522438,-2.78678610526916,-16.9940243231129));
#1480=CARTESIAN_POINT('',(20.1255182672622,-3.24489093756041,-17.1531468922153));
#1481=B_SPLINE_CURVE_WITH_KNOTS('',3,(#1447,#1448,#1449,#1450,#1451,#1452,#1453,#1454,#1455,
#1456,#1457,#1458,#1459,#1460,#1461,#1462,#1463,#1464,#1465,#1466,#1467,#1468,#1469,#1470,#1471,
#1472,#1473,#1474,#1475,#1476,#1477,#1478,#1479,#1480),.UNSPECIFIED.,.F.,.F.,(4,2,2,2,2,2,2,2,2,
2,2,2,2,2,2,2,4),(0.,1.70483078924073,3.41026924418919,5.1227070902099,6.83497829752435,
8.50114497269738,10.1673196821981,11.8301702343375,13.4929883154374,15.1421762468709,
16.7913911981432,18.4438598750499,20.0963211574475,21.7941388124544,23.492117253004,
25.1832480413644,26.8737914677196),.UNSPECIFIED.);
#1482=CARTESIAN_POINT('',(18.199006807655,0.,-16.1336004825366));
#1483=VERTEX_POINT('',#1482);
#1484=EDGE_CURVE('E414',#1444,#1483,#1481,.T.);
#1485=ORIENTED_EDGE('',*,*,#1484,.T.);
#1486=CARTESIAN_POINT('',(20.1419494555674,3.2725742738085,-17.1627729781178));
#1487=CARTESIAN_POINT('',(19.8677830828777,2.81063062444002,-17.0020875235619));
#1488=CARTESIAN_POINT('',(19.5929981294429,2.34786091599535,-16.8467728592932));
#1489=CARTESIAN_POINT('',(19.042215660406,1.42032832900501,-16.5491377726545));
#1490=CARTESIAN_POINT('',(18.7662177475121,0.955564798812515,-16.4068220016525));
#1491=CARTESIAN_POINT('',(18.2120948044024,0.0221209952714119,-16.1370026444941));
#1492=CARTESIAN_POINT('',(17.9339656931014,-0.446567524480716,-16.0095622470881));
#1493=CARTESIAN_POINT('',(17.3769926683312,-1.38605844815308,-15.7728974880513));
#1494=CARTESIAN_POINT('',(17.0981488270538,-1.85686064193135,-15.6636713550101));
#1495=CARTESIAN_POINT('',(16.5476146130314,-2.78797390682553,-15.4689312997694));
#1496=CARTESIAN_POINT('',(16.2759337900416,-3.24822612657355,-15.3828580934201));
#1497=CARTESIAN_POINT('',(15.7326876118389,-4.17077311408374,-15.2332187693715));
#1498=CARTESIAN_POINT('',(15.4611222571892,-4.63306789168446,-15.1696527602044));
#1499=CARTESIAN_POINT('',(14.9191728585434,-5.55855704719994,-15.0673373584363));
#1500=CARTESIAN_POINT('',(14.6487875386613,-6.02174779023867,-15.028538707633));
#1501=CARTESIAN_POINT('',(14.1091703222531,-6.94954878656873,-14.9770517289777));
#1502=CARTESIAN_POINT('',(13.8399384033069,-7.41415901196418,-14.9643628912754));
#1503=CARTESIAN_POINT('',(13.3052399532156,-8.34045045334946,-14.9656042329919));
#1504=CARTESIAN_POINT('',(13.0397606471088,-8.80212446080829,-14.9793170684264));
#1505=CARTESIAN_POINT('',(12.5105849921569,-9.72573136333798,-15.0323834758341));
#1506=CARTESIAN_POINT('',(12.2468886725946,-10.1876642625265,-15.0717374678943));
#1507=CARTESIAN_POINT('',(11.720838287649,-11.1120725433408,-15.1747024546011));
#1508=CARTESIAN_POINT('',(11.4584878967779,-11.5745471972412,-15.2383611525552));
#1509=CARTESIAN_POINT('',(10.9355805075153,-12.4985798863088,-15.3877628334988));
#1510=CARTESIAN_POINT('',(10.675023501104,-12.9601379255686,-15.4735057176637));
#1511=CARTESIAN_POINT('',(10.1483965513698,-13.894578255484,-15.6671862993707));
#1512=CARTESIAN_POINT('',(9.88237158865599,-14.3674236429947,-15.7756685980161));
#1513=CARTESIAN_POINT('',(9.35176898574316,-15.3114652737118,-16.0105249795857));
#1514=CARTESIAN_POINT('',(9.08719148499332,-15.7826613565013,-16.1369007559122));
#1515=CARTESIAN_POINT('',(8.56033128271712,-16.7213118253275,-16.4043512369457));
#1516=CARTESIAN_POINT('',(8.29804362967,-17.188773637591,-16.5453646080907));
#1517=CARTESIAN_POINT('',(7.77457087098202,-18.1216861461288,-16.8402033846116));
#1518=CARTESIAN_POINT('',(7.5133854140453,-18.5871374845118,-16.9940243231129));
#1519=CARTESIAN_POINT('',(7.25260114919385,-19.0516555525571,-17.1531468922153));
#1520=B_SPLINE_CURVE_WITH_KNOTS('',3,(#1486,#1487,#1488,#1489,#1490,#1491,#1492,#1493,#1494,
#1495,#1496,#1497,#1498,#1499,#1500,#1501,#1502,#1503,#1504,#1505,#1506,#1507,#1508,#1509,#1510,
#1511,#1512,#1513,#1514,#1515,#1516,#1517,#1518,#1519),.UNSPECIFIED.,.F.,.F.,(4,2,2,2,2,2,2,2,2,
2,2,2,2,2,2,2,4),(0.,1.70483078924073,3.41026924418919,5.12270709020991,6.83497829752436,
8.50114497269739,10.1673196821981,11.8301702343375,13.4929883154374,15.1421762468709,
16.7913911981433,18.4438598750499,20.0963211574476,21.7941388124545,23.492117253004,
25.1832480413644,26.8737914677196),.UNSPECIFIED.);
#1521=CARTESIAN_POINT('',(9.09950340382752,-15.7608022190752,-16.1336004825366));
#1522=VERTEX_POINT('',#1521);
#1523=EDGE_CURVE('E406',#1483,#1522,#1520,.T.);
#1524=ORIENTED_EDGE('',*,*,#1523,.T.);
#1525=CARTESIAN_POINT('',(12.9632889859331,-15.8078538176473,-17.1802067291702));
#1526=CARTESIAN_POINT('',(12.4252609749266,-15.8013862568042,-17.0188381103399));
#1527=CARTESIAN_POINT('',(11.8862075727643,-15.7947936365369,-16.8628249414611));
#1528=CARTESIAN_POINT('',(10.8057645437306,-15.7815487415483,-16.5637636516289));
#1529=CARTESIAN_POINT('',(10.2643741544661,-15.7748964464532,-16.4207201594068));
#1530=CARTESIAN_POINT('',(9.17710497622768,-15.7617002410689,-16.1494091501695));
#1531=CARTESIAN_POINT('',(8.63121688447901,-15.7551568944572,-16.0212053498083));
#1532=CARTESIAN_POINT('',(7.53724217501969,-15.7424996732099,-15.7829945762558));
#1533=CARTESIAN_POINT('',(6.98915577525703,-15.73638575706,-15.6729858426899));
#1534=CARTESIAN_POINT('',(5.90572090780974,-15.7251007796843,-15.4767078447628));
#1535=CARTESIAN_POINT('',(5.37042879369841,-15.7199086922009,-15.3898770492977));
#1536=CARTESIAN_POINT('',(4.29811756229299,-15.7106393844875,-15.2387314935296));
#1537=CARTESIAN_POINT('',(3.76109843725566,-15.7065621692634,-15.1744168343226));
#1538=CARTESIAN_POINT('',(2.68686586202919,-15.699877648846,-15.0706413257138));
#1539=CARTESIAN_POINT('',(2.14965498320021,-15.6972673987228,-15.0311306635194));
#1540=CARTESIAN_POINT('',(1.07456234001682,-15.693756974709,-14.9782824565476));
#1541=CARTESIAN_POINT('',(0.536680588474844,-15.6928567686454,-14.9649444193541));
#1542=CARTESIAN_POINT('',(-0.537814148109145,-15.6928594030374,-14.9649838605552));
#1543=CARTESIAN_POINT('',(-1.07442713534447,-15.6937579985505,-14.9782984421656));
#1544=CARTESIAN_POINT('',(-2.14698572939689,-15.6972572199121,-15.0309768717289));
#1545=CARTESIAN_POINT('',(-2.68293132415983,-15.6998578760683,-15.0703411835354));
#1546=CARTESIAN_POINT('',(-3.75463386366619,-15.706517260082,-15.1737129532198));
#1547=CARTESIAN_POINT('',(-4.29038826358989,-15.7105789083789,-15.2377697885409));
#1548=CARTESIAN_POINT('',(-5.36018039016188,-15.7198138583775,-15.38830680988));
#1549=CARTESIAN_POINT('',(-5.89421812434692,-15.724987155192,-15.4747868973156));
#1550=CARTESIAN_POINT('',(-6.97508313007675,-15.7362329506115,-15.670272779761));
#1551=CARTESIAN_POINT('',(-7.5218545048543,-15.7423264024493,-15.7798366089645));
#1552=CARTESIAN_POINT('',(-8.61321050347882,-15.7549439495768,-16.0170976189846));
#1553=CARTESIAN_POINT('',(-9.15779491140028,-15.7614680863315,-16.1447965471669));
#1554=CARTESIAN_POINT('',(-10.2424846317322,-15.7746285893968,-16.4150602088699));
#1555=CARTESIAN_POINT('',(-10.7825991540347,-15.7812643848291,-16.5575617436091));
#1556=CARTESIAN_POINT('',(-11.8605004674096,-15.7944791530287,-16.8555098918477));
#1557=CARTESIAN_POINT('',(-12.3982880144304,-15.8010581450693,-17.010951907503));
#1558=CARTESIAN_POINT('',(-12.9350537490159,-15.8075136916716,-17.1717406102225));
#1559=B_SPLINE_CURVE_WITH_KNOTS('',3,(#1525,#1526,#1527,#1528,#1529,#1530,#1531,#1532,#1533,
#1534,#1535,#1536,#1537,#1538,#1539,#1540,#1541,#1542,#1543,#1544,#1545,#1546,#1547,#1548,#1549,
#1550,#1551,#1552,#1553,#1554,#1555,#1556,#1557,#1558),.UNSPECIFIED.,.F.,.F.,(4,2,2,2,2,2,2,2,2,
2,2,2,2,2,2,2,4),(0.,1.70788568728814,3.41637852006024,5.13195440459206,6.84736420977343,
8.51638451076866,10.1854123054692,11.8510774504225,13.516711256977,15.1784190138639,
16.8401563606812,18.5052340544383,20.1703044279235,21.8815373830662,23.5929353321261,
25.2973055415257,27.0010727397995),.UNSPECIFIED.);
#1560=CARTESIAN_POINT('',(-9.09950340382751,-15.7608022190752,-16.1336004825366));
#1561=VERTEX_POINT('',#1560);
#1562=EDGE_CURVE('E710',#1522,#1561,#1559,.T.);
#1563=ORIENTED_EDGE('',*,*,#1562,.T.);
#1564=CARTESIAN_POINT('',(-7.23684227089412,-19.0797270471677,-17.1627729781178));
#1565=CARTESIAN_POINT('',(-7.49981402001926,-18.6113201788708,-17.0020875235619));
#1566=CARTESIAN_POINT('',(-7.76319186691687,-18.1419645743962,-16.8467728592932));
#1567=CARTESIAN_POINT('',(-8.29106741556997,-17.201206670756,-16.5491377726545));
#1568=CARTESIAN_POINT('',(-8.55556548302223,-16.7298037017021,-16.4068220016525));
#1569=CARTESIAN_POINT('',(-9.08689005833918,-15.7831972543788,-16.1370026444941));
#1570=CARTESIAN_POINT('',(-9.35372166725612,-15.307986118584,-16.0095622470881));
#1571=CARTESIAN_POINT('',(-9.88885816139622,-14.3558878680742,-15.7728974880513));
#1572=CARTESIAN_POINT('',(-10.1571629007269,-13.87900092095,-15.6636713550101));
#1573=CARTESIAN_POINT('',(-10.6882635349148,-12.936667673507,-15.4689312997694));
#1574=CARTESIAN_POINT('',(-10.9510132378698,-12.4712590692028,-15.3828580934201));
#1575=CARTESIAN_POINT('',(-11.4783392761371,-11.5395205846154,-15.2332187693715));
#1576=CARTESIAN_POINT('',(-11.7429156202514,-11.0731906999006,-15.1696527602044));
#1577=CARTESIAN_POINT('',(-12.2734380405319,-10.1411041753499,-15.0673373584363));
#1578=CARTESIAN_POINT('',(-12.5393803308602,-9.67534824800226,-15.028538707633));
#1579=CARTESIAN_POINT('',(-13.0730709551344,-8.74412553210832,-14.9770517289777));
#1580=CARTESIAN_POINT('',(-13.3408192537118,-8.27865873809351,-14.9643628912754));
#1581=CARTESIAN_POINT('',(-13.8756619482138,-7.35245057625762,-14.9656042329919));
#1582=CARTESIAN_POINT('',(-14.1427437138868,-6.89170174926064,-14.9793170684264));
#1583=CARTESIAN_POINT('',(-14.6780229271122,-5.97161873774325,-15.0323834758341));
#1584=CARTESIAN_POINT('',(-14.9462203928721,-5.51228457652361,-15.0717374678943));
#1585=CARTESIAN_POINT('',(-15.4837562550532,-4.59450743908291,-15.1747024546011));
#1586=CARTESIAN_POINT('',(-15.7530958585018,-4.1360680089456,-15.2383611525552));
#1587=CARTESIAN_POINT('',(-16.2918779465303,-3.22120058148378,-15.3877628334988));
#1588=CARTESIAN_POINT('',(-16.5613204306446,-2.76477257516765,-15.4735057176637));
#1589=CARTESIAN_POINT('',(-17.1072560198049,-1.84148009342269,-15.6671862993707));
#1590=CARTESIAN_POINT('',(-17.3837396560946,-1.3746730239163,-15.7756685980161));
#1591=CARTESIAN_POINT('',(-17.9360023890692,-0.443136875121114,-16.0105249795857));
#1592=CARTESIAN_POINT('',(-18.2117814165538,0.0215920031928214,-16.1369007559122));
#1593=CARTESIAN_POINT('',(-18.7612464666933,0.947191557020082,-16.4043512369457));
#1594=CARTESIAN_POINT('',(-19.0349364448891,1.40807023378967,-16.5453646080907));
#1595=CARTESIAN_POINT('',(-19.5811259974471,2.32786719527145,-16.8402033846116));
#1596=CARTESIAN_POINT('',(-19.8536259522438,2.78678610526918,-16.9940243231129));
#1597=CARTESIAN_POINT('',(-20.1255182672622,3.24489093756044,-17.1531468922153));
#1598=B_SPLINE_CURVE_WITH_KNOTS('',3,(#1564,#1565,#1566,#1567,#1568,#1569,#1570,#1571,#1572,
#1573,#1574,#1575,#1576,#1577,#1578,#1579,#1580,#1581,#1582,#1583,#1584,#1585,#1586,#1587,#1588,
#1589,#1590,#1591,#1592,#1593,#1594,#1595,#1596,#1597),.UNSPECIFIED.,.F.,.F.,(4,2,2,2,2,2,2,2,2,
2,2,2,2,2,2,2,4),(0.,1.70483078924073,3.4102692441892,5.1227070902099,6.83497829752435,
8.50114497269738,10.1673196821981,11.8301702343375,13.4929883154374,15.1421762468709,
16.7913911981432,18.4438598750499,20.0963211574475,21.7941388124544,23.492117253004,
25.1832480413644,26.8737914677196),.UNSPECIFIED.);
#1599=CARTESIAN_POINT('',(-18.199006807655,0.,-16.1336004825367));
#1600=VERTEX_POINT('',#1599);
#1601=EDGE_CURVE('E716',#1561,#1600,#1598,.T.);
#1602=ORIENTED_EDGE('',*,*,#1601,.T.);
#1603=CARTESIAN_POINT('',(-20.1419494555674,-3.27257427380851,-17.1627729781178));
#1604=CARTESIAN_POINT('',(-19.8677830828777,-2.81063062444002,-17.0020875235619));
#1605=CARTESIAN_POINT('',(-19.5929981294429,-2.34786091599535,-16.8467728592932));
#1606=CARTESIAN_POINT('',(-19.042215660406,-1.42032832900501,-16.5491377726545));
#1607=CARTESIAN_POINT('',(-18.7662177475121,-0.955564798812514,-16.4068220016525));
#1608=CARTESIAN_POINT('',(-18.2120948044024,-0.0221209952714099,-16.1370026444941));
#1609=CARTESIAN_POINT('',(-17.9339656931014,0.446567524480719,-16.0095622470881));
#1610=CARTESIAN_POINT('',(-17.3769926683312,1.38605844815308,-15.7728974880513));
#1611=CARTESIAN_POINT('',(-17.0981488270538,1.85686064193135,-15.6636713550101));
#1612=CARTESIAN_POINT('',(-16.5476146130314,2.78797390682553,-15.4689312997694));
#1613=CARTESIAN_POINT('',(-16.2759337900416,3.24822612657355,-15.3828580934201));
#1614=CARTESIAN_POINT('',(-15.732687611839,4.17077311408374,-15.2332187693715));
#1615=CARTESIAN_POINT('',(-15.4611222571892,4.63306789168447,-15.1696527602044));
#1616=CARTESIAN_POINT('',(-14.9191728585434,5.55855704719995,-15.0673373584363));
#1617=CARTESIAN_POINT('',(-14.6487875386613,6.02174779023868,-15.028538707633));
#1618=CARTESIAN_POINT('',(-14.1091703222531,6.94954878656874,-14.9770517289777));
#1619=CARTESIAN_POINT('',(-13.8399384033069,7.41415901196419,-14.9643628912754));
#1620=CARTESIAN_POINT('',(-13.3052399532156,8.34045045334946,-14.9656042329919));
#1621=CARTESIAN_POINT('',(-13.0397606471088,8.8021244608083,-14.9793170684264));
#1622=CARTESIAN_POINT('',(-12.5105849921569,9.72573136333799,-15.0323834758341));
#1623=CARTESIAN_POINT('',(-12.2468886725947,10.1876642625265,-15.0717374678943));
#1624=CARTESIAN_POINT('',(-11.720838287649,11.1120725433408,-15.1747024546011));
#1625=CARTESIAN_POINT('',(-11.4584878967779,11.5745471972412,-15.2383611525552));
#1626=CARTESIAN_POINT('',(-10.9355805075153,12.4985798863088,-15.3877628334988));
#1627=CARTESIAN_POINT('',(-10.675023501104,12.9601379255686,-15.4735057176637));
#1628=CARTESIAN_POINT('',(-10.1483965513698,13.894578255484,-15.6671862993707));
#1629=CARTESIAN_POINT('',(-9.88237158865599,14.3674236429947,-15.7756685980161));
#1630=CARTESIAN_POINT('',(-9.35176898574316,15.3114652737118,-16.0105249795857));
#1631=CARTESIAN_POINT('',(-9.08719148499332,15.7826613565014,-16.1369007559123));
#1632=CARTESIAN_POINT('',(-8.56033128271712,16.7213118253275,-16.4043512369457));
#1633=CARTESIAN_POINT('',(-8.29804362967,17.1887736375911,-16.5453646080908));
#1634=CARTESIAN_POINT('',(-7.77457087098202,18.1216861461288,-16.8402033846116));
#1635=CARTESIAN_POINT('',(-7.5133854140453,18.5871374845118,-16.9940243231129));
#1636=CARTESIAN_POINT('',(-7.25260114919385,19.0516555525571,-17.1531468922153));
#1637=B_SPLINE_CURVE_WITH_KNOTS('',3,(#1603,#1604,#1605,#1606,#1607,#1608,#1609,#1610,#1611,
#1612,#1613,#1614,#1615,#1616,#1617,#1618,#1619,#1620,#1621,#1622,#1623,#1624,#1625,#1626,#1627,
#1628,#1629,#1630,#1631,#1632,#1633,#1634,#1635,#1636),.UNSPECIFIED.,.F.,.F.,(4,2,2,2,2,2,2,2,2,
2,2,2,2,2,2,2,4),(0.,1.70483078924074,3.4102692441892,5.12270709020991,6.83497829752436,
8.50114497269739,10.1673196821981,11.8301702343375,13.4929883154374,15.1421762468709,
16.7913911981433,18.4438598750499,20.0963211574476,21.7941388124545,23.492117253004,
25.1832480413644,26.8737914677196),.UNSPECIFIED.);
#1638=EDGE_CURVE('E725',#1600,#1442,#1637,.T.);
#1639=ORIENTED_EDGE('',*,*,#1638,.T.);
#1640=EDGE_LOOP('',(#1446,#1485,#1524,#1563,#1602,#1639));
#1641=FACE_BOUND('',#1640,.T.);
#1642=ORIENTED_EDGE('',*,*,#1393,.T.);
#1643=EDGE_LOOP('',(#1642));
#1644=FACE_BOUND('',#1643,.T.);
#1645=ADVANCED_FACE('F245',(#1641,#1644),#1405,.T.);
#1646=CARTESIAN_POINT('',(-8.66025403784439,15.,-14.889067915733));
#1647=CARTESIAN_POINT('',(-8.66025308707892,14.9999983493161,-14.9235025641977));
#1648=CARTESIAN_POINT('',(-8.66107063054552,15.0014143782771,-14.9579107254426));
#1649=CARTESIAN_POINT('',(-8.664272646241,15.0069604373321,-15.0264047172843));
#1650=CARTESIAN_POINT('',(-8.66665570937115,15.0110880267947,-15.0604908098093));
#1651=CARTESIAN_POINT('',(-8.67600621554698,15.0272835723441,-15.1614766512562));
#1652=CARTESIAN_POINT('',(-8.68517707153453,15.0431679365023,-15.2275979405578));
#1653=CARTESIAN_POINT('',(-8.70865909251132,15.0838400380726,-15.3557315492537));
#1654=CARTESIAN_POINT('',(-8.72295279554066,15.1085975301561,-15.4177569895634));
#1655=CARTESIAN_POINT('',(-8.75598425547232,15.1658096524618,-15.5369883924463));
#1656=CARTESIAN_POINT('',(-8.7747303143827,15.1982786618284,-15.5941850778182));
#1657=CARTESIAN_POINT('',(-8.81858127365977,15.2742308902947,-15.7097176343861));
#1658=CARTESIAN_POINT('',(-8.84418985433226,15.3185865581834,-15.767288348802));
#1659=CARTESIAN_POINT('',(-8.89926275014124,15.4139756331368,-15.8743388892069));
#1660=CARTESIAN_POINT('',(-8.92872576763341,15.4650067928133,-15.9238214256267));
#1661=CARTESIAN_POINT('',(-9.00259082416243,15.5929445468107,-16.0313023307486));
#1662=CARTESIAN_POINT('',(-9.04843244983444,15.6723447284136,-16.0854590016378));
#1663=CARTESIAN_POINT('',(-9.09732726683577,15.7570330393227,-16.1315653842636));
#1664=CARTESIAN_POINT('',(-9.09841483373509,15.7589167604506,-16.1325852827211));
#1665=CARTESIAN_POINT('',(-9.09950340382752,15.7608022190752,-16.1336004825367));
#1666=B_SPLINE_CURVE_WITH_KNOTS('',3,(#1646,#1647,#1648,#1649,#1650,#1651,#1652,#1653,#1654,
#1655,#1656,#1657,#1658,#1659,#1660,#1661,#1662,#1663,#1664,#1665),.UNSPECIFIED.,.F.,.F.,(4,2,2,
2,2,2,2,2,2,4),(0.,0.103218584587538,0.206344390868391,0.411135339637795,0.615234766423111,
0.81971779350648,1.04997553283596,1.28015595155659,1.59726820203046,1.60447529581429),.UNSPECIFIED.);
#1667=EDGE_CURVE('E309',#1442,#503,#1666,.F.);
#1668=ORIENTED_EDGE('',*,*,#1667,.F.);
#1669=ORIENTED_EDGE('',*,*,#1638,.F.);
#1670=CARTESIAN_POINT('',(-17.3205080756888,0.,-14.889067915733));
#1671=CARTESIAN_POINT('',(-17.3205061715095,-5.36734676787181E-11,-14.9235025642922));
#1672=CARTESIAN_POINT('',(-17.3221412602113,5.28733306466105E-10,-14.9579107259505));
#1673=CARTESIAN_POINT('',(-17.3285452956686,1.686031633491E-09,-15.0264047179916));
#1674=CARTESIAN_POINT('',(-17.3333114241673,2.26092947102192E-09,-15.0604908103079));
#1675=CARTESIAN_POINT('',(-17.3520124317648,2.06250756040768E-09,-15.1614766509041));
#1676=CARTESIAN_POINT('',(-17.3703541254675,-5.98661377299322E-10,-15.2275979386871));
#1677=CARTESIAN_POINT('',(-17.4173182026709,5.96657427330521E-10,-15.3557315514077));
#1678=CARTESIAN_POINT('',(-17.4459056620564,4.43116723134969E-09,-15.4177569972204));
#1679=CARTESIAN_POINT('',(-17.511968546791,5.41707598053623E-09,-15.5369883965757));
#1680=CARTESIAN_POINT('',(-17.5494605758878,2.55590062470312E-09,-15.5941850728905));
#1681=CARTESIAN_POINT('',(-17.6371626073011,-2.87805472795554E-09,-15.7097176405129));
#1682=CARTESIAN_POINT('',(-17.6883800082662,-5.36902424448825E-09,-15.7672883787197));
#1683=CARTESIAN_POINT('',(-17.7985258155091,-4.5982035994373E-09,-15.8743389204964));
#1684=CARTESIAN_POINT('',(-17.8574516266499,-1.33834493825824E-09,-15.9238214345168));
#1685=CARTESIAN_POINT('',(-18.0051815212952,1.84381530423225E-09,-16.0313023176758));
#1686=CARTESIAN_POINT('',(-18.0968648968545,4.06633334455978E-11,-16.0854590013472));
#1687=CARTESIAN_POINT('',(-18.1946545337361,-9.37587604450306E-13,-16.1315653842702));
#1688=CARTESIAN_POINT('',(-18.196829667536,-9.51683291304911E-13,-16.1325852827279));
#1689=CARTESIAN_POINT('',(-18.199006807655,0.,-16.1336004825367));
#1690=B_SPLINE_CURVE_WITH_KNOTS('',3,(#1670,#1671,#1672,#1673,#1674,#1675,#1676,#1677,#1678,
#1679,#1680,#1681,#1682,#1683,#1684,#1685,#1686,#1687,#1688,#1689),.UNSPECIFIED.,.F.,.F.,(4,2,2,
2,2,2,2,2,2,4),(0.,0.103218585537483,0.206344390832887,0.41113533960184,0.615234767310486,
0.819717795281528,1.04997553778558,1.2801559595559,1.59726821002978,1.60447530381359),.UNSPECIFIED.);
#1691=EDGE_CURVE('E329',#309,#1600,#1690,.T.);
#1692=ORIENTED_EDGE('',*,*,#1691,.F.);
#1693=ORIENTED_EDGE('',*,*,#646,.F.);
#1694=EDGE_LOOP('',(#1668,#1669,#1692,#1693));
#1695=FACE_BOUND('',#1694,.T.);
#1696=ADVANCED_FACE('F297',(#1695),#610,.F.);
#1697=ORIENTED_EDGE('',*,*,#1691,.T.);
#1698=ORIENTED_EDGE('',*,*,#1601,.F.);
#1699=CARTESIAN_POINT('',(-8.66025403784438,-15.,-14.889067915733));
#1700=CARTESIAN_POINT('',(-8.66025308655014,-14.9999983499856,-14.9235025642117));
#1701=CARTESIAN_POINT('',(-8.66107063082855,-15.0014143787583,-14.957910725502));
#1702=CARTESIAN_POINT('',(-8.66427264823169,-15.0069604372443,-15.0264047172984));
#1703=CARTESIAN_POINT('',(-8.66665571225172,-15.0110880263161,-15.0604908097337));
#1704=CARTESIAN_POINT('',(-8.6760062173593,-15.0272835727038,-15.1614766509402));
#1705=CARTESIAN_POINT('',(-8.68517706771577,-15.0431679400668,-15.2275979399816));
#1706=CARTESIAN_POINT('',(-8.7086590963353,-15.0838400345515,-15.355731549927));
#1707=CARTESIAN_POINT('',(-8.7229528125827,-15.1085975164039,-15.4177569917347));
#1708=CARTESIAN_POINT('',(-8.75598426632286,-15.1658096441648,-15.5369883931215));
#1709=CARTESIAN_POINT('',(-8.77473030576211,-15.1982786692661,-15.5941850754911));
#1710=CARTESIAN_POINT('',(-8.81858128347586,-15.2742308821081,-15.7097176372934));
#1711=CARTESIAN_POINT('',(-8.84418990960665,-15.3185865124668,-15.7672883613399));
#1712=CARTESIAN_POINT('',(-8.89926280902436,-15.4139755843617,-15.8743389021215));
#1713=CARTESIAN_POINT('',(-8.92872578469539,-15.4650067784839,-15.9238214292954));
#1714=CARTESIAN_POINT('',(-9.00259080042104,-15.5929445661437,-16.0313023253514));
#1715=CARTESIAN_POINT('',(-9.04843244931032,-15.6723447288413,-16.0854590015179));
#1716=CARTESIAN_POINT('',(-9.09732726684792,-15.7570330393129,-16.1315653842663));
#1717=CARTESIAN_POINT('',(-9.09841483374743,-15.7589167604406,-16.1325852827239));
#1718=CARTESIAN_POINT('',(-9.09950340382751,-15.7608022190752,-16.1336004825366));
#1719=B_SPLINE_CURVE_WITH_KNOTS('',3,(#1699,#1700,#1701,#1702,#1703,#1704,#1705,#1706,#1707,
#1708,#1709,#1710,#1711,#1712,#1713,#1714,#1715,#1716,#1717,#1718),.UNSPECIFIED.,.F.,.F.,(4,2,2,
2,2,2,2,2,2,4),(0.,0.103218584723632,0.206344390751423,0.41113533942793,0.615234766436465,
0.819717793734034,1.04997553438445,1.28015595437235,1.59726820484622,1.60447529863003),.UNSPECIFIED.);
#1720=EDGE_CURVE('E286',#82,#1561,#1719,.T.);
#1721=ORIENTED_EDGE('',*,*,#1720,.F.);
#1722=ORIENTED_EDGE('',*,*,#452,.F.);
#1723=EDGE_LOOP('',(#1697,#1698,#1721,#1722));
#1724=FACE_BOUND('',#1723,.T.);
#1725=ADVANCED_FACE('F272',(#1724),#416,.F.);
#1726=ORIENTED_EDGE('',*,*,#1667,.T.);
#1727=ORIENTED_EDGE('',*,*,#840,.F.);
#1728=CARTESIAN_POINT('',(8.66025403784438,15.,-14.889067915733));
#1729=CARTESIAN_POINT('',(8.66025308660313,14.9999983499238,-14.923502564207));
#1730=CARTESIAN_POINT('',(8.66107063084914,15.001414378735,-14.9579107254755));
#1731=CARTESIAN_POINT('',(8.6642726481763,15.0069604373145,-15.026404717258));
#1732=CARTESIAN_POINT('',(8.66665571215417,15.0110880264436,-15.060490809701));
#1733=CARTESIAN_POINT('',(8.6760062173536,15.0272835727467,-15.1614766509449));
#1734=CARTESIAN_POINT('',(8.68517706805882,15.0431679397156,-15.2275979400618));
#1735=CARTESIAN_POINT('',(8.70865909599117,15.0838400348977,-15.3557315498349));
#1736=CARTESIAN_POINT('',(8.72295281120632,15.108597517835,-15.4177569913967));
#1737=CARTESIAN_POINT('',(8.75598426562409,15.1658096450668,-15.5369883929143));
#1738=CARTESIAN_POINT('',(8.77473030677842,15.1982786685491,-15.5941850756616));
#1739=CARTESIAN_POINT('',(8.81858128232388,15.2742308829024,-15.7097176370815));
#1740=CARTESIAN_POINT('',(8.84418990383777,15.3185865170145,-15.7672883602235));
#1741=CARTESIAN_POINT('',(8.89926280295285,15.4139755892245,-15.8743389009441));
#1742=CARTESIAN_POINT('',(8.92872578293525,15.4650067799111,-15.9238214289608));
#1743=CARTESIAN_POINT('',(9.00259080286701,15.5929445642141,-16.0313023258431));
#1744=CARTESIAN_POINT('',(9.04843244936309,15.6723447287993,-16.0854590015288));
#1745=CARTESIAN_POINT('',(9.09732726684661,15.7570330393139,-16.131565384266));
#1746=CARTESIAN_POINT('',(9.09841483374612,15.7589167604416,-16.1325852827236));
#1747=CARTESIAN_POINT('',(9.0995034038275,15.7608022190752,-16.1336004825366));
#1748=B_SPLINE_CURVE_WITH_KNOTS('',3,(#1728,#1729,#1730,#1731,#1732,#1733,#1734,#1735,#1736,
#1737,#1738,#1739,#1740,#1741,#1742,#1743,#1744,#1745,#1746,#1747),.UNSPECIFIED.,.F.,.F.,(4,2,2,
2,2,2,2,2,2,4),(0.,0.103218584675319,0.206344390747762,0.411135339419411,0.615234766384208,
0.819717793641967,1.04997553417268,1.28015595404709,1.59726820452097,1.60447529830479),.UNSPECIFIED.);
#1749=EDGE_CURVE('E260',#1444,#697,#1748,.F.);
#1750=ORIENTED_EDGE('',*,*,#1749,.F.);
#1751=ORIENTED_EDGE('',*,*,#1445,.F.);
#1752=EDGE_LOOP('',(#1726,#1727,#1750,#1751));
#1753=FACE_BOUND('',#1752,.T.);
#1754=ADVANCED_FACE('F236',(#1753),#804,.F.);
#1755=ORIENTED_EDGE('',*,*,#1720,.T.);
#1756=ORIENTED_EDGE('',*,*,#1562,.F.);
#1757=CARTESIAN_POINT('',(8.66025403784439,-15.,-14.889067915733));
#1758=CARTESIAN_POINT('',(8.66025308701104,-14.9999983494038,-14.9235025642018));
#1759=CARTESIAN_POINT('',(8.66107063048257,-15.0014143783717,-14.957910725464));
#1760=CARTESIAN_POINT('',(8.66427264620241,-15.0069604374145,-15.0264047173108));
#1761=CARTESIAN_POINT('',(8.66665570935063,-15.0110880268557,-15.0604908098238));
#1762=CARTESIAN_POINT('',(8.67600621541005,-15.0272835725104,-15.1614766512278));
#1763=CARTESIAN_POINT('',(8.6851770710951,-15.0431679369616,-15.2275979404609));
#1764=CARTESIAN_POINT('',(8.70865909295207,-15.0838400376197,-15.3557315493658));
#1765=CARTESIAN_POINT('',(8.72295279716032,-15.1085975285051,-15.417756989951));
#1766=CARTESIAN_POINT('',(8.75598425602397,-15.1658096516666,-15.5369883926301));
#1767=CARTESIAN_POINT('',(8.77473031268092,-15.1982786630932,-15.5941850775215));
#1768=CARTESIAN_POINT('',(8.81858127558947,-15.2742308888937,-15.7097176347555));
#1769=CARTESIAN_POINT('',(8.84418986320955,-15.3185865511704,-15.7672883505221));
#1770=CARTESIAN_POINT('',(8.89926275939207,-15.4139756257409,-15.8743388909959));
#1771=CARTESIAN_POINT('',(8.92872577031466,-15.4650067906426,-15.9238214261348));
#1772=CARTESIAN_POINT('',(9.00259082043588,-15.5929445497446,-16.0313023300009));
#1773=CARTESIAN_POINT('',(9.04843244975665,-15.6723447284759,-16.0854590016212));
#1774=CARTESIAN_POINT('',(9.09732726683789,-15.7570330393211,-16.1315653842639));
#1775=CARTESIAN_POINT('',(9.09841483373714,-15.758916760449,-16.1325852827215));
#1776=CARTESIAN_POINT('',(9.09950340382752,-15.7608022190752,-16.1336004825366));
#1777=B_SPLINE_CURVE_WITH_KNOTS('',3,(#1757,#1758,#1759,#1760,#1761,#1762,#1763,#1764,#1765,
#1766,#1767,#1768,#1769,#1770,#1771,#1772,#1773,#1774,#1775,#1776),.UNSPECIFIED.,.F.,.F.,(4,2,2,
2,2,2,2,2,2,4),(0.,0.103218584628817,0.206344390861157,0.411135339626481,0.615234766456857,
0.819717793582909,1.04997553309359,1.28015595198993,1.59726820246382,1.60447529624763),.UNSPECIFIED.);
#1778=EDGE_CURVE('E254',#226,#1522,#1777,.T.);
#1779=ORIENTED_EDGE('',*,*,#1778,.F.);
#1780=ORIENTED_EDGE('',*,*,#227,.F.);
#1781=EDGE_LOOP('',(#1755,#1756,#1779,#1780));
#1782=FACE_BOUND('',#1781,.T.);
#1783=ADVANCED_FACE('F229',(#1782),#189,.F.);
#1784=ORIENTED_EDGE('',*,*,#1749,.T.);
#1785=ORIENTED_EDGE('',*,*,#1058,.F.);
#1786=CARTESIAN_POINT('',(17.3205080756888,0.,-14.889067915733));
#1787=CARTESIAN_POINT('',(17.3205061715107,5.40264467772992E-11,-14.9235025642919));
#1788=CARTESIAN_POINT('',(17.3221412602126,-5.28749655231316E-10,-14.95791072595));
#1789=CARTESIAN_POINT('',(17.3285452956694,-1.68700531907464E-09,-15.0264047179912));
#1790=CARTESIAN_POINT('',(17.3333114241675,-2.26249096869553E-09,-15.0604908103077));
#1791=CARTESIAN_POINT('',(17.3520124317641,-2.06435365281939E-09,-15.1614766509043));
#1792=CARTESIAN_POINT('',(17.3703541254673,5.98568189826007E-10,-15.2275979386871));
#1793=CARTESIAN_POINT('',(17.417318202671,-5.96544999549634E-10,-15.3557315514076));
#1794=CARTESIAN_POINT('',(17.4459056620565,-4.43259096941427E-09,-15.4177569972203));
#1795=CARTESIAN_POINT('',(17.5119685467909,-5.41880878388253E-09,-15.5369883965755));
#1796=CARTESIAN_POINT('',(17.5494605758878,-2.5564011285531E-09,-15.5941850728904));
#1797=CARTESIAN_POINT('',(17.6371626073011,2.87863356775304E-09,-15.7097176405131));
#1798=CARTESIAN_POINT('',(17.6883800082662,5.36925594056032E-09,-15.76728837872));
#1799=CARTESIAN_POINT('',(17.7985258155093,4.59845956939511E-09,-15.8743389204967));
#1800=CARTESIAN_POINT('',(17.85745162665,1.3389720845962E-09,-15.9238214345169));
#1801=CARTESIAN_POINT('',(18.0051815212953,-1.84465873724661E-09,-16.0313023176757));
#1802=CARTESIAN_POINT('',(18.0968648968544,-4.42372183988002E-11,-16.0854590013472));
#1803=CARTESIAN_POINT('',(18.1946545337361,7.84922517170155E-13,-16.1315653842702));
#1804=CARTESIAN_POINT('',(18.196829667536,8.78183526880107E-13,-16.1325852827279));
#1805=CARTESIAN_POINT('',(18.199006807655,0.,-16.1336004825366));
#1806=B_SPLINE_CURVE_WITH_KNOTS('',3,(#1786,#1787,#1788,#1789,#1790,#1791,#1792,#1793,#1794,
#1795,#1796,#1797,#1798,#1799,#1800,#1801,#1802,#1803,#1804,#1805),.UNSPECIFIED.,.F.,.F.,(4,2,2,
2,2,2,2,2,2,4),(0.,0.103218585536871,0.206344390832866,0.411135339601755,0.61523476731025,
0.819717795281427,1.04997553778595,1.28015595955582,1.5972682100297,1.60447530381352),.UNSPECIFIED.);
#1807=EDGE_CURVE('E353',#1483,#915,#1806,.F.);
#1808=ORIENTED_EDGE('',*,*,#1807,.F.);
#1809=ORIENTED_EDGE('',*,*,#1484,.F.);
#1810=EDGE_LOOP('',(#1784,#1785,#1808,#1809));
#1811=FACE_BOUND('',#1810,.T.);
#1812=ADVANCED_FACE('F235',(#1811),#1022,.F.);
#1813=ORIENTED_EDGE('',*,*,#1778,.T.);
#1814=ORIENTED_EDGE('',*,*,#1523,.F.);
#1815=ORIENTED_EDGE('',*,*,#1807,.T.);
#1816=ORIENTED_EDGE('',*,*,#1243,.F.);
#1817=EDGE_LOOP('',(#1813,#1814,#1815,#1816));
#1818=FACE_BOUND('',#1817,.T.);
#1819=ADVANCED_FACE('F383',(#1818),#1207,.F.);
#1820=CARTESIAN_POINT('',(0.,0.,-20.));
#1821=DIRECTION('',(0.,0.,-1.));
#1822=DIRECTION('',(-1.,0.,0.));
#1823=AXIS2_PLACEMENT_3D('',#1820,#1821,#1822);
#1824=CONICAL_SURFACE('',#1823,10.,0.785398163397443);
#1825=ORIENTED_EDGE('',*,*,#1335,.F.);
#1826=EDGE_LOOP('',(#1825));
#1827=FACE_BOUND('',#1826,.T.);
#1828=ORIENTED_EDGE('',*,*,#1296,.T.);
#1829=EDGE_LOOP('',(#1828));
#1830=FACE_BOUND('',#1829,.T.);
#1831=ADVANCED_FACE('F386',(#1827,#1830),#1824,.F.);
#1832=CARTESIAN_POINT('',(0.,0.,70.8384674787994));
#1833=DIRECTION('',(0.,0.,-1.));
#1834=DIRECTION('',(-1.,0.,0.));
#1835=AXIS2_PLACEMENT_3D('',#1832,#1833,#1834);
#1836=CYLINDRICAL_SURFACE('',#1835,14.58);
#1837=CARTESIAN_POINT('',(0.,0.,4.8));
#1838=DIRECTION('',(0.,0.,-1.));
#1839=DIRECTION('',(-1.,0.,0.));
#1840=AXIS2_PLACEMENT_3D('',#1837,#1838,#1839);
#1841=CIRCLE('',#1840,14.58);
#1842=CARTESIAN_POINT('',(-14.58,0.,4.8));
#1843=VERTEX_POINT('',#1842);
#1844=EDGE_CURVE('E500',#1843,#1843,#1841,.T.);
#1845=ORIENTED_EDGE('',*,*,#1844,.T.);
#1846=EDGE_LOOP('',(#1845));
#1847=FACE_BOUND('',#1846,.T.);
#1848=ORIENTED_EDGE('',*,*,#67,.T.);
#1849=EDGE_LOOP('',(#1848));
#1850=FACE_BOUND('',#1849,.T.);
#1851=ADVANCED_FACE('F523',(#1847,#1850),#1836,.T.);
#1852=CARTESIAN_POINT('',(-8.66025403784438,-15.,4.8));
#1853=DIRECTION('',(0.,0.,-1.));
#1854=DIRECTION('',(-1.,0.,0.));
#1855=AXIS2_PLACEMENT_3D('',#1852,#1853,#1854);
#1856=PLANE('',#1855);
#1857=CARTESIAN_POINT('',(0.,0.,4.8));
#1858=DIRECTION('',(0.,0.,-1.));
#1859=DIRECTION('',(-1.,0.,0.));
#1860=AXIS2_PLACEMENT_3D('',#1857,#1858,#1859);
#1861=CIRCLE('',#1860,10.);
#1862=CARTESIAN_POINT('',(-10.,0.,4.8));
#1863=VERTEX_POINT('',#1862);
#1864=EDGE_CURVE('E506',#1863,#1863,#1861,.T.);
#1865=ORIENTED_EDGE('',*,*,#1864,.T.);
#1866=EDGE_LOOP('',(#1865));
#1867=FACE_BOUND('',#1866,.T.);
#1868=ORIENTED_EDGE('',*,*,#1844,.F.);
#1869=EDGE_LOOP('',(#1868));
#1870=FACE_BOUND('',#1869,.T.);
#1871=ADVANCED_FACE('F510',(#1867,#1870),#1856,.F.);
#1872=CARTESIAN_POINT('',(0.,0.,4.29999999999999));
#1873=DIRECTION('',(0.,0.,1.));
#1874=DIRECTION('',(1.,0.,0.));
#1875=AXIS2_PLACEMENT_3D('',#1872,#1873,#1874);
#1876=CONICAL_SURFACE('',#1875,9.5,0.785398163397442);
#1877=ORIENTED_EDGE('',*,*,#1864,.F.);
#1878=EDGE_LOOP('',(#1877));
#1879=FACE_BOUND('',#1878,.T.);
#1880=ORIENTED_EDGE('',*,*,#1324,.T.);
#1881=EDGE_LOOP('',(#1880));
#1882=FACE_BOUND('',#1881,.T.);
#1883=ADVANCED_FACE('F513',(#1879,#1882),#1876,.F.);
#1884=CLOSED_SHELL('',(#71,#298,#492,#686,#904,#1098,#1283,#1311,#1339,#1350,#1356,#1362,#1368,
#1374,#1380,#1400,#1645,#1696,#1725,#1754,#1783,#1812,#1819,#1831,#1851,#1871,#1883));
#1885=MANIFOLD_SOLID_BREP('B2',#1884);
#1886=ADVANCED_BREP_SHAPE_REPRESENTATION('',(#18,#1885),#14);
#1887=SHAPE_DEFINITION_REPRESENTATION(#9,#1886);
ENDSEC;
END-ISO-10303-21;
